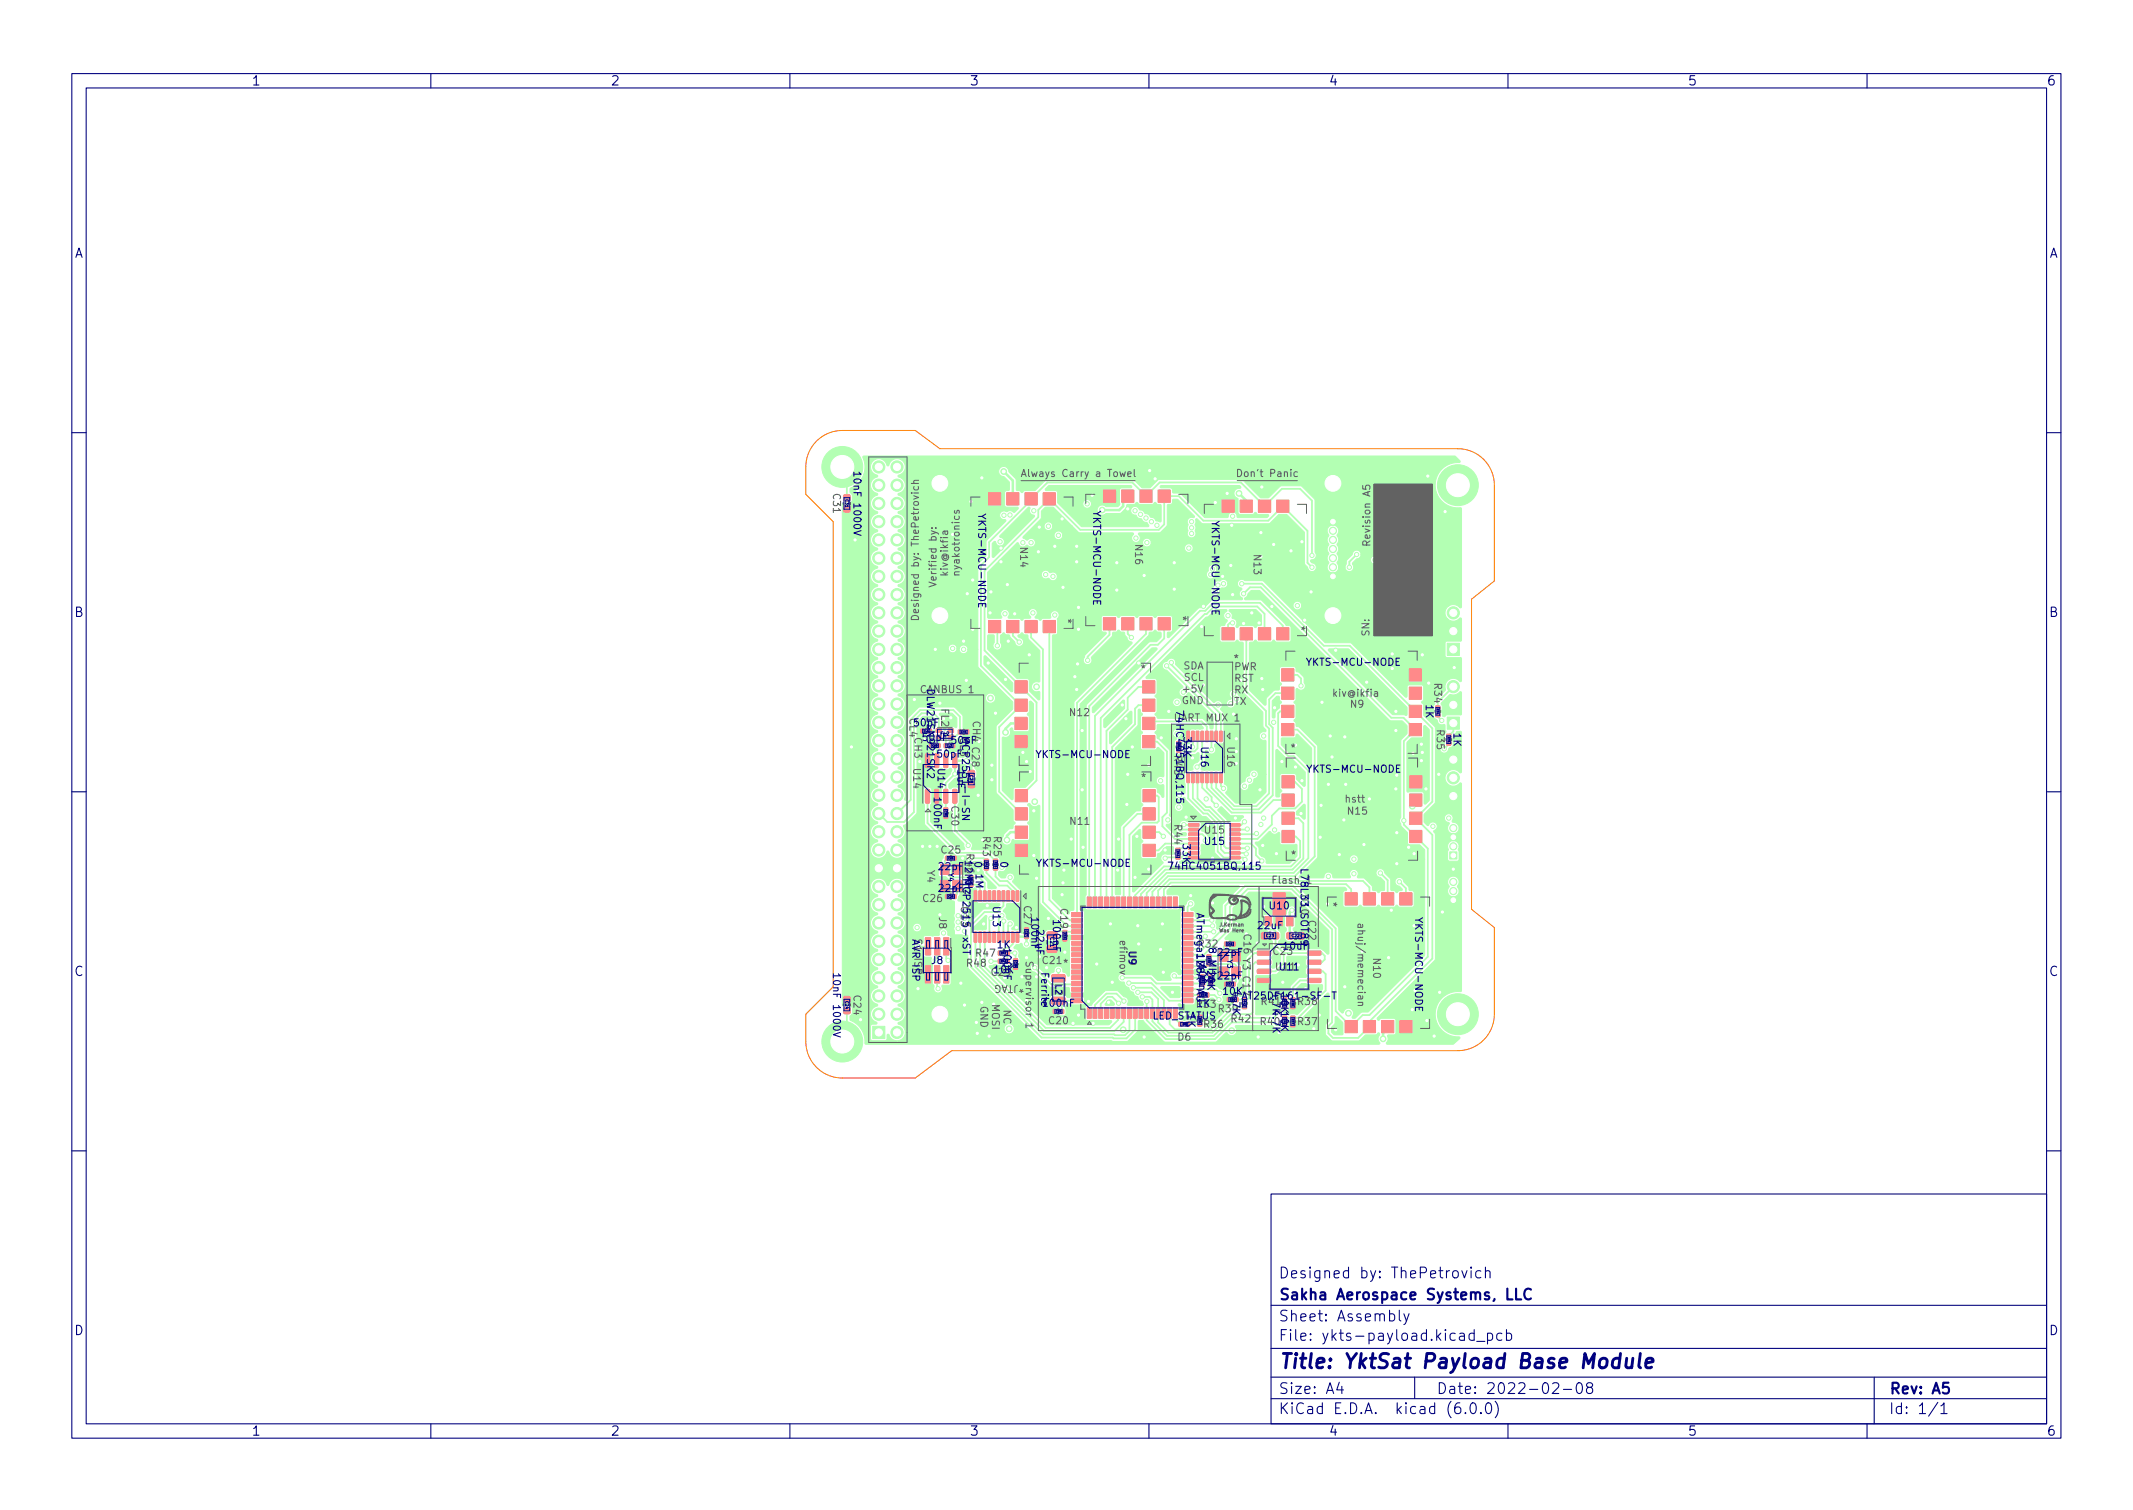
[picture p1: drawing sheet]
<svg xmlns="http://www.w3.org/2000/svg" width="297mm" height="210mm" viewBox="0 0 297 210" stroke-linecap="round" stroke-linejoin="round" font-family="sans-serif">
<defs><g id="words">
<text font-size="2.8" fill="#000080" x="178" y="190.6">Title: YktSat Payload Base Module</text>
<g font-size="2.1" fill="#000080">
<text x="178" y="178">Designed by: ThePetrovich</text>
<text x="178" y="184">Sheet: Assembly</text>
<text x="178" y="181">Sakha Aerospace Systems, LLC</text>
<text x="178" y="186.7">File: ykts-payload.kicad_pcb</text>
<text x="178" y="196.9">KiCad E.D.A. kicad (6.0.0)</text>
<text x="178" y="194.1">Size: A4</text>
<text x="200" y="194.1">Date: 2022-02-08</text>
<text x="263" y="194.1">Rev: A5</text>
<text x="263" y="196.9">Id: 1/1</text>
</g>
<g font-size="1.8" fill="#000080">
<text x="35" y="11.9">1</text>
<text x="85" y="11.9">2</text>
<text x="135" y="11.9">3</text>
<text x="185" y="11.9">4</text>
<text x="235" y="11.9">5</text>
<text x="285" y="11.9">6</text>
<text x="10.3" y="35.9">A</text>
<text x="285.3" y="35.9">A</text>
<text x="10.3" y="85.9">B</text>
<text x="285.3" y="85.9">B</text>
<text x="10.3" y="135.9">C</text>
<text x="285.3" y="135.9">C</text>
<text x="10.3" y="185.9">D</text>
<text x="285.3" y="185.9">D</text>
<text x="35" y="199.9">1</text>
<text x="85" y="199.9">2</text>
<text x="135" y="199.9">3</text>
<text x="185" y="199.9">4</text>
<text x="235" y="199.9">5</text>
<text x="285" y="199.9">6</text>
</g>
<g font-size="1.4" fill="#626262">
<text x="116" y="68.8" transform="rotate(90 116 68.8)">C31</text>
<text x="143" y="66.4">Always Carry a Towel</text>
<text x="172.7" y="66.4">Don't Panic</text>
<text x="142.1" y="76.3" transform="rotate(90 142.1 76.3)">N14</text>
<text x="158.1" y="75.9" transform="rotate(90 158.1 75.9)">N16</text>
<text x="174.6" y="77.3" transform="rotate(90 174.6 77.3)">N13</text>
<text x="190.8" y="75.7" transform="rotate(-90 190.8 75.7)">Revision A5</text>
<text x="130.4" y="81.9" transform="rotate(-90 130.4 81.9)">Verified by:</text>
<text x="132" y="81.1" transform="rotate(-90 132 81.1)">kiv@ikfia</text>
<text x="133.6" y="81.1" transform="rotate(-90 133.6 81.1)">nyakotronics</text>
<text x="128" y="85.6" transform="rotate(-90 128 85.6)">Designed by: ThePetrovich</text>
<text x="148.2" y="86.2" transform="rotate(90 148.2 86.2)">*</text>
<text x="164.2" y="85.8" transform="rotate(90 164.2 85.8)">*</text>
<text x="180.7" y="87.2" transform="rotate(90 180.7 87.2)">*</text>
<text x="190.7" y="88.6" transform="rotate(-90 190.7 88.6)">SN:</text>
<text x="158.9" y="93.6">*</text>
<text x="164.8" y="93.2">SDA</text>
<text x="164.9" y="94.8">SCL</text>
<text x="171.8" y="93.3">PWR</text>
<text x="171.8" y="94.9">RST</text>
<text x="171.9" y="92.2">*</text>
<text x="199.7" y="95.2" transform="rotate(90 199.7 95.2)">R34</text>
<text x="131.1" y="98.7" transform="rotate(90 131.1 98.7)">FL2</text>
<text x="135.5" y="100.5" transform="rotate(90 135.5 100.5)">CH4 C28</text>
<text x="149" y="99.7">N12</text>
<text x="164.6" y="98">GND</text>
<text x="165.2" y="96.4">+5V</text>
<text x="171.8" y="96.5">RX</text>
<text x="171.8" y="98.2">TX</text>
<text x="185.8" y="97">kiv@ikfia</text>
<text x="188.1" y="98.5">N9</text>
<text x="127.2" y="107.1" transform="rotate(90 127.2 107.1)">U14</text>
<text x="127.3" y="102.7" transform="rotate(90 127.3 102.7)">CH3</text>
<text x="170.9" y="104.1" transform="rotate(90 170.9 104.1)">U16</text>
<text x="179.8" y="104.6">*</text>
<text x="132.5" y="112.3" transform="rotate(90 132.5 112.3)">C30</text>
<text x="159" y="108.7">*</text>
<text x="187.4" y="111.7">hstt</text>
<text x="187.7" y="113.4">N15</text>
<text x="136.9" y="116.6" transform="rotate(90 136.9 116.6)">R43</text>
<text x="138.4" y="116.6" transform="rotate(90 138.4 116.6)">R25</text>
<text x="149.1" y="114.8">N11</text>
<text x="163.5" y="114.9" transform="rotate(90 163.5 114.9)">R44</text>
<text x="167.8" y="116.1">U15</text>
<text x="179.9" y="119.5">*</text>
<text x="128.6" y="125.6">C26</text>
<text x="129.1" y="121.2" transform="rotate(90 129.1 121.2)">Y4</text>
<text x="185.1" y="125.7" transform="rotate(90 185.1 125.7)">*</text>
<text x="130.8" y="127.7" transform="rotate(90 130.8 127.7)">J8</text>
<text x="147.7" y="126.6" transform="rotate(90 147.7 126.6)">C19</text>
<text x="155.9" y="131.1" transform="rotate(90 155.9 131.1)">efimov</text>
<text x="189.1" y="129.3" transform="rotate(90 189.1 129.3)">ahuj/memecian</text>
<text x="134.7" y="134.6">R48</text>
<text x="136" y="133.2">R47</text>
<text x="142.7" y="137.2" transform="rotate(-180 142.7 137.2)">*JTAG</text>
<text x="142.8" y="134.3" transform="rotate(90 142.8 134.3)">Supervisor 1</text>
<text x="145.2" y="134.2">C21</text>
<text x="148.1" y="134.6">*</text>
<text x="191.2" y="133.5" transform="rotate(90 191.2 133.5)">N10</text>
<text x="118.9" y="138.7" transform="rotate(90 118.9 138.7)">C24</text>
<text x="136.5" y="140.1" transform="rotate(90 136.5 140.1)">GND</text>
<text x="138.1" y="139.8" transform="rotate(90 138.1 139.8)">MOSI</text>
<text x="139.7" y="140.6" transform="rotate(90 139.7 140.6)">NC</text>
<text x="146.1" y="142.6">C20</text>
<text x="167.7" y="143.1">R36</text>
<text x="171.5" y="142.4">R42</text>
<text x="180.8" y="142.7">R37</text>
<text x="164" y="144.9">D6</text>
</g>
<g font-size="1.4" fill="#000080">
<text x="118.9" y="66.3" transform="rotate(90 118.9 66.3)">10nF 1000V</text>
<text x="152.2" y="71.8" transform="rotate(90 152.2 71.8)">YKTS-MCU-NODE</text>
<text x="136.2" y="72.2" transform="rotate(90 136.2 72.2)">YKTS-MCU-NODE</text>
<text x="168.7" y="73.2" transform="rotate(90 168.7 73.2)">YKTS-MCU-NODE</text>
<text x="182.5" y="92.7">YKTS-MCU-NODE</text>
<text x="126.6" y="100" transform="rotate(90 126.6 100)">CL4</text>
<text x="127.4" y="101.1">50pF</text>
<text x="128.3" y="96.5">CANBUS 1</text>
<text x="129.1" y="96.3" transform="rotate(90 129.1 96.3)">DLW21SN921SK2</text>
<text x="163.8" y="99.7" transform="rotate(90 163.8 99.7)">74HC4051BQ,115</text>
<text x="163.8" y="100.4">UART MUX 1</text>
<text x="198.6" y="98.2" transform="rotate(90 198.6 98.2)">1K</text>
<text x="200.1" y="101.7" transform="rotate(90 200.1 101.7)">R35</text>
<text x="128.6" y="103.2">50pF</text>
<text x="130.6" y="107.1" transform="rotate(90 130.6 107.1)">U14</text>
<text x="130.6" y="105.5">50pF</text>
<text x="132.6" y="103.6">50pF</text>
<text x="133.3" y="107.2" transform="rotate(90 133.3 107.2)">1uF</text>
<text x="133.7" y="102.7" transform="rotate(90 133.7 102.7)">CL3</text>
<text x="134" y="103.7" transform="rotate(90 134 103.7)">MCP2551-I-SN</text>
<text x="144.9" y="105.5">YKTS-MCU-NODE</text>
<text x="163.5" y="105.3" transform="rotate(90 163.5 105.3)">R45</text>
<text x="164.8" y="102.7" transform="rotate(90 164.8 102.7)">33K</text>
<text x="167.2" y="104.1" transform="rotate(90 167.2 104.1)">U16</text>
<text x="182.6" y="107.6">YKTS-MCU-NODE</text>
<text x="202.4" y="102.1" transform="rotate(90 202.4 102.1)">1K</text>
<text x="130" y="111.2" transform="rotate(90 130 111.2)">100nF</text>
<text x="131.1" y="118.8">C25</text>
<text x="134.4" y="120" transform="rotate(90 134.4 120)">12MHz</text>
<text x="134.6" y="119" transform="rotate(90 134.6 119)">R46</text>
<text x="164.7" y="117.6" transform="rotate(90 164.7 117.6)">33K</text>
<text x="167.8" y="117.6">U15</text>
<text x="130.8" y="124.2">22pF</text>
<text x="130.8" y="121.2">22pF</text>
<text x="134.1" y="123" transform="rotate(90 134.1 123)">MCP2515-xST</text>
<text x="135.7" y="120" transform="rotate(90 135.7 120)">0</text>
<text x="135.9" y="121.7" transform="rotate(90 135.9 121.7)">1M</text>
<text x="139.3" y="120" transform="rotate(90 139.3 120)">0</text>
<text x="145" y="120.7">YKTS-MCU-NODE</text>
<text x="163.4" y="121.1">74HC4051BQ,115</text>
<text x="177.5" y="123">Flash 1</text>
<text x="181.1" y="121.3" transform="rotate(90 181.1 121.3)">L78L33_SOT89</text>
<text x="181.2" y="124.7" transform="rotate(90 181.2 124.7)">U10</text>
<text x="127.3" y="131" transform="rotate(90 127.3 131)">S1 ISP</text>
<text x="133.8" y="126.4" transform="rotate(90 133.8 126.4)">U13</text>
<text x="138.3" y="126.4" transform="rotate(90 138.3 126.4)">U13</text>
<text x="142.6" y="126.2" transform="rotate(90 142.6 126.2)">C27</text>
<text x="143.6" y="127.9" transform="rotate(90 143.6 127.9)">100nF</text>
<text x="144.3" y="129.6" transform="rotate(90 144.3 129.6)">22uF</text>
<text x="146.6" y="128.3" transform="rotate(90 146.6 128.3)">100nF</text>
<text x="166.6" y="127.7" transform="rotate(90 166.6 127.7)">ATmega128A-AU</text>
<text x="166.9" y="131.9">R32</text>
<text x="173.2" y="130.2" transform="rotate(90 173.2 130.2)">C16 Y3 C17</text>
<text x="175.2" y="129.4">22uF</text>
<text x="176.9" y="126.6">U10</text>
<text x="182.2" y="128.3" transform="rotate(90 182.2 128.3)">C22</text>
<text x="197.1" y="128.4" transform="rotate(90 197.1 128.4)">YKTS-MCU-NODE</text>
<text x="116" y="136.1" transform="rotate(90 116 136.1)">10nF 1000V</text>
<text x="129.7" y="134.2">J8</text>
<text x="138.1" y="135.9">C29</text>
<text x="138.5" y="135.5">10K</text>
<text x="138.9" y="132">1K</text>
<text x="139.8" y="132.2" transform="rotate(90 139.8 132.2)">100nF</text>
<text x="145" y="135.6" transform="rotate(90 145 135.6)">Ferrite</text>
<text x="146.9" y="137" transform="rotate(90 146.9 137)">L2</text>
<text x="157.2" y="132.5" transform="rotate(90 157.2 132.5)">U9</text>
<text x="166.7" y="132.8" transform="rotate(90 166.7 132.8)">1M100nF</text>
<text x="168.1" y="135.2" transform="rotate(90 168.1 135.2)">20K</text>
<text x="168.3" y="132.2" transform="rotate(90 168.3 132.2)">8 MHz</text>
<text x="169.6" y="136.4">22pF</text>
<text x="169.6" y="133.1">22pF</text>
<text x="177.4" y="133">C23</text>
<text x="177.7" y="135.1">U11</text>
<text x="178.3" y="135.1">U11</text>
<text x="178.8" y="132.2">10uF</text>
<text x="145.4" y="140.2">100nF</text>
<text x="160.4" y="141.9">LED_STATUS</text>
<text x="165.4" y="141.2" transform="rotate(90 165.4 141.2)">1K</text>
<text x="166.7" y="140.2">1K</text>
<text x="169.7" y="141">R39</text>
<text x="170.4" y="138.5">10K</text>
<text x="171.6" y="138.2" transform="rotate(90 171.6 138.2)">4.7K</text>
<text x="174" y="139.2">AT25DF161-SF-T</text>
<text x="175.6" y="142.7">R40</text>
<text x="175.7" y="139.9">R41</text>
<text x="177.2" y="138.2" transform="rotate(90 177.2 138.2)">4.7K</text>
<text x="178.4" y="138.4" transform="rotate(90 178.4 138.4)">10K10K</text>
<text x="180.8" y="139.9">R38</text>
</g>
<g font-size="1" fill="#000080">
<text x="132.1" y="121.6" transform="rotate(90 132.1 121.6)">Y4</text>
<text x="170.9" y="133.6" transform="rotate(90 170.9 133.6)">Y3</text>
</g>
<g font-size=".7" fill="#000080">
<text x="131" y="102.4">FL2</text>
<text x="146.3" y="130.5" transform="rotate(90 146.3 130.5)">C21</text>
</g>
<g font-size=".7" fill="#626262">
<text x="169.9" y="129">J.Kerman</text>
<text x="169.9" y="129.8">Was Here</text>
</g>
<g font-size=".6" fill="#000080">
<text x="117.7" y="69.6" transform="rotate(90 117.7 69.6)">C31</text>
<text x="135.1" y="108" transform="rotate(90 135.1 108)">C28</text>
<text x="176.3" y="130.5">C23</text>
<text x="179.9" y="130.5">C22</text>
<text x="117.7" y="139.4" transform="rotate(90 117.7 139.4)">C24</text>
</g>
<g font-size=".4" fill="#000080">
<text x="200.1" y="98.7" transform="rotate(90 200.1 98.7)">R34</text>
<text x="164" y="103.7" transform="rotate(90 164 103.7)">R45</text>
<text x="201.6" y="102.7" transform="rotate(90 201.6 102.7)">R35</text>
<text x="163.9" y="118.5" transform="rotate(90 163.9 118.5)">R44</text>
<text x="135.1" y="122.3" transform="rotate(90 135.1 122.3)">R46</text>
<text x="137.2" y="120.1" transform="rotate(90 137.2 120.1)">R43</text>
<text x="138.5" y="120.1" transform="rotate(90 138.5 120.1)">R25</text>
<text x="139.4" y="134">R48</text>
<text x="139.4" y="132.8">R47</text>
<text x="167.3" y="136.2" transform="rotate(90 167.3 136.2)">R31</text>
<text x="168.2" y="133.4" transform="rotate(90 168.2 133.4)">R32</text>
<text x="167" y="141.8" transform="rotate(90 167 141.8)">R36</text>
<text x="167.3" y="138.7">R33</text>
<text x="171.3" y="139.3">R39</text>
<text x="173.2" y="139.4" transform="rotate(90 173.2 139.4)">R42</text>
<text x="178.8" y="139.4" transform="rotate(90 178.8 139.4)">R41</text>
<text x="178.8" y="141.9" transform="rotate(90 178.8 141.9)">R40</text>
<text x="179.9" y="139.4" transform="rotate(90 179.9 139.4)">R38</text>
<text x="179.9" y="141.9" transform="rotate(90 179.9 141.9)">R37</text>
</g>
<g font-size=".3" fill="#000080">
<text x="128.7" y="101.9">CL4</text>
<text x="129.8" y="103.9">CH3</text>
<text x="131.9" y="103.9">CL3</text>
<text x="133.8" y="102">CH4</text>
<text x="131.6" y="112.9" transform="rotate(90 131.6 112.9)">C30</text>
<text x="132.1" y="119.6">C25</text>
<text x="132.1" y="125">C26</text>
<text x="142.8" y="129.6" transform="rotate(90 142.8 129.6)">C27</text>
<text x="148.2" y="130" transform="rotate(90 148.2 130)">C19</text>
<text x="171" y="131.6">C16</text>
<text x="141.3" y="133.9" transform="rotate(90 141.3 133.9)">C29</text>
<text x="168.5" y="136.2" transform="rotate(90 168.5 136.2)">C18</text>
<text x="171" y="137.2">C17</text>
<text x="147.1" y="141">C20</text>
<text x="164.7" y="142.7">D6</text>
</g>
</g></defs>
<g fill="#b3ffb3" stroke="#b3ffb3" stroke-width=".14">
<path d="M169.8 107.6h.4v1.4l-.4-.1z"/>
<path d="M169.2 107.6h.4l-.1 1.4-.3-.1z"/>
<path d="M168.5 107.6h.4v1.4l-.4-.1z"/>
<path d="M167.9 107.6h.4l-.1 1.4-.3-.1z"/>
<path d="M167.2 107.6h.4v1.4l-.4-.1z"/>
<path d="M166.6 107.6h.4l-.1 1.4-.3-.1z"/>
<path d="M165.9 107.6h.4v1.4l-.4-.1z"/>
<path d="M165.3 107.6h.4l-.1 1.4-.3-.1z"/>
<path d="M165.3 101.8l.4 .1-.1 1.4-.3-.1z"/>
<path d="M165.9 101.8l.4 .1v1.4l-.4-.1z"/>
<path d="M166.6 101.8l.4 .1-.1 1.4-.3-.1z"/>
<path d="M167.2 101.8l.4 .1v1.4l-.4-.1z"/>
<path d="M167.9 101.8l.4 .1-.1 1.4-.3-.1z"/>
<path d="M168.5 101.8l.4 .1v1.4l-.4-.1z"/>
<path d="M169.2 101.8l.4 .1-.1 1.4-.3-.1z"/>
<path d="M169.8 101.8l.4 .1v1.4l-.4-.1z"/>
<path d="M171.3 114.7h1.4v.3l-1.4 .1z"/>
<path d="M171.3 115.3h1.4v.4h-1.4z"/>
<path d="M171.3 116h1.4v.3l-1.4 .1z"/>
<path d="M171.3 116.6h1.4v.4h-1.4z"/>
<path d="M171.3 117.3h1.4v.3l-1.4 .1z"/>
<path d="M171.3 117.9h1.4v.4h-1.4z"/>
<path d="M171.3 118.6h1.4v.3l-1.4 .1z"/>
<path d="M171.3 119.2h1.4v.4h-1.4z"/>
<path d="M165.5 119.2h1.4l.1 .4h-1.4z"/>
<path d="M165.5 118.6h1.4l.1 .3-1.4 .1z"/>
<path d="M165.5 117.9h1.4l.1 .4h-1.4z"/>
<path d="M165.5 117.3h1.4l.1 .3-1.4 .1z"/>
<path d="M165.5 116.6h1.4l.1 .4h-1.4z"/>
<path d="M165.5 116h1.4l.1 .3-1.4 .1z"/>
<path d="M165.5 115.3h1.4l.1 .4h-1.4z"/>
<path d="M165.5 114.7h1.4l.1 .3-1.4 .1z"/>
<path d="M175.1 132.5l1.8-.1 .1 .5-.2 .1h-1.6l-.1-.1z"/>
<path d="M175.1 133.7h1.8l.1 .5-.2 .1h-1.6l-.1-.2z"/>
<path d="M175.1 135h1.8l.1 .5h-.2h-1.6l-.1-.1z"/>
<path d="M175.1 136.3l1.8-.1 .1 .5-.2 .1h-1.6l-.1-.1z"/>
<path d="M182.1 136.3l1.8-.1 .1 .5-.2 .1h-1.6l-.1-.1z"/>
<path d="M182.1 135h1.8l.1 .5h-.2h-1.6l-.1-.1z"/>
<path d="M182.1 133.7h1.8l.1 .5-.2 .1h-1.6l-.1-.2z"/>
<path d="M182.1 132.5l1.8-.1 .1 .5-.2 .1h-1.6l-.1-.1z"/>
<path d="M176.2 127.6h.9v1.3h-.9z"/>
<path d="M179.2 127.6h.9v1.3h-.9z"/>
<path d="M177.3 124.3h1.7v3.1h-.4v1.5h-.9v-1.5h-.4z"/>
<path d="M163.8 119.1h.5v.5h-.5z"/>
<path d="M163.8 118.1h.5v.5h-.5z"/>
<path d="M173 139h.6v.4h-.6z"/>
<path d="M173 140h.6v.4h-.6z"/>
<path d="M170.9 138.9h.5v.6h-.5z"/>
<path d="M179.8 140h.5v.4h-.5z"/>
<path d="M179.8 141.5h.5v.5h-.5z"/>
<path d="M179.8 142.5h.5v.5h-.5z"/>
<path d="M177.3 129.9h.7v.8h-.7z"/>
<path d="M175.7 129.9h.8v.8h-.8z"/>
<path d="M179.3 129.9h.7v.8h-.7z"/>
<path d="M121.5 142.9h1.7v1.7h-1.7z"/>
<path d="M201.5 89.6h1.7v1.7h-1.7z"/>
<path d="M185.1 79.8h1v1h-1z"/>
<path d="M201.9 118.6h1v1h-1z"/>
<path d="M201.5 110h1.7v1.7h-1.7z"/>
<path d="M201.5 99.8h1.7v1.7h-1.7z"/>
<path d="M201.9 124.8h1v1h-1z"/>
<path d="M133.5 101.7h.4v.5h-.4z"/>
<path d="M134.4 101.7h.5v.5h-.5z"/>
<path d="M132 102.4h.8v.5h-.8z"/>
<path d="M132 101.5h.8v.5h-.8z"/>
<path d="M130.4 101.5h.7v.5h-.7z"/>
<path d="M138.4 120.7h.5v.4h-.5z"/>
<path d="M138.4 119.6h.5v.5h-.5z"/>
<path d="M132.7 124.6h.4v.5h-.4z"/>
<path d="M131.7 124.6h.5v.5h-.5z"/>
<path d="M169.8 134.6h1.2v1.4h-1.2z"/>
<path d="M171.5 134.6h1.2v1.4h-1.2z"/>
<path d="M159.1 94.8h1.7v1.7h-1.7z"/>
<path d="M159.1 97.3h1.7v1.7h-1.7z"/>
<path d="M159.1 99.9h1.7v1.7h-1.7z"/>
<path d="M159.1 102.4h1.7v1.7h-1.7z"/>
<path d="M141.3 94.8h1.7v1.7h-1.7z"/>
<path d="M141.3 97.3h1.7v1.7h-1.7z"/>
<path d="M141.3 99.9h1.7v1.7h-1.7z"/>
<path d="M141.3 102.4h1.7v1.7h-1.7z"/>
<path d="M141.2 133.5h.5v.5h-.5z"/>
<path d="M141.2 134.5h.5v.5h-.5z"/>
<path d="M146.5 135.8l1.7-.1 .1 .2v.7l-.2 .1h-1.5l-.2-.2z"/>
<path d="M130.4 103.6h.5v.5h-.5z"/>
<path d="M177.8 87.4h1.7v1.7h-1.7z"/>
<path d="M175.2 87.4h1.7v1.7h-1.7z"/>
<path d="M172.7 87.4h1.7v1.7h-1.7z"/>
<path d="M170.2 87.4h1.7v1.7h-1.7z"/>
<path d="M177.8 69.6h1.7v1.7h-1.7z"/>
<path d="M175.2 69.6h1.7v1.7h-1.7z"/>
<path d="M172.7 69.6h1.7v1.7h-1.7z"/>
<path d="M170.2 69.6h1.7v1.7h-1.7z"/>
<path d="M166.8 142.4h.6v.4h-.6z"/>
<path d="M187.3 124.3h1.7v1.7h-1.7z"/>
<path d="M189.9 124.3h1.7v1.7h-1.7z"/>
<path d="M192.4 124.3h1.7v1.7h-1.7z"/>
<path d="M194.9 124.3h1.7v1.7h-1.7z"/>
<path d="M187.3 142.1h1.7v1.7h-1.7z"/>
<path d="M189.9 142.1h1.7v1.7h-1.7z"/>
<path d="M192.4 142.1h1.7v1.7h-1.7z"/>
<path d="M194.9 142.1h1.7v1.7h-1.7z"/>
<path d="M139 133.6h.5v.5h-.5z"/>
<path d="M131.7 119.2h.5v.6h-.5z"/>
<path d="M132.7 119.2h.4v.6h-.4z"/>
<path d="M149.2 139.1h1.5v.5h-1.5z"/>
<path d="M149.2 138.3h1.5v.5h-1.5z"/>
<path d="M149.2 137.5h1.5v.5h-1.5z"/>
<path d="M149.2 136.7h1.5v.5h-1.5z"/>
<path d="M149.2 135.9h1.5v.5h-1.5z"/>
<path d="M149.2 135.1h1.5v.5h-1.5z"/>
<path d="M149.2 134.3h1.5v.5h-1.5z"/>
<path d="M149.2 133.5h1.5v.5h-1.5z"/>
<path d="M149.2 132.7h1.5v.5h-1.5z"/>
<path d="M149.2 131.9h1.5v.5h-1.5z"/>
<path d="M149.2 131.1h1.5v.5h-1.5z"/>
<path d="M149.2 130.3h1.5v.5h-1.5z"/>
<path d="M149.2 129.5h1.5v.5h-1.5z"/>
<path d="M149.2 128.7h1.5v.5h-1.5z"/>
<path d="M149.2 127.9h1.5v.5h-1.5z"/>
<path d="M149.2 127.1h1.5v.5h-1.5z"/>
<path d="M151.4 124.9h.6v1.5h-.6z"/>
<path d="M152.2 124.9h.6v1.5h-.6z"/>
<path d="M153 124.9h.6v1.5h-.6z"/>
<path d="M153.8 124.9h.6v1.5h-.6z"/>
<path d="M154.6 124.9h.6v1.5h-.6z"/>
<path d="M155.4 124.9h.6v1.5h-.6z"/>
<path d="M156.2 124.9h.6v1.5h-.6z"/>
<path d="M157 124.9h.6v1.5h-.6z"/>
<path d="M157.8 124.9h.6v1.5h-.6z"/>
<path d="M158.6 124.9h.6v1.5h-.6z"/>
<path d="M159.4 124.9h.6v1.5h-.6z"/>
<path d="M160.2 124.9h.6v1.5h-.6z"/>
<path d="M161 124.9h.6v1.5h-.6z"/>
<path d="M161.8 124.9h.6v1.5h-.6z"/>
<path d="M162.6 124.9h.6v1.5h-.6z"/>
<path d="M163.4 124.9h.6v1.5h-.6z"/>
<path d="M164.6 127.1h1.5v.5h-1.5z"/>
<path d="M164.6 127.9h1.5v.5h-1.5z"/>
<path d="M164.6 128.7h1.5v.5h-1.5z"/>
<path d="M164.6 129.5h1.5v.5h-1.5z"/>
<path d="M164.6 130.3h1.5v.5h-1.5z"/>
<path d="M164.6 131.1h1.5v.5h-1.5z"/>
<path d="M164.6 131.9h1.5v.5h-1.5z"/>
<path d="M164.6 132.7h1.5v.5h-1.5z"/>
<path d="M164.6 133.5h1.5v.5h-1.5z"/>
<path d="M164.6 134.3h1.5v.5h-1.5z"/>
<path d="M164.6 135.1h1.5v.5h-1.5z"/>
<path d="M164.6 135.9h1.5v.5h-1.5z"/>
<path d="M164.6 136.7h1.5v.5h-1.5z"/>
<path d="M164.6 137.5h1.5v.5h-1.5z"/>
<path d="M164.6 138.3h1.5v.5h-1.5z"/>
<path d="M164.6 139.1h1.5v.5h-1.5z"/>
<path d="M163.4 140.3h.6v1.5h-.6z"/>
<path d="M162.6 140.3h.6v1.5h-.6z"/>
<path d="M161.8 140.3h.6v1.5h-.6z"/>
<path d="M161 140.3h.6v1.5h-.6z"/>
<path d="M160.2 140.3h.6v1.5h-.6z"/>
<path d="M159.4 140.3h.6v1.5h-.6z"/>
<path d="M158.6 140.3h.6v1.5h-.6z"/>
<path d="M157.8 140.3h.6v1.5h-.6z"/>
<path d="M157 140.3h.6v1.5h-.6z"/>
<path d="M156.2 140.3h.6v1.5h-.6z"/>
<path d="M155.4 140.3h.6v1.5h-.6z"/>
<path d="M154.6 140.3h.6v1.5h-.6z"/>
<path d="M153.8 140.3h.6v1.5h-.6z"/>
<path d="M153 140.3h.6v1.5h-.6z"/>
<path d="M152.2 140.3h.6v1.5h-.6z"/>
<path d="M151.4 140.3h.6v1.5h-.6z"/>
<path d="M139 132.4h.5v.6h-.5z"/>
<path d="M117.5 138.8h.8v.8h-.8z"/>
<path d="M117.5 140.3h.8v.8h-.8z"/>
<path d="M201.5 103.3h.5v.4h-.5z"/>
<path d="M201.5 102.3h.5v.4h-.5z"/>
<path d="M141.5 124.1h.4l-.1 1.4-.3-.1z"/>
<path d="M140.9 124.1h.3v1.4l-.4-.1z"/>
<path d="M140.2 124.1h.4l-.1 1.4-.3-.1z"/>
<path d="M139.6 124.1h.3v1.4l-.4-.1z"/>
<path d="M138.9 124.1h.4l-.1 1.4-.3-.1z"/>
<path d="M138.3 124.1h.3v1.4l-.4-.1z"/>
<path d="M137.6 124.1h.4l-.1 1.4-.3-.1z"/>
<path d="M137 124.1h.3v1.4l-.4-.1z"/>
<path d="M136.3 124.1h.4l-.1 1.4-.3-.1z"/>
<path d="M135.7 124.1h.3v1.4l-.4-.1z"/>
<path d="M135.7 129.8h.3v1.4h-.4z"/>
<path d="M136.3 129.8h.4l-.1 1.4h-.3z"/>
<path d="M137 129.8h.3v1.4h-.4z"/>
<path d="M137.6 129.8h.4l-.1 1.4h-.3z"/>
<path d="M138.3 129.8h.3v1.4h-.4z"/>
<path d="M138.9 129.8h.4l-.1 1.4h-.3z"/>
<path d="M139.6 129.8h.3v1.4h-.4z"/>
<path d="M140.2 129.8h.4l-.1 1.4h-.3z"/>
<path d="M140.9 129.8h.3v1.4h-.4z"/>
<path d="M141.5 129.8h.4l-.1 1.4h-.3z"/>
<path d="M164.2 142.3h.5v.6h-.5z"/>
<path d="M178.5 100.7h1.7v1.7h-1.7z"/>
<path d="M178.5 98.2h1.7v1.7h-1.7z"/>
<path d="M178.5 95.7h1.7v1.7h-1.7z"/>
<path d="M178.5 93.1h1.7v1.7h-1.7z"/>
<path d="M196.3 100.7h1.7v1.7h-1.7z"/>
<path d="M196.3 98.2h1.7v1.7h-1.7z"/>
<path d="M196.3 95.7h1.7v1.7h-1.7z"/>
<path d="M196.3 93.1h1.7v1.7h-1.7z"/>
<path d="M137.1 119.6h.5v.5h-.5z"/>
<path d="M137.1 120.7h.5v.4h-.5z"/>
<path d="M131.5 103.6h.5v.5h-.5z"/>
<path d="M128.3 101.5h.4v.6h-.4z"/>
<path d="M171.5 136.8h.5v.5h-.5z"/>
<path d="M170.6 136.8h.4v.5h-.4z"/>
<path d="M159.2 109.9h1.7v1.7h-1.7z"/>
<path d="M159.2 112.5h1.7v1.7h-1.7z"/>
<path d="M159.2 115h1.7v1.7h-1.7z"/>
<path d="M159.2 117.6h1.7v1.7h-1.7z"/>
<path d="M141.4 109.9h1.7v1.7h-1.7z"/>
<path d="M141.4 112.5h1.7v1.7h-1.7z"/>
<path d="M141.4 115h1.7v1.7h-1.7z"/>
<path d="M141.4 117.6h1.7v1.7h-1.7z"/>
<path d="M145.3 86.4h1.7v1.7h-1.7z"/>
<path d="M142.7 86.4h1.7v1.7h-1.7z"/>
<path d="M140.2 86.4h1.7v1.7h-1.7z"/>
<path d="M137.7 86.4h1.7v1.7h-1.7z"/>
<path d="M145.3 68.6h1.7v1.7h-1.7z"/>
<path d="M142.7 68.6h1.7v1.7h-1.7z"/>
<path d="M140.2 68.6h1.7v1.7h-1.7z"/>
<path d="M137.7 68.6h1.7v1.7h-1.7z"/>
<path d="M131.4 112.5h.6v.5h-.6z"/>
<path d="M131.4 113.5h.6v.4h-.6z"/>
<path d="M147.6 140.6h.5v.5h-.5z"/>
<path d="M146.7 140.6h.5v.5h-.5z"/>
<path d="M178.5 115.6h1.7v1.7h-1.7z"/>
<path d="M178.5 113.1h1.7v1.7h-1.7z"/>
<path d="M178.5 110.5h1.7v1.7h-1.7z"/>
<path d="M178.5 108h1.7v1.7h-1.7z"/>
<path d="M196.3 115.6h1.7v1.7h-1.7z"/>
<path d="M196.3 113.1h1.7v1.7h-1.7z"/>
<path d="M196.3 110.5h1.7v1.7h-1.7z"/>
<path d="M196.3 108h1.7v1.7h-1.7z"/>
<path d="M128.9 109.9h.4l.2 .1v1.7l-.1 .1h-.5z"/>
<path d="M130.2 109.9h.4l.1 .1v1.7l-.1 .1h-.5z"/>
<path d="M131.4 109.9h.5l.1 .1v1.7l-.1 .1h-.5z"/>
<path d="M132.7 109.9h.4l.2 .1v1.7l-.1 .1h-.5z"/>
<path d="M132.7 105l.4-.1 .2 .1v1.7l-.1 .2-.5-.1z"/>
<path d="M131.4 105l.5-.1 .1 .1v1.7l-.1 .2-.5-.1z"/>
<path d="M130.2 105l.4-.1 .1 .1v1.7l-.1 .2-.5-.1z"/>
<path d="M142.7 130.2h.5v.5h-.5z"/>
<path d="M142.7 129.2h.5v.5h-.5z"/>
<path d="M132.7 122.6h1.2v1.4h-1.2z"/>
<path d="M131 122.6h1.2v1.4h-1.2z"/>
<path d="M199.9 98.3h.6v.5h-.6z"/>
<path d="M199.9 99.3h.6v.5h-.6z"/>
<path d="M134.9 107.3h.8v.8h-.8z"/>
<path d="M134.9 108.9h.8v.7h-.8z"/>
<path d="M170.6 131.2h.4v.5h-.4z"/>
<path d="M171.5 131.2h.5v.5h-.5z"/>
<path d="M148 129.6h.6v.5h-.6z"/>
<path d="M148 130.5h.6v.5h-.6z"/>
<path d="M145.9 129.8h1.2l.1 .2v.6l-.2 .1h-1.1l-.1-.2z"/>
<path d="M145.9 131.7h1.2l.1 .2v.6l-.2 .1h-1.1l-.1-.2z"/>
<path d="M117.5 70.5h.8v.8h-.8z"/>
<path d="M117.5 68.9h.8v.8h-.8z"/>
<path d="M161.3 86h1.7v1.7h-1.7z"/>
<path d="M158.7 86h1.7v1.7h-1.7z"/>
<path d="M156.2 86h1.7v1.7h-1.7z"/>
<path d="M153.7 86h1.7v1.7h-1.7z"/>
<path d="M161.3 68.2h1.7v1.7h-1.7z"/>
<path d="M158.7 68.2h1.7v1.7h-1.7z"/>
<path d="M156.2 68.2h1.7v1.7h-1.7z"/>
<path d="M153.7 68.2h1.7v1.7h-1.7z"/>
<path d="M131.4 130.6h.7v2.4h-.7z"/>
<path d="M131.4 134.5h.7v2.4h-.7z"/>
<path d="M130.1 130.6h.8v2.4h-.8z"/>
<path d="M130.1 134.5h.8v2.4h-.8z"/>
<path d="M128.9 130.6h.7v2.4h-.7z"/>
<path d="M128.9 134.5h.7v2.4h-.7z"/>
<path d="M120.2 63.6l.1-.1h82.3l.7 .7v.2a3.2 3.2 0 0 0-3.4 3.2 3.2 3.2 0 0 0 3.5 3.1l.1 .1v6.4h-14a.62 .62 0 0 0-.6-.6 .62 .62 0 0 0-.6 .7l-.8 .7v.5l-.2 .5h-.9l-.2-.6 .2-.7-.2-.6 .2-.7-.2-.5 .2-.7-.2-.6 .2-.7-.2-.5a.8 .8 0 0 0-.9-.2l-.3 .2-.2 .5 .3 .6-.3 .7 .3 .6-.3 .6 .3 .6-.3 .7 .3 .6-.2 .4a.8 .8 0 0 0 .5 1.1 .8 .8 0 0 0 1-.6v-.2h.9a.62 .62 0 0 0 .9 .5 .62 .62 0 0 0 .1-1l.6-.7 .5-.2 .1-.4h14v.8h-11.4a.6 .6 0 0 0-.9-.6 .6 .6 0 0 0-.1 1 .6 .6 0 0 0 1-.3v-.1h11.4v1.8l-7.6-.1a.6 .6 0 0 0-.9-.5 .6 .6 0 0 0-.1 1 .6 .6 0 0 0 1-.3v-.1h7.6v4.7a.16 .16 0 0 1-.1 .1 .16 .16 0 0 1-.2-.1l-.3-.2-.4-.1-.7 .1h-20.5a.61 .61 0 0 0-.9-.5 .61 .61 0 0 0-.1 1 .61 .61 0 0 0 1-.3v-.2h20.5a1.15 1.15 0 0 0-.1 1.9h-4.5l-.2-.4a.77 .77 0 0 0-.4-1 .63 .63 0 0 0-.7 .3 .63 .63 0 0 0 .1 .7 .62 .62 0 0 0 .3 1 .62 .62 0 0 0 .9-.6l4.5 .1a1.26 1.26 0 0 0 1.7-.3l.1 .2v3l-.1 .1h-2l-.2 .2v1.8l.3 .3 1.9-.1 .1 .1v3.2a.16 .16 0 0 1-.1 .1 .16 .16 0 0 1-.2-.1l-.3-.2a1.17 1.17 0 0 0-1.3 .2 1.17 1.17 0 0 0-.3 1.3l-1.4 1.4-.1 .5-.2 .3v.5l.1 .3-.1 .2v.5l.1 .2 .4 .3a.71 .71 0 0 0 1.1 .6l.1 .8a.25 .25 0 0 1-.1 .4l-.1 .6a.42 .42 0 0 1 0 .6v.3l-.1 .1a.62 .62 0 0 0-.5 .7 .62 .62 0 0 0 .7 .5 .62 .62 0 0 0 .6-.7l.5-.4 .1-.5a.49 .49 0 0 1 0-.6v-.3l.5-.5h.6v5.6l-.2 .1-.5-.4a1.17 1.17 0 0 0-1.5 .7 1.17 1.17 0 0 0 .5 1.5 1.17 1.17 0 0 0 1.6-.4l.1 .2v6.1h-.3l-.2-.5-.3-.2-.4-.1v-.3a.6 .6 0 0 0-.3-.9 .6 .6 0 0 0-.8 .5 .6 .6 0 0 0 .5 .7l.1 .2-.1 .3a.81 .81 0 0 0 .5 1.1 .81 .81 0 0 0 1-.8h.3v2.5h-.3v-.2a.8 .8 0 0 0-.8-.6l-.5 .2a.91 .91 0 0 0-.2 1.1l-.1 .3v1.2l.2 .1h1.2l.2-.2v-1.1l-.1-.3 .1-.5h.3v6.3h-.3l-.2-.6 .2-.7-.1-.4-.2-.2a.81 .81 0 0 0-.9-.1 .81 .81 0 0 0-.4 .7l.2 .7-.2 .6a.81 .81 0 0 0 .7 .8 .81 .81 0 0 0 .9-.7v-.1h.3v13.8l-.1 .2a3.2 3.2 0 0 0-3.2 1.8l-.3 1 .1 1.2a3.2 3.2 0 0 0 1.7 2l.7 .2 .8 .1 .1 .2-1 .8h-9.1l-.1-.2 .2-.6a.39 .39 0 0 1 .1-.5h.8l.1-.1v-2.1l-.2-.1h-1.8l-.2 .1a.19 .19 0 0 1-.2 .1 .19 .19 0 0 1-.1-.3l8.1-8.1v-17.4l-.2-.4v-.1a.62 .62 0 0 0 .3-1.1 .62 .62 0 0 0-1.1 .3h-.2l-.4-.4v-1l1.6-1.8v-10.4l-.1-.1-1.5-1.6-.1-1.6a.25 .25 0 0 1-.2-.2 .25 .25 0 0 1 .2-.3l.1-1.9-.2-.2h-2l-.1 .2-.1 1.4-.1 .1-.1-.1-7.5-7.4-.2-.1h-3.5l-8.5-8.6-.2-.1h-2.4a.64 .64 0 0 0-.7-.1 .64 .64 0 0 0-.4 .6l-1.3-.1a.64 .64 0 0 0-.5-.5 .64 .64 0 0 0-.7 .2 .65 .65 0 0 0-.8 .4v.3a.71 .71 0 0 0-.2 1.1 .63 .63 0 0 0 .8 .1 .63 .63 0 0 0 .2-.7l.4-.2a.61 .61 0 0 0 .8-.6h1.3a.79 .79 0 0 0 .6 .6v.2a.65 .65 0 0 0-.3 .6 .65 .65 0 0 0 .4 .6v.1l-.1 .1-4.1 .1-1.1 1-.8 .1-4.2 4.1-.1-.1v-.6l.4-.1 .3-.2-.1-2-.2-.1-1.9 .1a.25 .25 0 0 1-.2 .2 .25 .25 0 0 1-.3-.2l-1.9-.1-.2 .1a.17 .17 0 0 1-.2 .2 .17 .17 0 0 1-.1-.2l-.3-.1-1.9 .1a.25 .25 0 0 1-.2 .2 .25 .25 0 0 1-.3-.2l-1.9-.1-.2 .1v2l.2 .2 .4 .1 .1 .1-3.1 3.1a.88 .88 0 0 0 0 1.1 .63 .63 0 0 0 .9 0 .63 .63 0 0 0 .1-.9l2.9-2.9 .1-.5 .5-.1a.25 .25 0 0 1 .3-.3 .25 .25 0 0 1 .2 .3l.6 .1 .1 .4 .2 .2 .1 .4 .4 .3a.19 .19 0 0 1 .2 0 .19 .19 0 0 1 0 .2l-8 8v.2v28.8l-.1 .1-.5 .2a.25 .25 0 0 1-.1 .3 .25 .25 0 0 1-.2 0l-2.1-2.2v-36.5v-.1l.5-.1 .2-.1-.1-2 .1-.1a.61 .61 0 0 0 0-.9 .61 .61 0 0 0-.8-.1 .61 .61 0 0 0-.1 .8l-.2 .2-1.1 .1a.24 .24 0 0 1-.3 .2 .24 .24 0 0 1-.2-.3h-.4l-.1-.1 .1-.2a.61 .61 0 0 0 .1-.9 .61 .61 0 0 0-1 .1 .61 .61 0 0 0 .2 .9v.2h-.8l-.2 .1a.17 .17 0 0 1-.2 .2 .17 .17 0 0 1-.2-.2l-.2-.1h-1.4a.29 .29 0 0 1 0-.5 .61 .61 0 0 0-.6-.7 .61 .61 0 0 0-.5 .9l.1 .1-.1 .2-1.8-.1-.1-6.3 4.1-4.1h.2a.69 .69 0 0 0 .5 .5 .69 .69 0 0 0 .7-.2l.1 .1a.6 .6 0 0 0 .9 0 .6 .6 0 0 0 0-.9 .6 .6 0 0 0-.9 .1h-.1l-.5-.3v-.1l2.4-2.5 .1-1.1 .6-.6 1.1 .1 2.6 2.6h-2.7a.6 .6 0 0 0-.8-.6 .6 .6 0 0 0-.2 1 .6 .6 0 0 0 1-.3v-.1h2.7l1.1 .9h7.3l.2 .1-.2 .2h-9.7a.6 .6 0 0 0-1-.4 .6 .6 0 0 0 .2 1.1 .6 .6 0 0 0 .8-.7h9.7v.1a.6 .6 0 0 0 .5 .9 .6 .6 0 0 0 .5-.9l-.2-.3 .2-.1h2.8l1-.9 .1-.2v-2.7v-.1l.4-.1 .2-.1 .2-.6 .6 .1 2.3 2.2a.16 .16 0 0 1 0 .2 .16 .16 0 0 1-.2 .1 .64 .64 0 0 0-.7 .3 .64 .64 0 0 0 .1 .7l-.2 .4 .1 .3a.89 .89 0 0 0 .2 1 .61 .61 0 0 0 .8-.1 .61 .61 0 0 0 0-.8l.1-.4-.1-.5 .1-.5a.16 .16 0 0 1 0-.2 .16 .16 0 0 1 .2 0l.8 .6h9.2l1.4-1.3h1.1l2.4 2.5 .1 1.4h-21.4v-.1a.61 .61 0 0 0-1-.3 .61 .61 0 0 0 .2 1 .61 .61 0 0 0 .8-.6h21.4v.8h-15.5a.6 .6 0 0 0-1-.4 .6 .6 0 0 0 .1 1 .6 .6 0 0 0 .9-.6h15.5v2.1l.4 .6 .1 .2h-12.7a.62 .62 0 0 0-.8-.5 .62 .62 0 0 0-.4 .8l-.3 .3 .1 .5h-20.9a.67 .67 0 0 0-1-.6l-.1-.1a.61 .61 0 0 0-.9 0 .61 .61 0 0 0-.1 .8 .61 .61 0 0 0 .9 .1l.1 .1a.61 .61 0 0 0 .7 .2 .61 .61 0 0 0 .4-.5h20.9a.62 .62 0 0 0 .8 .2 .62 .62 0 0 0 .3-.7l.3-.6 12.7 .1a.61 .61 0 0 0 1-.1 .61 .61 0 0 0-.5-.9l-.2-.1a.17 .17 0 0 1 0-.2 .17 .17 0 0 1 .2-.1 .64 .64 0 0 0 .6-.4 .64 .64 0 0 0-.2-.6v-7.2v-.2l-1.8-1.8-.2-.1-2.7 .1-1.7 1.6h-1.1l-2.6-2.5h-.1h-11.5l-1.3 1.1h-1l-1.3-1.1h-12h-.2l-1.5 1.5h-1.4l-.2 .1a.17 .17 0 0 1-.2 .2 .17 .17 0 0 1-.2-.2l-.6-.2v-1.4l-1-1.1a.73 .73 0 0 0-.7-.8 .73 .73 0 0 0-.7 .8 .73 .73 0 0 0 .7 .7l.8 .8v1l-.6 .2-.1 .1v2l.2 .1h1.6l.1 .1-.6 .7-.6-.3-.5 .1a.61 .61 0 0 0-.9 .5 .61 .61 0 0 0 .8 .6l.1 .1-.1 .2-2.6 2.7-.1 2.1-1.1 1.2v11.8h-1.4a.6 .6 0 0 0-.5-.6 .6 .6 0 0 0-.7 .5l-.3-.1a.6 .6 0 0 0-1-.3 .6 .6 0 0 0 .1 1 .6 .6 0 0 0 .9-.6h.3a.6 .6 0 0 0 .5 .7 .6 .6 0 0 0 .7-.6h1.4v2.4l.1 .2 4.2 4.2h-1.9v-.2a.7 .7 0 0 0-1.1-.3 .7 .7 0 0 0 .1 1.1 .7 .7 0 0 0 1-.6h1.9l.5 .6v1l-2.2 2.2-.1 .2v9.1l.1 .2 2.3 2.3v1.4l.1 .2a.17 .17 0 0 1 .2 .2 .17 .17 0 0 1-.2 .2l-.1 .1v.4l-.6 .2-.7 .6-.1 .3a.73 .73 0 0 0 0 1 .73 .73 0 0 0 .9 .1l.3-.4a.21 .21 0 0 1 .2-.2 .21 .21 0 0 1 .2 .1h1.8l.2-.1v-2.1a.25 .25 0 0 1-.2-.2 .25 .25 0 0 1 .2-.2v-2.1a.24 .24 0 0 1-.1-.1 .24 .24 0 0 1 0-.3h.2l.3 .3 .3 .1 .7-.2 .1 .2v13.4l3.3 3.4-.1 .2h-1l-.4 .1h-.7l-.9 .6a.62 .62 0 0 0-.5 1 .62 .62 0 0 0 1.1-.1l.4 .1h1a.64 .64 0 0 0 .6-.7l.1-.1 .4 .2h.4l.4-.2 .3 .1h1.6l.2-.2v-3.1l-.1-.2-.4-.1-.1-.1v-28.5l9.5-9.6 .2-.5h.5a.25 .25 0 0 1 .2-.3 .25 .25 0 0 1 .3 .3l.6 .1v.7l-.6 .5-1.1 .1-8.7 8.8v26.4l-.2 .2v1.7l.3 .2h12.6l.3-.3-.1-1.7-.2-.1h-1.3l-.2-.2 .1-.4 .6-.7 9.4 .1v.2l-2.3 2.3-.1 2.9-.6 .6-.2-.2 .1-.3-.2-.4a.71 .71 0 0 0-.5-1l-.5 .2h-1.8l-.1-.8-.5-.2a.23 .23 0 0 1 0-.2 .23 .23 0 0 1 .2-.1 .62 .62 0 0 0 0-1.1 .62 .62 0 0 0-.9 .6l-.2 .2-.1 .6-.4 .1-.2 .2 .1 8 .2 .1h1.6l.3-.1h1.6l.8-.3h2.2l.1 1.4 .2 .3-.2 .4v.5l.2 .3h.6a.64 .64 0 0 0 .4-.6l.1-.2 .1-.4 .3-.1 .1-.2v-1.5a.38 .38 0 0 0-.4-.3l-.5-.4-.8-.2v-1.3l-.2-.3 .3-.4v-.5a.52 .52 0 0 0-.7-.4l-.1-.1v-.1l1.1-1.2v-2.9l2.2-2.3h5.8l2.5 2.5h-1.7a.6 .6 0 0 0-.5-.6 .6 .6 0 0 0-.7 .5l-.2 .3v.4l-.2 .3v1.4l.2 .3v.3l-.2 .3v.8a.82 .82 0 0 0 .8 .4 .82 .82 0 0 0 .7-.5v-.7l-.2-.2a.31 .31 0 0 1-.1-.4 .31 .31 0 0 1 .2-.2l.1-1.5-.1-.3 .2-.6h1.7l2.9 2.9-.1 3.2h-.2l-.4-.4-.5-.3h-1.7l-.4 .2h-2.8l-.9-.9a.78 .78 0 0 1 .3-.7l-.1-.9-.9-.9-.1-1.5-.2-.1-1.1 .1-.1 .2v1.4l1 .9v.8l.3 .4 .1 .7 1 1.1v1l-.9 .9a.24 .24 0 0 1-.3 0 .24 .24 0 0 1 0-.3l.2-.3v-.5l-.3-.3 .3-.5v-.4l-.2-.3-.2-.1h-1.7l-.8 .3-.9 1v5.1l-.7 .3-.4-.2h-.5l-.2 .1-.1 .2 .1 .9-3.2 3.1h-.7l-.1-.6-.4-.3-1.3 .2-.4-.2-.7 .1-.5-.1-.1-.2v-1.6l-.2-.2a.19 .19 0 0 1 .1-.3 .19 .19 0 0 1 .3 .2h1.7l.2-.2v-.5l.1-.1 .8 .1a.43 .43 0 0 1 .6 0h.4l.3-.2a.38 .38 0 0 1 .6 .3 .63 .63 0 0 0 .8 .4 .63 .63 0 0 0 .3-.9v-.1a.64 .64 0 0 0 .1-.7 .64 .64 0 0 0-.6-.3l-.4-.4-1.3-.1v-.6h.8l.2-.1 .1-.3v-.4l-.2-.3h-.8a.33 .33 0 0 1-.5-.1h-.5l-.4 .3h-.4l-.2-.1h-1.6a.38 .38 0 0 1-.6 0l-.3-.3-.5 .1a.66 .66 0 0 0-.1 1l-.1 .1h-1.8l-.9-.8h-3.6a.62 .62 0 0 0-1 .4 .62 .62 0 0 0 .8 .6l.3 .6 .4 .2 .2 .5 .3 .1a1.38 1.38 0 0 0 .8 .8l.2 .3 .4 .3 .1 .3v.2h-2.1l-.1-.1v-.1a.6 .6 0 0 0-.3-1h-.2l-1-.9h-1.5l-.2 .2h-2.8v-7.1l-.2-.2h-1.6l-.3 .2v4.8a.15 .15 0 0 1-.1 .1 .15 .15 0 0 1-.2-.1 .54 .54 0 0 0-.5-.4h-.1a.71 .71 0 0 0-.8-.9 .88 .88 0 0 0-.5 .9 .87 .87 0 0 0-.7 .6l-1.3-1.2a.62 .62 0 0 0-.6-.7 .62 .62 0 0 0-.6 .7 .62 .62 0 0 0 .6 .6l2.1 2 2.7 .1v.6l.3 .2h1.6l.2-.2h2.8l-1.6 1.6h-1.2v-.7l-.2-.2h-1.6l-.5 .1-.5-.4h-1.5l-.5 .3-.1 .9a.54 .54 0 0 0 .6 .5h.6v1l.4 .2h.4l.2-.1 .2-.2v-.5l-.2-.4 .2-.2a.4 .4 0 0 1 .3-.2 .4 .4 0 0 1 .4 .1h1.6l.2-.2h1.2l-.2 .3h-.7l-.2 .2v1.6l.1 .2 3.5 .1 .1 .2-.4 .4h-8.6l-8.1-8.1a.35 .35 0 0 1 .5-.2l.5-.1 .3 .2h.5a.44 .44 0 0 1 .6 0l.5-.1a.35 .35 0 0 1 .6-.1h.5l.2-.1 .1-.2v-.4a1.37 1.37 0 0 1-.1-1.1 .61 .61 0 0 0-.6-.4l-.1-.2 .3-.4h.4a.25 .25 0 0 1 .2-.1 .25 .25 0 0 1 .3 .1 .6 .6 0 0 0 .8 .5 .6 .6 0 0 0 .3-.9l.1-.5-.1-.5-.3-.3-.6 .1a.28 .28 0 0 1-.4 0 .28 .28 0 0 1-.1-.3l-.2-.1h-.7a.25 .25 0 0 1-.3-.3 .62 .62 0 0 0 .3-.7 .62 .62 0 0 0-.7-.4l-.3-.3a.98 .98 0 0 0-.5-.9l.4-.6 .1-.5h1.1a.64 .64 0 0 0 .9-.4v-1.4l-1.2-1.2v-.1a.61 .61 0 0 0-.1-1.1 .61 .61 0 0 0-.9 .6h-.6l-.3-.3v-.6a.74 .74 0 0 0 1-.6l-.3-.5-.5-.1v-.4l-.2-.3-.5-.1-.9-.9-2.3-.1-.1-.1a.76 .76 0 0 0 0-.9l-1.9-1.8v-3.4l.2-.3v-1.8l-.2-.3-.2-.1h-.5l-.2 .1a.2 .2 0 0 1-.2 .1 .2 .2 0 0 1-.2-.2l.1-.4 .7-.8a.67 .67 0 0 0 .6-.4 .67 .67 0 0 0-.1-.7l.2-.9h.6l.3 .2 .3 .3-.3 .4v.8l.1 .2 .3 .1a1.19 1.19 0 0 0 1-.1l.1-.3a.92 .92 0 0 0-.1-.9l-.1-.1-.1-.6-.5-.5a.63 .63 0 0 0-1-.5h-.5l-.1-.1a.5 .5 0 0 0-.4-.7h-.5l-.2 .2a.21 .21 0 0 1-.4-.1v-.3l.2-.4-.1-.8h.7l.4-.2a1.39 1.39 0 0 1 .9-.6l.1-.2v-.5l-.2-.4v-1.6l-1.2-1.2-4.8-.1-.2 .1-1.4 1.4-.1 .2v11l-.3 .3a.33 .33 0 0 1 0-.5v-.2a1.16 1.16 0 0 0-.7-1l-.3-.1v-.2a1.19 1.19 0 0 0 .9-1.4v-.2a1.14 1.14 0 0 0-.8-.7 .15 .15 0 0 1-.1-.1 .15 .15 0 0 1 .1-.2 1.17 1.17 0 0 0 .9-1.2 1.17 1.17 0 0 0-1-1.1v-.2a1.31 1.31 0 0 0 1-1.2 1.15 1.15 0 0 0-.7-1l-.2-.1a.15 .15 0 0 1-.1-.1 .15 .15 0 0 1 .1-.2 1.15 1.15 0 0 0 .8-.9 1.15 1.15 0 0 0-.4-1.2l-.4-.1a.15 .15 0 0 1-.1-.2 .15 .15 0 0 1 .1-.1 1.15 1.15 0 0 0 .9-1.2 1.15 1.15 0 0 0-.9-1.1l-.1-.1v-.1a1.19 1.19 0 0 0 1-1.2l-.1-.2a1.16 1.16 0 0 0-.6-.8l-.3-.2v-.2a1.17 1.17 0 0 0 .7-1.9l-.7-.4v-.2a1.18 1.18 0 0 0 1-1.2 1.18 1.18 0 0 0-1-1.2v-.1a1.29 1.29 0 0 0 1-1.3l-.2-.6-.3-.3-.5-.2v-.2a1.19 1.19 0 0 0 1-1.2l-.2-.6-.3-.3-.5-.2v-.2a1.18 1.18 0 0 0 1-1.2 1.18 1.18 0 0 0-1-1.2 .33 .33 0 0 1 .4-.3 1.16 1.16 0 0 0 .5-1.3l-.2-.5-.6-.4a.15 .15 0 0 1-.1-.1 .15 .15 0 0 1 .1-.2 1.15 1.15 0 0 0 .9-1.1 1.15 1.15 0 0 0-.9-1.1l-.1-.1v-.2a1.17 1.17 0 0 0 .7-1.9l-.5-.3a.19 .19 0 0 1-.2-.1 .19 .19 0 0 1 .1-.2 1.15 1.15 0 0 0 .9-1.2 1.15 1.15 0 0 0-.9-1.1l-.1-.1v-.1a1.19 1.19 0 0 0 1-1.2l-.2-.6-.3-.3-.5-.3v-.2a1.17 1.17 0 0 0 .8-1.8l-.3-.3-.5-.2v-.2a1.17 1.17 0 0 0 .7-2l-.4-.2a1.18 1.18 0 0 0-1.6 .8h-.3l-.2-.4-.4-.4a1.17 1.17 0 0 0-1.6 .7 1.17 1.17 0 0 0 .9 1.5v.1a1.22 1.22 0 0 0-.9 1 1.22 1.22 0 0 0 .4 1.2l.4 .2a.16 .16 0 0 1 .1 .2 .16 .16 0 0 1-.2 .1 1.18 1.18 0 0 0-.8 1.2 1.18 1.18 0 0 0 1 1.1v.1a1.22 1.22 0 0 0-.8 1.9l.3 .3 .4 .2a.16 .16 0 0 1 .1 .2 .16 .16 0 0 1-.2 .1 1.18 1.18 0 0 0-.8 1.2 1.18 1.18 0 0 0 1 1.1v.1a1.22 1.22 0 0 0-.6 2l.5 .3a.16 .16 0 0 1 .1 .2 .16 .16 0 0 1-.2 .2 1.18 1.18 0 0 0-.8 1.2 1.18 1.18 0 0 0 1 1v.2a1.22 1.22 0 0 0-.9 .9 1.22 1.22 0 0 0 .4 1.3l.4 .1a.16 .16 0 0 1 .1 .2 .16 .16 0 0 1-.2 .1 1.18 1.18 0 0 0-.8 1.2 1.18 1.18 0 0 0 1 1.1v.2a1.22 1.22 0 0 0-.6 2l.5 .3a.16 .16 0 0 1 .1 .2 .16 .16 0 0 1-.2 .1 1.18 1.18 0 0 0-.8 1.2 1.18 1.18 0 0 0 1 1.1v.1a1.22 1.22 0 0 0-.8 1.9l.3 .3 .4 .2a.16 .16 0 0 1 .1 .2 .16 .16 0 0 1-.2 .1 1.18 1.18 0 0 0-.8 1.2 1.18 1.18 0 0 0 1 1.1v.1a1.27 1.27 0 0 0-.9 1.5l.3 .6 .5 .3a.16 .16 0 0 1 .1 .2 .16 .16 0 0 1-.2 .1 1.16 1.16 0 0 0-.8 1.1 1.16 1.16 0 0 0 .9 1.1l.1 .1v.2a1.18 1.18 0 0 0-1 1.1 1.18 1.18 0 0 0 1 1.2v.1a1.22 1.22 0 0 0-.9 1 1.22 1.22 0 0 0 .4 1.2l.4 .2a.16 .16 0 0 1 .1 .2 .16 .16 0 0 1-.2 .1 1.18 1.18 0 0 0-.8 1.2 1.18 1.18 0 0 0 1 1.1v.1a1.22 1.22 0 0 0-.9 .9 1.22 1.22 0 0 0 .4 1.3l.4 .2a.16 .16 0 0 1 .1 .2 .16 .16 0 0 1-.2 .1 1.16 1.16 0 0 0-.8 1.1 1.16 1.16 0 0 0 .9 1.1l.1 .1v.2a1.16 1.16 0 0 0-1 1.1 1.16 1.16 0 0 0 .9 1.1 .16 .16 0 0 1 .1 .2 .16 .16 0 0 1-.2 .2 1.16 1.16 0 0 0-.3 1.9 1.16 1.16 0 0 0 1.9-.7h.1l.1 .1a1.15 1.15 0 0 0 1.9 .6 1.15 1.15 0 0 0-.5-2l-.1-.1v-.1a1.2 1.2 0 0 0 .7-2l.4-.2 1.4-1.5 .1-.1v-12.6l.8-.8 1.3-.1 .5 .5v.9l-.1 .1a.38 .38 0 0 1-.5 0h-.5l-.2 .1-.1 .2v.5l.1 .3 .2 .1 .8-.1 .1 .6 .2 .3-.3 .8v.7l-.2 .3 .1 2 .3 .2h.5l.4-.2 .4 .2h.4l.3-.2a.26 .26 0 0 1 .3 .1 .26 .26 0 0 1-.1 .4l-.1 .3-1 1.1v.8l-.2 .3v1.8l.2 .4-.2 .3v.5l.1 .2 .3 .1h.5l.3-.3 .2 .1 .1 2.7 1.6 1.6v.5a.26 .26 0 0 1 0 .4h-.8l-3.8-3.9v-2.3l.2-.3v-1.8l-.2-.3-.2-.1h-.6l-.2 .4v1.8l.1 .3 .1 2.7 4.3 4.3 1.5 .1a.67 .67 0 0 0 .2 .7 .67 .67 0 0 0 .7 .1l.2-.1h.9l.1 .2a.44 .44 0 0 1 0 .6v.4l.3 .7 1.7 1.7v.2h-1.1l-.1-.9-1-1-.7-.1-.4-.1h-.5l-.3 .1h-2.1v-.1v-1.3l-.1-.2 .1-.3v-.6l-.2-.3h-.6a.64 .64 0 0 0-.4 .6l-.2 .5-.3 .1-.1 .2v1.5l.2 .3h.8l.6 .5 .1 1.5a.37 .37 0 0 1-.1 .5l.1 .6 .5 .4v1.5l-.1 .4 .1 .4-.1 .5 .1 .5-.1 .3-4.5-.1a.61 .61 0 0 0-1-.4 .61 .61 0 0 0 .2 1.1 .61 .61 0 0 0 .8-.6h4.5l.1 1h1.8l.1 .1v3.4h-2.2l-.2-.5v-2.7l-.1-.2-.3-.1a.62 .62 0 0 0-.6-.9 .62 .62 0 0 0-.6 .8l-.1 .2-.8 .1-.3-.1h-.9l-.1 .2v.7a.28 .28 0 0 1-.5 0 .6 .6 0 0 0-.7 .7 .6 .6 0 0 0 .9 .4h.2l.1 .7 .1 .2 .9 .1 .1 .1v.5l.2 .4-.1 2.6 .3 .4a.63 .63 0 0 0 .4 .9 .63 .63 0 0 0 .7-.7v-.2l.1-.1h.9l.2-.3v-2.6l.2-.6h2.2l.1 1.2 8.3 8.3h-2l-.1-.4-.3-.2a.71 .71 0 0 0-.8 .3 .71 .71 0 0 0 0 .8h-13.9l-.2-.6-.3-.3-.4-.2a.15 .15 0 0 1-.1-.1 .15 .15 0 0 1 .1-.2 1.15 1.15 0 0 0 .9-.9 1.15 1.15 0 0 0-.7-1.2l-.2-.1a.15 .15 0 0 1-.1-.1 .15 .15 0 0 1 .1-.2 1.16 1.16 0 0 0 .8-1.4v-.1a1.14 1.14 0 0 0-.8-.7 .15 .15 0 0 1-.1-.2 .15 .15 0 0 1 .1-.1 1.16 1.16 0 0 0 .8-1.4l-.2-.6-.6-.3a.15 .15 0 0 1-.1-.1 .15 .15 0 0 1 .1-.2 1.15 1.15 0 0 0 .8-.9 1.15 1.15 0 0 0-.4-1.1l-.4-.2a.15 .15 0 0 1-.1-.1 .15 .15 0 0 1 .1-.2 1.15 1.15 0 0 0 .9-1 1.15 1.15 0 0 0-.7-1.2l-.2-.1a.15 .15 0 0 1-.1-.1 .15 .15 0 0 1 .1-.2 1.16 1.16 0 0 0 .8-1.3l-.2-.6-.6-.3a.15 .15 0 0 1-.1-.1 .15 .15 0 0 1 .1-.2 1.16 1.16 0 0 0 .8-1.4l-.2-.5-.6-.3a.15 .15 0 0 1-.1-.2 .15 .15 0 0 1 .1-.1 1.16 1.16 0 0 0 .8-1.4v-.1a1.16 1.16 0 0 0-1.2-.8 1.16 1.16 0 0 0-1 1h-.3l-.2-.5-.3-.3a1.15 1.15 0 0 0-1.7 .5 1.15 1.15 0 0 0 .8 1.6l.1 .1v.1a1.18 1.18 0 0 0-1 1.2 1.18 1.18 0 0 0 1 1.2v.1a1.23 1.23 0 0 0-.8 1.9l.3 .3 .4 .1a.16 .16 0 0 1 .1 .2 .16 .16 0 0 1-.2 .2 1.16 1.16 0 0 0-.8 1.1 1.16 1.16 0 0 0 .9 1.1l.1 .1v.1a1.18 1.18 0 0 0-1 1.2 1.18 1.18 0 0 0 1 1.2v.1a1.22 1.22 0 0 0-.8 1.9l.3 .3 .4 .2a.16 .16 0 0 1 .1 .2 .16 .16 0 0 1-.2 .1 1.18 1.18 0 0 0-.8 1.2 1.18 1.18 0 0 0 1 1.1v.1a1.27 1.27 0 0 0-.9 1.5l.1 .4 .4 .3a.22 .22 0 0 1 .3 .1 .22 .22 0 0 1-.1 .3h-.5l-.3 .2v1.9l.2 .2h1.9l.2-.2 .1-.7h.2a1.17 1.17 0 0 0 1.3 .9 1.17 1.17 0 0 0 1-1.2h13.9a.71 .71 0 0 0 .8 .2 .71 .71 0 0 0 .4-.7h2l1.6 1.6 .2 .1h9.7l.3 .1h1.9l.2-.1 1.4-1.3v-1.4l.2-.1h.5l2.9 2.9 .2 .1h7l1.4-1.3h.2a.72 .72 0 0 0 1.1 .2 .72 .72 0 0 0 0-1.1l.2-.1h4.9l.6 .4h.6l.4 .1h.6l.2-.3v-.7h.8l.8-.2 3.8-3.8 .2 .1v3.7l-.5 .6v1.3l.8 .9h.2h3.6l.9-.8h1.6a.24 .24 0 0 1 .2-.2 .24 .24 0 0 1 .2 0v.2a.77 .77 0 0 0 0 1v.2l-.1 .1h-71.4l-.1-.1a3.3 3.3 0 0 0-2.1-3.3v-.5l.3-.4v-.6a.53 .53 0 0 0-.5-.5h-.8l-.1-.1v-69.7l.1-.2 .2 .1a.81 .81 0 0 0 1.1-.4v-.7l-.3-.5v-.4l.1-.2a3.3 3.3 0 0 0 1.7-4.3z"/>
<path d="M186 141.6h.2l.8 .8v1.5v.2h-1.2l-.4-.4v-.6l.5-.6z"/>
<path d="M173.8 82.6l.5-.4 1.2 .1 18 18 1.8 .1 .6 .6v1.1l-.8 1v10.7a.73 .73 0 0 0 0 .9v.4l.9 .8 .1 1.6 .2 .1 1.4 .1 .7 .6v1.3h-9.3a.6 .6 0 0 0-.8-.5 .6 .6 0 0 0-.1 1 .6 .6 0 0 0 .9-.3v-.2h9.3v13.4l-7.8 7.9-1 .1-.9 .8h-.3l-.1-.2a.72 .72 0 0 0-.2-1.1 .72 .72 0 0 0-1 .5h-.3l-.4-.5v-11.4l-5.3-5.3v-.2l.1-.1h6.1l.2 .4v.1l-.4 .1-.1 .1 .1 2 .2 .1h1.9a.25 .25 0 0 1 .2-.3 .25 .25 0 0 1 .3 .3h2a.23 .23 0 0 1 .2-.2 .23 .23 0 0 1 .2 .1l.2 .1h2a.25 .25 0 0 1 .2-.3 .25 .25 0 0 1 .3 .3h1.9l.2-.2v-1.9l-.2-.2-.5-.1-.1-.5-.6-.7a.61 .61 0 0 0-.7-.5 .61 .61 0 0 0-.5 .7 .61 .61 0 0 0 .6 .5l.4 .4v.1l-.6 .2a.17 .17 0 0 1-.2 .2 .17 .17 0 0 1-.2-.2l-.6-.2v-1.5l-.8-.8a.63 .63 0 0 0-.6-.7 .63 .63 0 0 0-.7 .7 .63 .63 0 0 0 .7 .6l.5 .5v1.2l-.1 .1-.5 .1a.25 .25 0 0 1-.2 .2 .25 .25 0 0 1-.3-.2l-.6-.2v-.6l-1-1-1-.1-.1-.1v-.1a.6 .6 0 0 0-.3-.9 .6 .6 0 0 0-.8 .6l.1 .1a.25 .25 0 0 1-.1 .4h-2.2l-.1-.1a.62 .62 0 0 0-.6-.7 .62 .62 0 0 0-.6 .8h-.2h-3.1l-.2-.1 2.6-2.8v-15.4l-.1-.1-2.5-2.6-.4-.1-.1-.5a.25 .25 0 0 1-.2-.3 .25 .25 0 0 1 .2-.2v-2.1a.25 .25 0 0 1-.2-.2 .25 .25 0 0 1 .2-.3l.1-1.6h.1h.1a.62 .62 0 0 0 .9 0 .62 .62 0 0 0 0-.9v-.7l-.7-.7-.4-.1v-.4l-.2-.2-1.9-.1-.2 .3v1.8l.1 .2a.17 .17 0 0 1 .2 .1 .17 .17 0 0 1-.2 .2l-.2 .7-.7 .1-1 .9-.1 1-.1 .1h-.1l-2.1-2.1v-6.5l.1-.2h.5a.25 .25 0 0 1 .2-.3 .25 .25 0 0 1 .3 .3h2a.25 .25 0 0 1 .3-.3 .25 .25 0 0 1 .2 .3h2.1l.1-.2-.1-2-.1-.1h-.5l-3.4-3.5-2.2-.1a.16 .16 0 0 1-.2-.2 .16 .16 0 0 1 .2-.1l.2-.2z"/>
<path d="M174.9 135.8h2l.4-.1 .6-.1 1.2-1.3 .2-1.1 2.5-.1a.24 .24 0 0 1 .2 .3 .24 .24 0 0 1-.2 .2v.7a.29 .29 0 0 1 .2 .3 .29 .29 0 0 1-.2 .3v.6l.1 .2a.2 .2 0 0 1 .1 .3 .2 .2 0 0 1-.2 .1h-.9l-1.2 1.1-.1 1.4a.29 .29 0 0 1-.4 0h-.6l-.3 .2v.6l.1 .3-.1 .5-1.1 1.1h-2.3z"/>
<path d="M180.5 137.6l.8-.7h.5l.4 .2h1.8l.2 .1-.1 .6-3.4 3.4h-.9a.49 .49 0 0 1-.7 0l-.3-.1a.27 .27 0 0 1 .1-.3 .27 .27 0 0 1 .3 0l.3-.3v-.5a.19 .19 0 0 1 0-.3 .19 .19 0 0 1 .3 .1l.6-.1 .3-.3v-.4l-.2-.4z"/>
<path d="M153.9 139.7l.5-.4 .3-.1 .4 .5 .1 .1-.2 .2h-1l-.1-.1z"/>
<path d="M161.7 137.4h.1h2.5v1.4l-1.3 .1-1.3-1.3z"/>
<path d="M135.7 129l1.5-1.5a.22 .22 0 0 1 .3 .1 .22 .22 0 0 1-.1 .3l-.1 1.5-.5 .1h-.8a.3 .3 0 0 1-.3-.1 .3 .3 0 0 1-.1-.3z"/>
<path d="M134.2 123.7l.4-.1 .3 .2h.6a.34 .34 0 0 1 .5 0v1.6a.63 .63 0 0 0 .9 .4h1.9h.4l.1 .2-.7 .6h-1.7l-1.9 1.9a.45 .45 0 0 1-.1-.6l-.1-.4 .1-.5-.1-.4 .1-.5-.1-.6h-1.3l-.1-.1 .3-1.1 .4-.2z"/>
<path d="M158.5 98.8l.2-.1 .1 .1 .1 .4a.25 .25 0 0 1 .2 .3 .25 .25 0 0 1-.2 .2v2.1a.25 .25 0 0 1 .2 .2 .25 .25 0 0 1-.2 .2l-.1 2 .1 .2h2l.4-.3 .8 .7-.1 3.3a.71 .71 0 0 0-1 .6 .69 .69 0 0 0 1 .6l.1 1.6a.19 .19 0 0 1-.2 .1 .19 .19 0 0 1-.2-.2l-.5-.5v-.4l-.3-.3h-1.8l-.2 .3v1.8a.39 .39 0 0 1 .2 .4 .39 .39 0 0 1-.2 .3l-.1 .5-.7 .1-2 2.1v9.3l-.2 .2h-.5l-.1-.2v-20.1l3.1-3.3z"/>
<path d="M157.8 116.4l.8-.9h.2l.1 1.3a.39 .39 0 0 1 .2 .3 .39 .39 0 0 1-.2 .4v1.8l.2 .3h1.8l.3-.3v-.4l.4-.1 .8-.9h1l.1 1-1 .1a.62 .62 0 0 0-.8 .3v.5a.34 .34 0 0 1 .2 .5l-3.9 3.9h-.2l-.1-.1z"/>
<path d="M161.1 101l.2-.1h5.8l.5 .5-.2 .1h-.9a.64 .64 0 0 0-.9 .4l.1 1.5-.1 .2h-.2l-.5-.5-.8-.2v-.1a.64 .64 0 0 0 .4-.8 .64 .64 0 0 0-.7-.5 .65 .65 0 0 0-.5 .7 .65 .65 0 0 0 .6 .6l-.4 .5 .1 .5a.33 .33 0 0 1-.1 .5l.1 .6 .3 .2h2.5l.5-.3 .1 1.1-.3 .3a.63 .63 0 0 0-.6 .8 .19 .19 0 0 1 0 .2 .19 .19 0 0 1-.2 0v.1a.64 .64 0 0 0-.9 .3v2.8l-.1 .1-.2-.2a.61 .61 0 0 0-.9 .1 .61 .61 0 0 0 .1 .9 .61 .61 0 0 0 .9-.3l.2 .1 .1 .3 1 1h-1.3a.6 .6 0 0 0-.9-.6 .6 .6 0 0 0-.1 1 .6 .6 0 0 0 1-.4h1.3l1.2 1.2 .7 .1 1.1 1.2v3.7l1.1 1.2 1.1 .1h1.4a.16 .16 0 0 1 .2 .2 .16 .16 0 0 1-.2 .1h-8.3a.23 .23 0 0 1-.1-.2 .23 .23 0 0 1 .3-.2l.8-.6 1.5 .1 .2-.1 .2-.3v-1.2a.17 .17 0 0 1 .1-.2 .17 .17 0 0 1 .1 .1 .65 .65 0 0 0 .9-.3 .65 .65 0 0 0-.1-.8l-.1-.2-.7-.5a.29 .29 0 0 1-.2-.2 .29 .29 0 0 1 0-.3v-.7l-.3-.2h-1.6a.65 .65 0 0 0-.7-.2 .65 .65 0 0 0-.5 .6l-.1 .1a.61 .61 0 0 0-.3 .8 .61 .61 0 0 0 .9 .2l.4 .1 .1 .3-1.4 .1-1.4-1.4 .1-.2a.64 .64 0 0 0 .7-.5 .64 .64 0 0 0-.4-.7l.1-.4v-8.6v-.2l-1.5-1.5-.3-.1v-.6a.25 .25 0 0 1-.3-.2 .25 .25 0 0 1 .3-.2z"/>
<path d="M174.9 117.3l.5-.1 1.3-1.4h.2a.68 .68 0 0 0 1.2 .1l.1 .1v1.4l.2 .2h1.9h.2h.1v1.6l-1.1 1h-3l-.2-.2a.65 .65 0 0 0-.6-.8l-.4-.3v-.9l-.5-.5z"/>
<path d="M169.9 112.4h.2l1.3 1.2h1.6a.16 .16 0 0 1 .2 .1 .16 .16 0 0 1-.2 .2l-.4 .5h-1.6l-.2-.3-1.2-1.2v-.2z"/>
<path d="M180.5 113l1-1h.2l.1 .1-.1 1.9h-.2l-.5-.4-.4-.1z"/>
<path d="M196 103.3l.5-.5 1.6-.1 .2-.2v-1.3l.1-.2 .6 .6v9.8l-.5 .6h-.1l-.1-.2v-1.3l-.1-.2h-2.1l-.2-.1z"/>
<path d="M167.9 86l.4-.2 .9-.9h1.5a.16 .16 0 0 1 .2 .1 .16 .16 0 0 1-.2 .2 .67 .67 0 0 0-.3 .7 .67 .67 0 0 0 .5 .5l-.4 .7h-.4l-.2 .2v1.9l.2 .2h1.9a.25 .25 0 0 1 .3-.3 .25 .25 0 0 1 .2 .3h.6v.2v6.7l.9 1h-1.2l-.1-.3-.3-.3a.62 .62 0 0 0-.8-.6 .65 .65 0 0 0-.4 .5 .65 .65 0 0 0 .3 .6l-.1 .2h-.2a.61 .61 0 0 0-.4 .7 .61 .61 0 0 0 .7 .5 .61 .61 0 0 0 .5-.6l.6-.2 .2-.5h1.2l1.8 1.9 .1 1.9 .4 .5v.3a.7 .7 0 0 0-.9 .7 .7 .7 0 0 0 .8 .5l.1 .1v4.6h-1.1a.61 .61 0 0 0-.7-.6 .61 .61 0 0 0-.5 .8l-.1 .1a.82 .82 0 0 0-.6 .7 .62 .62 0 0 0-.6 .7 .62 .62 0 0 0 .7 .6 .62 .62 0 0 0 .5-.8l.1-.1a.73 .73 0 0 0 .7-.8l.4-.2 .1-.4h1.1v2.5l-1.5 1.5h-2.7l-1.4-1.3v-.2a.66 .66 0 0 0-.2-1.2v-1.5a.64 .64 0 0 0-.9-.3h-1.9l-.4-.1v-.4l.5-.6v-1.6l.1-.1h.2a.63 .63 0 0 0 .9 .4 .63 .63 0 0 0 .1-1l.1-.3 .4-.1a.64 .64 0 0 0 .9-.3l-.1-3.8-.4-.6a.66 .66 0 0 0 .2-.8 .66 .66 0 0 0-.6-.4l-.5 .2h-.1l-5.3-5.2a.69 .69 0 0 0-.2-.7 .69 .69 0 0 0-.7-.2l-.3 .4a.62 .62 0 0 0-.6 .6 .62 .62 0 0 0 .6 .6l2.2 2.3v.2a.62 .62 0 0 0-.3 1 .62 .62 0 0 0 1-.3h.2l1.3 1.3h-2.4a.6 .6 0 0 0-.9-.6 .6 .6 0 0 0-.1 1.1 .6 .6 0 0 0 1-.4v-.1h2.4l2 2v1.6l-.3 .1-.2-.6-1-.9h-6.1h-.2v-.3a.25 .25 0 0 1-.3-.2 .25 .25 0 0 1 .3-.3v-2a.24 .24 0 0 1-.2-.4l.2-.3v-1.9l-.2-.1h-1.2l-.1-.1v-.2z"/>
<path d="M143.4 97.7h.2l.3 .3v10.5l-1.1 1.1-1.6 .1-.1 .2v1.3l-.1 .2-.2-.1-1.2-1.3v-7.2l.1-.2 .3 .1a.71 .71 0 0 0 .7-.7 .4 .4 0 0 1 .2-.7l.1 .1 .1 .4 .2 .1 1.9-.1 .1-.2v-1.9a.25 .25 0 0 1-.2-.4l.2-.2z"/>
<path d="M177.7 104.4h.2l1.3 1.3h.8l1.8 1.9v1.8l-.1 .1-1.2-1v-.6l-.1-.1h-2l-.2 .2 .1 1.9a.25 .25 0 0 1 .2 .2 .25 .25 0 0 1-.2 .3l-.1 .5h-.5z"/>
<path d="M178.5 102.8l1.7-.1 .2-.1 .1-.3 .2-.1 1.9 1.9v2.8h-.2l-2-2-.9-.1-1-1.1-.1-.8z"/>
<path d="M154.6 101.9l2.8-2.8h.2v1.6l-2.9 2.9-.2-.2z"/>
<path d="M130.9 99.3h1.7l.6 .7 .1 1.2a.24 .24 0 0 1-.3 .1 .24 .24 0 0 1-.2-.1h-.8l-.3 .2a.18 .18 0 0 1-.1 .3 .18 .18 0 0 1-.2-.3l-.2-.3v-1.1l-.4-.5z"/>
<path d="M156.4 97.5h.1l.1 .1v1.1l-2.6 2.6h-.2l-.1-.1 .1-1.1z"/>
<path d="M177.2 97.5l.7-.6 .3 .1v.4a.39 .39 0 0 1 .2 .4 .39 .39 0 0 1-.2 .3l-.1 .5-.5 .6-.1 .7-.3 .1v-.2z"/>
<path d="M200.7 97.9l1.2-1.2a1.49 1.49 0 0 0 1.4-.3l.2-.1v.2v3l-.1 .1h-2a.26 .26 0 0 1-.3 .2 .26 .26 0 0 1-.3-.2v-.4a.34 .34 0 0 1 0-.5z"/>
<path d="M185 90.4h2.8l8.1 8.1v1.1l-2-.1-8.9-8.9z"/>
<path d="M160.4 90.3l.6-.1 .1 .2-8.7 8.8h-.2v-.7z"/>
<path d="M137.6 88.5l.1-.1 .7 .1 .1 .9a.62 .62 0 0 0 0 .9 .62 .62 0 0 0 .9 0 .62 .62 0 0 0-.1-.9v-.9l.2-.1a.25 .25 0 0 1 .3-.3 .25 .25 0 0 1 .2 .2l.5 .1 .2 .4 .6 .6a.63 .63 0 0 0 .6 .6 .63 .63 0 0 0 .6-.6 .63 .63 0 0 0-.6-.6l-.1-.2a.16 .16 0 0 1 0-.1 .16 .16 0 0 1 .2-.1h.1a.25 .25 0 0 1 .2-.3 .25 .25 0 0 1 .3 .2l.5 .2 .1 .5 1.6 1.6v4.2l-.1 .2h-.1a.71 .71 0 0 0-1 .7 .71 .71 0 0 0 1.1 .6l.1 .1v.9l-.2 .2-1.2-1.3-.1-1.4-.1-.3h-1.6l-4-4.1z"/>
<path d="M137.1 91.3h.2l3.7 3.8v1.2h-.2l-3.7-3.7z"/>
<path d="M171.2 84.9h.1h3.6l.8 .8v1.3l-.6 .2a.25 .25 0 0 1-.3 .2 .25 .25 0 0 1-.2-.2h-2.1a.21 .21 0 0 1-.1 .2 .21 .21 0 0 1-.3-.2l.1-.2a.61 .61 0 0 0-.4-.8v-.1a.28 .28 0 0 1-.2-.4l-.1-.3-.3-.3z"/>
<path d="M138.2 75.6l.2-.2a.28 .28 0 0 1 .3 .3 .61 .61 0 0 0 1.1 0 .61 .61 0 0 0-.5-.9v-.2l3.9-3.9 .2-.1v.1a.67 .67 0 0 0 .6 1.1v.2l-5.7 5.6-.1-.1z"/>
<path d="M145.6 68.1l.5-.5h11.3a.17 .17 0 0 1 .2 .2 .17 .17 0 0 1-.1 .1h-1.3l-.3 .2v2.1l-3.9-.1a.61 .61 0 0 0-1-.4 .61 .61 0 0 0 .1 1 .61 .61 0 0 0 .9-.5h3.9v.1l-.3 .2h-1.6l-.4-.2a.7 .7 0 0 0-.8 .9 .7 .7 0 0 0 1.1 .4l.2-.1h1.9l.8-.8 .2-.4 1.1-.1a.25 .25 0 0 1 .2-.2 .25 .25 0 0 1 .3 .2h2a.25 .25 0 0 1 .2-.2 .25 .25 0 0 1 .3 .2l.5 .1 .1 .1v2.1l-.2 .2-.5-.2a1.24 1.24 0 0 0-.8-.6l-.3-.3-.5-.1-.3-.4-.4-.1-.3-.4-.4-.1a.63 .63 0 0 0-.5 .7 .63 .63 0 0 0 .7 .5l.2 .4 .4 .1a.32 .32 0 0 1 .4 .4l.5 .2 .3 .5h-.2h-9.2l-3.3-3.3-.1-1.6-.2-.1h-1.3l-.1-.1z"/>
<path d="M161.6 67.7l.1-.1h10.9l.2 .2v.2h-.2a.7 .7 0 0 0-.7 .5 .7 .7 0 0 0 .4 .9l.1 .1v2l.3 .1h1.9a.25 .25 0 0 1 .2-.3 .25 .25 0 0 1 .3 .3h1.5l.1 .2-.3 .3h-4l-.1-.1-.1-.5a.62 .62 0 0 0-.8-.2 .62 .62 0 0 0-.4 .7l-.1 .1h-3.1l-3.4-3.4-1-.1-.2-.6-1.5-.1-.1-.1z"/>
<circle cx="117.3" cy="145" r="2.85"/>
<circle cx="117.3" cy="65" r="2.85"/>
<circle cx="203" cy="67.6" r="2.85"/>
<circle cx="203" cy="141.2" r="2.85"/>
<circle cx="124.9" cy="143.8" r=".85"/>
<circle cx="122.4" cy="141.2" r=".85"/>
<circle cx="124.9" cy="141.2" r=".85"/>
<circle cx="122.4" cy="138.7" r=".85"/>
<circle cx="124.9" cy="138.7" r=".85"/>
<circle cx="122.4" cy="136.1" r=".85"/>
<circle cx="124.9" cy="136.1" r=".85"/>
<circle cx="122.4" cy="133.6" r=".85"/>
<circle cx="124.9" cy="133.6" r=".85"/>
<circle cx="122.4" cy="131.1" r=".85"/>
<circle cx="124.9" cy="131.1" r=".85"/>
<circle cx="122.4" cy="128.5" r=".85"/>
<circle cx="124.9" cy="128.5" r=".85"/>
<circle cx="122.4" cy="126" r=".85"/>
<circle cx="124.9" cy="126" r=".85"/>
<circle cx="122.4" cy="123.4" r=".85"/>
<circle cx="124.9" cy="123.4" r=".85"/>
<circle cx="122.4" cy="120.9" r=".85"/>
<circle cx="124.9" cy="120.9" r=".85"/>
<circle cx="122.4" cy="118.4" r=".85"/>
<circle cx="124.9" cy="118.4" r=".85"/>
<circle cx="122.4" cy="115.8" r=".85"/>
<circle cx="124.9" cy="115.8" r=".85"/>
<circle cx="122.4" cy="113.3" r=".85"/>
<circle cx="124.9" cy="113.3" r=".85"/>
<circle cx="122.4" cy="110.7" r=".85"/>
<circle cx="124.9" cy="110.7" r=".85"/>
<circle cx="122.4" cy="108.2" r=".85"/>
<circle cx="124.9" cy="108.2" r=".85"/>
<circle cx="122.4" cy="105.7" r=".85"/>
<circle cx="124.9" cy="105.7" r=".85"/>
<circle cx="122.4" cy="103.1" r=".85"/>
<circle cx="124.9" cy="103.1" r=".85"/>
<circle cx="122.4" cy="100.6" r=".85"/>
<circle cx="124.9" cy="100.6" r=".85"/>
<circle cx="122.4" cy="98" r=".85"/>
<circle cx="124.9" cy="98" r=".85"/>
<circle cx="122.4" cy="95.5" r=".85"/>
<circle cx="124.9" cy="95.5" r=".85"/>
<circle cx="122.4" cy="93" r=".85"/>
<circle cx="124.9" cy="93" r=".85"/>
<circle cx="122.4" cy="90.4" r=".85"/>
<circle cx="124.9" cy="90.4" r=".85"/>
<circle cx="122.4" cy="87.9" r=".85"/>
<circle cx="124.9" cy="87.9" r=".85"/>
<circle cx="122.4" cy="85.3" r=".85"/>
<circle cx="124.9" cy="85.3" r=".85"/>
<circle cx="122.4" cy="82.8" r=".85"/>
<circle cx="124.9" cy="82.8" r=".85"/>
<circle cx="122.4" cy="80.3" r=".85"/>
<circle cx="124.9" cy="80.3" r=".85"/>
<circle cx="122.4" cy="77.7" r=".85"/>
<circle cx="124.9" cy="77.7" r=".85"/>
<circle cx="122.4" cy="75.2" r=".85"/>
<circle cx="124.9" cy="75.2" r=".85"/>
<circle cx="122.4" cy="72.6" r=".85"/>
<circle cx="124.9" cy="72.6" r=".85"/>
<circle cx="122.4" cy="70.1" r=".85"/>
<circle cx="124.9" cy="70.1" r=".85"/>
<circle cx="122.4" cy="67.6" r=".85"/>
<circle cx="124.9" cy="67.6" r=".85"/>
<circle cx="122.4" cy="65" r=".85"/>
<circle cx="124.9" cy="65" r=".85"/>
<circle cx="202.4" cy="87.9" r=".85"/>
<circle cx="202.4" cy="85.3" r=".85"/>
<circle cx="185.6" cy="85.7" r="2.2"/>
<circle cx="185.6" cy="67.3" r="2.2"/>
<circle cx="130.9" cy="67.3" r="2.2"/>
<circle cx="130.9" cy="85.7" r="2.2"/>
<circle cx="185.6" cy="72.6" r=".5"/>
<circle cx="185.6" cy="73.9" r=".5"/>
<circle cx="185.6" cy="75.2" r=".5"/>
<circle cx="185.6" cy="76.4" r=".5"/>
<circle cx="185.6" cy="77.7" r=".5"/>
<circle cx="185.6" cy="79" r=".5"/>
<circle cx="202.4" cy="117.8" r=".5"/>
<circle cx="202.4" cy="116.6" r=".5"/>
<circle cx="202.4" cy="115.3" r=".5"/>
<circle cx="130.9" cy="141.2" r="2.2"/>
<circle cx="202.4" cy="108.3" r=".85"/>
<circle cx="202.4" cy="105.8" r=".85"/>
<circle cx="202.4" cy="98.2" r=".85"/>
<circle cx="202.4" cy="95.6" r=".85"/>
<circle cx="202.4" cy="124.1" r=".5"/>
<circle cx="202.4" cy="122.8" r=".5"/>
<circle cx="175.7" cy="67.8" r=".3"/>
<circle cx="158.6" cy="131.4" r=".3"/>
<circle cx="160" cy="106.5" r=".3"/>
<circle cx="163.5" cy="82" r=".3"/>
<circle cx="154.9" cy="136.8" r=".3"/>
<circle cx="202.4" cy="121" r=".3"/>
<circle cx="155.8" cy="116.8" r=".3"/>
<circle cx="145.7" cy="134.7" r=".3"/>
<circle cx="134.3" cy="139.9" r=".3"/>
<circle cx="201.2" cy="71.2" r=".3"/>
<circle cx="142.4" cy="104.8" r=".3"/>
<circle cx="187.3" cy="137.4" r=".3"/>
<circle cx="175.2" cy="144.4" r=".3"/>
<circle cx="177.7" cy="118.9" r=".3"/>
<circle cx="150.2" cy="87.6" r=".3"/>
<circle cx="148" cy="81.8" r=".3"/>
<circle cx="196.7" cy="140.6" r=".3"/>
<circle cx="136.7" cy="139.6" r=".3"/>
<circle cx="143" cy="106" r=".3"/>
<circle cx="187.1" cy="114.2" r=".3"/>
<circle cx="138" cy="82.4" r=".3"/>
<circle cx="136.7" cy="66.5" r=".3"/>
<circle cx="133.8" cy="136.9" r=".3"/>
<circle cx="184.1" cy="97.8" r=".3"/>
<circle cx="156.9" cy="112" r=".3"/>
<circle cx="144" cy="119.1" r=".3"/>
<circle cx="162" cy="135.4" r=".3"/>
<circle cx="135.5" cy="87.6" r=".3"/>
<circle cx="172.2" cy="106.3" r=".3"/>
<circle cx="158.1" cy="122.2" r=".3"/>
<circle cx="165.2" cy="113.8" r=".3"/>
<circle cx="149.7" cy="94.2" r=".3"/>
<circle cx="198.8" cy="66.3" r=".3"/>
<circle cx="148.2" cy="121.2" r=".3"/>
<circle cx="178.6" cy="136.8" r=".3"/>
<circle cx="144.3" cy="122.3" r=".3"/>
<circle cx="130.5" cy="117.9" r=".3"/>
<circle cx="181.2" cy="113.3" r=".3"/>
<circle cx="181.3" cy="108.7" r=".3"/>
<circle cx="187.3" cy="102.6" r=".3"/>
<circle cx="155.5" cy="78.4" r=".3"/>
<circle cx="194.4" cy="109.8" r=".3"/>
<circle cx="130.9" cy="97.9" r=".3"/>
<circle cx="200.4" cy="107.8" r=".3"/>
<circle cx="190.3" cy="95" r=".3"/>
<circle cx="138.6" cy="99.3" r=".3"/>
<circle cx="194.5" cy="115.9" r=".3"/>
<circle cx="135.2" cy="69.8" r=".3"/>
<circle cx="185.5" cy="105.4" r=".3"/>
<circle cx="196.2" cy="118" r=".3"/>
<circle cx="119.1" cy="75.2" r=".3"/>
<circle cx="194.5" cy="107.9" r=".3"/>
<circle cx="155.7" cy="121.2" r=".3"/>
<circle cx="171.7" cy="82.8" r=".3"/>
<circle cx="144.7" cy="73.4" r=".3"/>
<circle cx="149.9" cy="96" r=".3"/>
<circle cx="137.5" cy="126.1" r=".3"/>
<circle cx="151.6" cy="139.4" r=".3"/>
<circle cx="146" cy="127.9" r=".3"/>
<circle cx="127.8" cy="137.7" r=".3"/>
<circle cx="170.9" cy="68.7" r=".3"/>
<circle cx="134.7" cy="82.7" r=".3"/>
<circle cx="172.2" cy="104.6" r=".3"/>
<circle cx="160" cy="121" r=".3"/>
<circle cx="128.1" cy="106" r=".3"/>
<circle cx="136.2" cy="110.7" r=".3"/>
<circle cx="146.9" cy="76.1" r=".3"/>
<circle cx="190.7" cy="111.2" r=".3"/>
<circle cx="177.4" cy="75.8" r=".3"/>
<circle cx="197.9" cy="103.6" r=".3"/>
<circle cx="149.4" cy="142.5" r=".3"/>
<circle cx="149.2" cy="116.8" r=".3"/>
<circle cx="193.8" cy="126.7" r=".3"/>
<circle cx="141.6" cy="129.2" r=".3"/>
<circle cx="175.1" cy="131.3" r=".3"/>
<circle cx="128.5" cy="117.9" r=".3"/>
<circle cx="179.8" cy="76.7" r=".3"/>
<circle cx="194.5" cy="120.3" r=".3"/>
<circle cx="138.1" cy="108.6" r=".3"/>
<circle cx="137" cy="128.6" r=".3"/>
<circle cx="167.3" cy="87.2" r=".3"/>
<circle cx="148.3" cy="132.6" r=".3"/>
<circle cx="189.9" cy="117.6" r=".3"/>
<circle cx="171.4" cy="78.7" r=".3"/>
<circle cx="152.7" cy="134.2" r=".3"/>
<circle cx="167.6" cy="84.4" r=".3"/>
<circle cx="171.5" cy="73.1" r=".3"/>
<circle cx="137.7" cy="144.3" r=".3"/>
<circle cx="137.6" cy="92.3" r=".3"/>
<circle cx="183.7" cy="141.3" r=".3"/>
<circle cx="186" cy="143.4" r=".3"/>
<circle cx="159.3" cy="80.1" r=".3"/>
<circle cx="138.1" cy="106.5" r=".3"/>
<circle cx="157.7" cy="104" r=".3"/>
<circle cx="193.4" cy="133.3" r=".3"/>
<circle cx="158.3" cy="116.5" r=".3"/>
<circle cx="150.1" cy="92.5" r=".3"/>
<circle cx="200.5" cy="138.2" r=".3"/>
<circle cx="165.8" cy="124.7" r=".3"/>
<circle cx="175.3" cy="86.7" r=".3"/>
<circle cx="175.8" cy="96" r=".3"/>
<circle cx="197.9" cy="105.9" r=".3"/>
<circle cx="200.9" cy="127" r=".3"/>
<circle cx="144.3" cy="136" r=".3"/>
<circle cx="150.7" cy="101.7" r=".3"/>
<circle cx="144.7" cy="133.2" r=".3"/>
<circle cx="135.5" cy="80.8" r=".3"/>
<circle cx="174.3" cy="85.3" r=".3"/>
<circle cx="140" cy="94.6" r=".3"/>
<circle cx="143.5" cy="107.4" r=".3"/>
<circle cx="198.1" cy="91.2" r=".3"/>
<circle cx="175.6" cy="74.2" r=".3"/>
<circle cx="182.6" cy="82.4" r=".3"/>
<circle cx="132.4" cy="99.9" r=".3"/>
<circle cx="154.6" cy="128.6" r=".3"/>
<circle cx="172" cy="113.9" r=".3"/>
<circle cx="161.7" cy="102.7" r=".3"/>
<circle cx="194.4" cy="99.1" r=".3"/>
<circle cx="160.1" cy="65.5" r=".3"/>
<circle cx="175.5" cy="110" r=".3"/>
<circle cx="149.9" cy="76.1" r=".3"/>
<circle cx="155.5" cy="82.2" r=".3"/>
<circle cx="147.9" cy="72.3" r=".3"/>
<circle cx="196.9" cy="118.9" r=".3"/>
<circle cx="184.9" cy="125.9" r=".3"/>
<circle cx="163.3" cy="138.2" r=".3"/>
<circle cx="176" cy="126.2" r=".3"/>
<circle cx="178.5" cy="106" r=".3"/>
<circle cx="186.5" cy="119" r=".3"/>
<circle cx="130.9" cy="127.4" r=".3"/>
<circle cx="180.8" cy="134.4" r=".3"/>
<circle cx="142.3" cy="136" r=".3"/>
<circle cx="183" cy="143.3" r=".3"/>
<circle cx="192.5" cy="83.2" r=".3"/>
<circle cx="150.8" cy="118" r=".3"/>
<circle cx="156.3" cy="98.2" r=".3"/>
<circle cx="183.8" cy="116.6" r=".3"/>
<circle cx="150.2" cy="84.6" r=".3"/>
<circle cx="144" cy="112.9" r=".3"/>
<circle cx="130.3" cy="90.4" r=".3"/>
<circle cx="129.5" cy="117.9" r=".3"/>
<circle cx="168.9" cy="125.7" r=".3"/>
<circle cx="175.7" cy="94.5" r=".3"/>
<circle cx="118.6" cy="104" r=".3"/>
<circle cx="198.6" cy="109.8" r=".3"/>
<circle cx="198.7" cy="142.1" r=".3"/>
<circle cx="187.4" cy="109.2" r=".3"/>
<circle cx="162.3" cy="118.4" r=".3"/>
<circle cx="181.3" cy="75.4" r=".3"/>
<circle cx="161.6" cy="132.2" r=".3"/>
<circle cx="162.8" cy="99.1" r=".3"/>
<circle cx="156.8" cy="100.1" r=".3"/>
<circle cx="160.9" cy="66.7" r=".3"/>
<circle cx="170.3" cy="80.3" r=".3"/>
<circle cx="163.5" cy="78.4" r=".3"/>
<circle cx="139.4" cy="76.3" r=".3"/>
<circle cx="196.8" cy="104.9" r=".3"/>
<circle cx="136.2" cy="121.2" r=".3"/>
<circle cx="172.2" cy="102.9" r=".3"/>
<circle cx="127.3" cy="97.4" r=".3"/>
<circle cx="158.4" cy="128.9" r=".3"/>
<circle cx="177.5" cy="98.5" r=".3"/>
<circle cx="199.7" cy="144.3" r=".3"/>
<circle cx="184" cy="112.1" r=".3"/>
<circle cx="186" cy="90.5" r=".3"/>
<circle cx="149.9" cy="78.2" r=".3"/>
<circle cx="185" cy="109.2" r=".3"/>
<circle cx="144.6" cy="76.8" r=".3"/>
<circle cx="185.2" cy="102.5" r=".3"/>
<circle cx="169.2" cy="70" r=".3"/>
<circle cx="166.1" cy="105.5" r=".3"/>
<circle cx="119.8" cy="142" r=".3"/>
<circle cx="140.4" cy="89.3" r=".3"/>
<circle cx="157" cy="70.9" r=".3"/>
<circle cx="136.1" cy="143.9" r=".3"/>
<circle cx="157" cy="107.8" r=".3"/>
<circle cx="173.2" cy="86.8" r=".3"/>
<circle cx="202.5" cy="93" r=".3"/>
<circle cx="159.3" cy="144.4" r=".3"/>
<circle cx="152.1" cy="69" r=".3"/>
<circle cx="150.2" cy="141.3" r=".3"/>
<circle cx="154.4" cy="139.6" r=".3"/>
<circle cx="161.9" cy="128.6" r=".3"/>
<circle cx="193.9" cy="93.1" r=".3"/>
<circle cx="194.4" cy="101.7" r=".3"/>
<circle cx="181.7" cy="86.4" r=".3"/>
<circle cx="139.4" cy="78.2" r=".3"/>
<circle cx="177.1" cy="84.4" r=".3"/>
<circle cx="147.9" cy="124.6" r=".3"/>
<circle cx="140.3" cy="81.4" r=".3"/>
<circle cx="168.9" cy="119.5" r=".3"/>
<circle cx="150.7" cy="110" r=".3"/>
<circle cx="137.9" cy="85.3" r=".3"/>
<circle cx="141.3" cy="85.5" r=".3"/>
<circle cx="134.1" cy="119.5" r=".3"/>
<circle cx="158.6" cy="92.3" r=".3"/>
<circle cx="152.2" cy="142.5" r=".3"/>
<circle cx="178.1" cy="143.8" r=".3"/>
<circle cx="134.6" cy="94.7" r=".3"/>
<circle cx="136" cy="142.4" r=".3"/>
<circle cx="143" cy="133.3" r=".3"/>
<circle cx="193.9" cy="91.1" r=".3"/>
<circle cx="198.1" cy="104.8" r=".3"/>
<circle cx="199" cy="95.1" r=".3"/>
<circle cx="148" cy="122.9" r=".3"/>
<circle cx="143.3" cy="91.2" r=".3"/>
<circle cx="134.2" cy="89.3" r=".3"/>
<circle cx="181.8" cy="137.7" r=".3"/>
<circle cx="175.8" cy="117.7" r=".3"/>
<circle cx="180.4" cy="106.8" r=".3"/>
<circle cx="139.8" cy="65.7" r=".4"/>
<circle cx="166.1" cy="104" r=".3"/>
<circle cx="127.7" cy="129.2" r=".3"/>
<circle cx="163.5" cy="135.9" r=".3"/>
<circle cx="144.1" cy="111.6" r=".4"/>
<circle cx="156.4" cy="143.4" r=".4"/>
<circle cx="143.6" cy="75.6" r=".3"/>
<circle cx="140" cy="102" r=".4"/>
<circle cx="153.5" cy="71" r=".4"/>
<circle cx="146.6" cy="80.3" r=".3"/>
<circle cx="147.4" cy="135.1" r=".3"/>
<circle cx="201.8" cy="113.9" r=".3"/>
<circle cx="173.3" cy="114.4" r=".3"/>
<circle cx="133.4" cy="127.5" r=".3"/>
<circle cx="140.2" cy="117" r=".4"/>
<circle cx="192.6" cy="144.6" r=".4"/>
<circle cx="162.3" cy="119.5" r=".3"/>
<circle cx="143" cy="131.4" r=".3"/>
<circle cx="133" cy="107.8" r=".3"/>
<circle cx="165.9" cy="74.3" r=".3"/>
<circle cx="164.8" cy="96.4" r=".3"/>
<circle cx="144.3" cy="95.6" r=".4"/>
<circle cx="134.2" cy="90.4" r=".3"/>
<circle cx="133.4" cy="128.4" r=".3"/>
<circle cx="191.5" cy="78" r=".3"/>
<circle cx="146" cy="73.3" r=".3"/>
<circle cx="138" cy="133.8" r=".3"/>
<circle cx="137.9" cy="97.2" r=".4"/>
<circle cx="133.4" cy="129.3" r=".3"/>
<circle cx="147.4" cy="74.5" r=".3"/>
<circle cx="165.6" cy="76.3" r=".3"/>
<circle cx="180.7" cy="84.3" r=".3"/>
<circle cx="140.5" cy="143.3" r=".4"/>
<circle cx="170.4" cy="109.8" r=".3"/>
<circle cx="172.5" cy="68.7" r=".4"/>
<circle cx="179.9" cy="126.7" r=".3"/>
<circle cx="171.5" cy="143.5" r=".4"/>
<circle cx="195.3" cy="79.8" r=".3"/>
<circle cx="187.8" cy="141.1" r=".4"/>
<circle cx="196.7" cy="112.3" r=".4"/>
<circle cx="197.1" cy="96.9" r=".4"/>
<circle cx="199.5" cy="115.1" r=".3"/>
<circle cx="182.7" cy="79" r=".3"/>
<circle cx="195.5" cy="114.3" r=".3"/>
<circle cx="173.2" cy="82.7" r=".3"/>
<circle cx="171.7" cy="71.9" r=".3"/>
<circle cx="169.7" cy="139.2" r=".3"/>
<circle cx="172.9" cy="81.3" r=".3"/>
<circle cx="182.7" cy="77.3" r=".3"/>
<circle cx="161.1" cy="73.1" r=".3"/>
<circle cx="144" cy="71.1" r=".3"/>
<circle cx="171" cy="85.7" r=".3"/>
<circle cx="165.8" cy="125.9" r=".3"/>
<circle cx="146.9" cy="85.6" r=".3"/>
<circle cx="165.9" cy="73.5" r=".3"/>
<circle cx="139.8" cy="71.7" r=".3"/>
<circle cx="158.8" cy="71.6" r=".3"/>
<circle cx="143.8" cy="85.3" r=".3"/>
<circle cx="139.3" cy="75.4" r=".3"/>
<circle cx="151.4" cy="70.2" r=".3"/>
<circle cx="158.1" cy="71.1" r=".3"/>
<circle cx="140.6" cy="71.7" r=".3"/>
<circle cx="159.6" cy="72.1" r=".3"/>
<circle cx="177.5" cy="115.6" r=".3"/>
<circle cx="176" cy="113.9" r=".3"/>
<circle cx="177.4" cy="100.6" r=".3"/>
<circle cx="176" cy="102.5" r=".3"/>
<circle cx="163.9" cy="97.8" r=".3"/>
<circle cx="161.6" cy="108.7" r=".3"/>
<circle cx="188.5" cy="121.7" r=".3"/>
<circle cx="188.5" cy="119.6" r=".3"/>
<circle cx="185" cy="122" r=".3"/>
<circle cx="175.6" cy="114.8" r=".3"/>
<circle cx="162.6" cy="114.2" r=".3"/>
<circle cx="140.7" cy="122.2" r=".3"/>
<circle cx="164.2" cy="112.4" r=".3"/>
<circle cx="196.4" cy="85.3" r=".3"/>
<circle cx="158.2" cy="74.9" r=".3"/>
<circle cx="196.5" cy="86.2" r=".3"/>
<circle cx="159.7" cy="75.5" r=".3"/>
<circle cx="171.4" cy="98" r=".3"/>
<circle cx="173.3" cy="109.5" r=".3"/>
<circle cx="174" cy="108.6" r=".3"/>
<circle cx="170.4" cy="81.3" r=".3"/>
<circle cx="174.6" cy="107.8" r=".3"/>
<circle cx="169.6" cy="98.2" r=".3"/>
<circle cx="168" cy="111.2" r=".3"/>
<circle cx="160.4" cy="72.6" r=".3"/>
<circle cx="142.4" cy="75.6" r=".3"/>
<circle cx="165.9" cy="72.6" r=".3"/>
<circle cx="188.9" cy="77.2" r=".3"/>
<circle cx="187.9" cy="79" r=".3"/>
<circle cx="169.9" cy="138.3" r=".3"/>
<circle cx="157.2" cy="136.9" r=".3"/>
<circle cx="141.3" cy="132.7" r=".3"/>
<circle cx="132" cy="133.7" r=".3"/>
<circle cx="158.5" cy="138.2" r=".3"/>
<circle cx="139.8" cy="128.3" r=".3"/>
<circle cx="138" cy="127.9" r=".3"/>
<circle cx="159.7" cy="139.4" r=".3"/>
<circle cx="139.5" cy="127.5" r=".3"/>
<circle cx="130.6" cy="137.7" r=".3"/>
<circle cx="159.1" cy="138.8" r=".3"/>
<circle cx="156.3" cy="136.1" r=".3"/>
<circle cx="175" cy="116.1" r=".3"/>
<circle cx="181.2" cy="95.5" r=".3"/>
<circle cx="169.4" cy="112.1" r=".3"/>
<circle cx="192.2" cy="121.6" r=".3"/>
<circle cx="194.9" cy="122.8" r=".3"/>
<circle cx="175.7" cy="119.9" r=".3"/>
<circle cx="162" cy="116.5" r=".3"/>
<circle cx="166.7" cy="106.8" r=".3"/>
<circle cx="171.6" cy="86.7" r=".3"/>
<circle cx="173.7" cy="115.4" r=".3"/>
<circle cx="141.9" cy="89.4" r=".3"/>
<circle cx="162.5" cy="92.7" r=".3"/>
<circle cx="138.9" cy="89.9" r=".3"/>
<circle cx="163.1" cy="92.3" r=".3"/>
<circle cx="157.6" cy="88.8" r=".3"/>
<circle cx="164.9" cy="114.8" r=".3"/>
<circle cx="151.5" cy="91.9" r=".3"/>
<circle cx="200.8" cy="100.3" r=".3"/>
<circle cx="156.5" cy="139.4" r=".3"/>
<circle cx="155.8" cy="139.7" r=".3"/>
<circle cx="140.7" cy="128.6" r=".3"/>
<circle cx="157.8" cy="137.5" r=".3"/>
<circle cx="167.8" cy="130.4" r=".3"/>
<circle cx="168.7" cy="104.4" r=".3"/>
<circle cx="173.4" cy="119.7" r=".3"/>
<circle cx="168.8" cy="128.1" r=".3"/>
<circle cx="173.5" cy="118.9" r=".3"/>
<circle cx="168.9" cy="128.9" r=".3"/>
<circle cx="169" cy="129.7" r=".3"/>
<circle cx="173.7" cy="118.1" r=".3"/>
<circle cx="139.9" cy="85.5" r=".3"/>
<circle cx="132.7" cy="90.3" r=".3"/>
<circle cx="144.1" cy="134.7" r=".3"/>
<circle cx="131.4" cy="129.9" r=".3"/>
<circle cx="145.6" cy="80" r=".3"/>
<circle cx="134.8" cy="117.7" r=".3"/>
</g>
<g fill="none" stroke="#b3ffb3" stroke-width=".25">
<path d="M117.3 65l.6 .7v3.6M182.7 79l-.6-.6v-4.5l-3.5-3.4-2 2h-9l-3.4-3.4h-2.1v3.9l-.7 .8h-11l-4.3-4.3-1.5 1.5v1l-7.5 7.5v11.1l7.2 7.2v10.9l-2.1 2.1M182.7 77.3v-7.6l-1.6-1.6h-2.6l-2.4 2.4-3.3-3.3h-11.3l-1.9 1.9-1.9-1.9h-11.8l-2.3 2.3v.2l-5.9 5.8v2.1l-1.1 1.1v14l4.8 4.8h.8v.7l-3.1 3v9l3.1 3.1M188.9 77.2l-1 1v.8M138.5 87.2l.4 .4v2.3M141 87.2v1.3l.9 .9M143.6 87.2v1.6l1.6 1.6v35.2l3.4 3.3h1.4M146.1 87.2v38.1l2.9 2.8h1M154.5 86.9v1.5l-3 3v.5M157 86.9v1.4l.6 .5M159.6 86.9v1.4l-9.6 9.6v29.4M160 95.7h-1.5l-1.5 1.5v1.6l-2.9 3v23.8"/>
<path d="M160 98.2h-1.5l-.4 .5v2.1l-3.2 3.2v21.6M162.1 86.9v2l-.9 .9h-1l-8.5 8.5v27.3M162.5 92.7l6.9 6.9v2.9M163.1 92.3v.2l6.9 6.9v3.1M171.6 86.7h-.3l-.3 .3v1.3M172.9 81.3h2.8l8.7 8.6h3.6l11.5 11.5v10.2l-2.3 2.3 2.3 2.4v17.2l-8.8 8.7v.7l-1.6 1.6h-3.5l-.6-.6v-1l.5-.5v-13l-5.6-5.6h-6.2l-2.4 2.5v3l-3.6 3.6h-2.3M173.2 82.7l.9-.9h1.5l18.2 18.1h1.7l1.6 1.7-1.6 1.6v11.6l3.3 3.4v15l-8.1 8.1h-.9l-1.6 1.6-2.2-2.1v-11.5l-5.9-6h-6.7l-2.8 2.8v2.9l-3.1 3.1h-2.1M173.6 88.3v8l2.7 2.7v2l.4 .5v9l-1.7 1.8h-3.1l-2.5-2.6v-1.4M176.1 88.3v-2.8l-1-1.1h-6l-1.1 1.1h-.2l-14.5 14.5v25.6M178.6 88.3v-1.2l-3.1-3.2h-6.5l-1.2 1.1h-.7l-14.6 14.7v25.9M179.3 99.1h-1l-.3 .2v4.6l1.4 1.4h.8l2 2v12.2l-2 2h-17.7l-2.8 2.8v1.3M179.3 96.5h-1.7l-.9 .9v3.4l.5 .5v9.4l-1.9 2h-3.6l-3-3v-1.4"/>
<path d="M179.3 94h1.4l.5 .5v1M200.2 99.6v.2l.6 .5M202.4 95.6l-2.2 2.2v.7M129.2 110.9v3.7l4.1 4.1h4.2l1.1 1.2M130.7 103.8l-.3 .3M130.7 100.1l-.7-.8h-1.7l-1 1.1v12.7l-1.4 1.4h-2.3l-1.2-1.2M131.9 119.5l-.3 .4M132.2 101.7h.2M132.9 119.5l.4 .4M133 105.9v1.9l-1.3 1.2v3.6l-.2 .1M133 110.9v4.7l1.8 1.9v.2M133 102.6l.7-.7v-2.1l-.9-.9h-4.7l-1.3 1.3v11.2l-1.9 1.9"/>
<path d="M135.2 119.5h1.8l.4 .4M160 103.3h1.1l1.4 1.3v8.6l-.6 .6v1.3l1.7 1.7h2.7M160 100.7l.2-.2h7.1l.8 .7v1.3M160 110.8h1.2l.2 .2v3.3l-.3 .2h-2.1l-1.7 1.8v9.3M160 113.3h-1.6l-1.9 1.9v10.4M160 115.9h1.4l.6 .6M164.4 115.5h1.9M164.5 119.4h-2.1l-.1 .1M164.9 114.9h1.4M165.2 118.8h1.1M165.5 108.3v2.9l2.1 2.1h.5l1.5 1.4v3.9l.8 .8h2.7l.3 .3M166.1 108.3v2.9l1.7 1.6h.5l1.7 1.7v3.7l.5 .6h2.9l.1 .1"/>
<path d="M166.3 117.5h-4l-1 .9h-1.3M166.3 118.1h-2l-.3 .3M166.3 116.2h1.1l.4 .4M166.8 102.5v1.7l-.5 .4h-2M166.8 108.3v2.9l1.2 1.2h.5l2 1.9v3.5M167.4 108.3v1.4l1.3 1.3v.5l.7 .6M167.4 102.5v3.6l-.7 .7M168.1 108.3v1.4l3.4 3.5h4.1l1.7-1.8h2.1M168.7 102.5v1.9M170 108.3v1.1l.4 .4M170.8 118.1h2.9M172 117.5h2.2l.7 .7v.9l.8 .8"/>
<path d="M173.3 114.4l-.4 .5h-.9M173.7 115.4l-.1 .1h-1.6M173.7 118.1h.1M175 116.1l-.1 .1h-2.9M179.3 101.6h1.4l2.4 2.4v15.2l-2.8 2.8h-17.6l-2.2 2.2v1.4M179.4 108.9h.9l1 .9v1.8l-.9 1h-2.3l-1 1v1.2l-2 2h-3.1M179.4 116.5h1l.7 .6v2.3l-1.3 1.2h-17.7l-4 4v1M179.4 113.9h1.4l.7 .7v5l-1.5 1.5h-17.7l-3.4 3.4v1.1M201.8 103.5v.1l-.7 .7M202.4 100.7v1.1l-.6 .7M129.2 131.8h-1.2M130.5 131.8v1.7"/>
<path d="M130.5 135.7v1.8l.1 .2M131.6 121.3l.8 .9h3.9M131.8 131.8v1.7l.2 .2M133.3 123.2h2.7M135.8 130.5v4.1l9.4 9.4h9.9l.2 .1h1.4l.6-.6v-2.5M136.5 123.7v1.1M136.5 130.5v4.1l8.9 9h9.8l1.3-1.3v-1.3M137.1 123v1.8M137.1 130.5v4.2l8.5 8.4h9l1.1-1.1v-1M137.4 120.9v.6l1.7 1.8h1.2l.7 .8v.7M137.8 128.1v2.4M138 133.8v.1"/>
<path d="M138 133.9h1.3M138.6 120.9v1.1l.7 .7h1l1.4 1.4v.7M138.9 127h-1.8l-1.9 1.9v5.7l9.8 9.9h10l.1 .1h1.8l1.2-1.2v-2.4M139.1 127.9v2.6M139.7 124.8v1.3M139.8 128.3l-.1 2.2M140.3 132.7h1.2M140.7 128.6l-.3 .3v1.6M141 130.5v1M141.3 132.7l.1 .1v1M144.1 134.7l2.3 2.4h3.5l.1-.2M145.4 130.2h1.1"/>
<path d="M147 129.7h3M147.4 135.1v1.1M147.4 139.3h2.6M147.9 139.8v1M155.8 139.7l-.9-.9h-.6l-1 1v1.2M156.3 136.1h3.9l.8 .8h6.4M156.5 139.4l-1-1h-1.4l-1.6 1.5v1.1M157.2 136.9h3.1l2.5 2.4h2.6M157.8 137.5h2.6l1.7 1.8v1.7M158.5 138.2h1.9l.9 .9v1.9M159.1 138.8h1l.4 .4v1.8M159.7 139.4v2.6l2.6 2.7h6.9l2.3-2.3h5.9"/>
<path d="M160.5 136.4h.1M163.5 135.9l.3 .2h3.5M165.4 138.5l1.7 .1M165.4 137.7h3.9l.6 .6M165.4 133.7h2.4M165.4 134.5h2.6M165.4 131.3h1.5M165.4 130.5h1.4M165.8 125.9l-.4 .4v1M167.5 136h1.1M168.1 138.6h1l.6 .6M168.4 134.2h3.5l.2 .2v.9"/>
<path d="M168.4 133.1h1.8M168.8 128.1h-3.4M168.9 128.9h-3.5M169 129.7h-3.6M170.8 131.4l-.4 .4M171.8 131.4l.3 .4M172.2 139.2h1.5M176 132.7h-1.3l-.8 .8v5.4M176 134h-1.2l-.4 .4v6.6M176 135.2h1.6M177.6 129.7v1.9M180.3 122.9h-17.3l-.9 .9v1.8"/>
<path d="M180.5 122.4h-17.7l-1.5 1.6v1.6M180.6 123.1h6.9l.7 .7v1.4M180.7 122.7h9.1l.9 .9v1.6M183 134h1.1l.4-.4v-.5l-.4-.4h-5.3v1.4M183 135.2h1.2l.4 .4v2.3l-3.8 3.8h-.7M183 136.5h-1.9l-1 1v1.7M192.2 121.6l1 1v2.6M194.9 122.8l.9 .9v1.5M194.9 122.8h.1M117.9 140.7v3.7l-.6 .6M163.7 141.9l.7 .7M165.4 142.6h1.7"/>
<path d="M167.1 142.6h.1M173.3 140.2h-1.5l-3.2 3.1h-5l-.7-.7v-1.6M174.2 141.2h-2.8l-2.6 2.6h-6.1l-1.4-1.4M177.8 142.7h1.1M178.9 140.2l-1.5 1.5h-5.9l-2.5 2.5h-6.5l-2-2"/>
</g>
<path d="M178.9 141.7h1.1" fill="none" stroke="#b3ffb3" stroke-width=".2"/>
<path d="M139.8 65.7l1.2 1.2v2.6M157 69.1l-.6 .6v.8l-.5 .5h-2.4M172.5 68.7l1.1 1v.8M133 105.9h1.6M142.2 100.7h-1.4l-.8 .8v.5M142.2 115.9h-1.5l-.5 .5v.6M141.7 130.5l1.3-.1v1M179.9 126.7l-.3 .3v3.2M193.2 142.9l-.6 .7v1" fill="none" stroke="#b3ffb3" stroke-width=".35"/>
<g fill="#fff" stroke="#fff" stroke-width=".14">
<circle cx="175.7" cy="67.8" r=".15"/>
<circle cx="158.6" cy="131.4" r=".15"/>
<circle cx="160" cy="106.5" r=".15"/>
<circle cx="163.5" cy="82" r=".15"/>
<circle cx="154.9" cy="136.8" r=".15"/>
<circle cx="202.4" cy="121" r=".15"/>
<circle cx="155.8" cy="116.8" r=".15"/>
<circle cx="145.7" cy="134.7" r=".15"/>
<circle cx="134.3" cy="139.9" r=".15"/>
<circle cx="201.2" cy="71.2" r=".15"/>
<circle cx="142.4" cy="104.8" r=".15"/>
<circle cx="187.3" cy="137.4" r=".15"/>
<circle cx="175.2" cy="144.4" r=".15"/>
<circle cx="177.7" cy="118.9" r=".15"/>
<circle cx="150.2" cy="87.6" r=".15"/>
<circle cx="148" cy="81.8" r=".15"/>
<circle cx="196.7" cy="140.6" r=".15"/>
<circle cx="136.7" cy="139.6" r=".15"/>
<circle cx="143" cy="106" r=".15"/>
<circle cx="187.1" cy="114.2" r=".15"/>
<circle cx="138" cy="82.4" r=".15"/>
<circle cx="136.7" cy="66.5" r=".15"/>
<circle cx="133.8" cy="136.9" r=".15"/>
<circle cx="184.1" cy="97.8" r=".15"/>
<circle cx="156.9" cy="112" r=".15"/>
<circle cx="144" cy="119.1" r=".15"/>
<circle cx="162" cy="135.4" r=".15"/>
<circle cx="135.5" cy="87.6" r=".15"/>
<circle cx="158.1" cy="122.2" r=".15"/>
<circle cx="165.2" cy="113.8" r=".15"/>
<circle cx="149.7" cy="94.2" r=".15"/>
<circle cx="198.8" cy="66.3" r=".15"/>
<circle cx="148.2" cy="121.2" r=".15"/>
<circle cx="178.6" cy="136.8" r=".15"/>
<circle cx="144.3" cy="122.3" r=".15"/>
<circle cx="130.5" cy="117.9" r=".15"/>
<circle cx="181.2" cy="113.3" r=".15"/>
<circle cx="181.3" cy="108.7" r=".15"/>
<circle cx="187.3" cy="102.6" r=".15"/>
<circle cx="155.5" cy="78.4" r=".15"/>
<circle cx="194.4" cy="109.8" r=".15"/>
<circle cx="130.9" cy="97.9" r=".15"/>
<circle cx="200.4" cy="107.8" r=".15"/>
<circle cx="190.3" cy="95" r=".15"/>
<circle cx="138.6" cy="99.3" r=".15"/>
<circle cx="194.5" cy="115.9" r=".15"/>
<circle cx="135.2" cy="69.8" r=".15"/>
<circle cx="185.5" cy="105.4" r=".15"/>
<circle cx="196.2" cy="118" r=".15"/>
<circle cx="119.1" cy="75.2" r=".15"/>
<circle cx="194.5" cy="107.9" r=".15"/>
<circle cx="155.7" cy="121.2" r=".15"/>
<circle cx="171.7" cy="82.8" r=".15"/>
<circle cx="144.7" cy="73.4" r=".15"/>
<circle cx="149.9" cy="96" r=".15"/>
<circle cx="137.5" cy="126.1" r=".15"/>
<circle cx="151.6" cy="139.4" r=".15"/>
<circle cx="146" cy="127.9" r=".15"/>
<circle cx="127.8" cy="137.7" r=".15"/>
<circle cx="170.9" cy="68.7" r=".15"/>
<circle cx="134.7" cy="82.7" r=".15"/>
<circle cx="160" cy="121" r=".15"/>
<circle cx="128.1" cy="106" r=".15"/>
<circle cx="136.2" cy="110.7" r=".15"/>
<circle cx="146.9" cy="76.1" r=".15"/>
<circle cx="190.7" cy="111.2" r=".15"/>
<circle cx="177.4" cy="75.8" r=".15"/>
<circle cx="197.9" cy="103.6" r=".15"/>
<circle cx="149.4" cy="142.5" r=".15"/>
<circle cx="149.2" cy="116.8" r=".15"/>
<circle cx="193.8" cy="126.7" r=".15"/>
<circle cx="141.6" cy="129.2" r=".15"/>
<circle cx="175.1" cy="131.3" r=".15"/>
<circle cx="128.5" cy="117.9" r=".15"/>
<circle cx="179.8" cy="76.7" r=".15"/>
<circle cx="194.5" cy="120.3" r=".15"/>
<circle cx="138.1" cy="108.6" r=".15"/>
<circle cx="137" cy="128.6" r=".15"/>
<circle cx="167.3" cy="87.2" r=".15"/>
<circle cx="148.3" cy="132.6" r=".15"/>
<circle cx="189.9" cy="117.6" r=".15"/>
<circle cx="171.4" cy="78.7" r=".15"/>
<circle cx="152.7" cy="134.2" r=".15"/>
<circle cx="167.6" cy="84.4" r=".15"/>
<circle cx="171.5" cy="73.1" r=".15"/>
<circle cx="137.7" cy="144.3" r=".15"/>
<circle cx="137.6" cy="92.3" r=".15"/>
<circle cx="183.7" cy="141.3" r=".15"/>
<circle cx="186" cy="143.4" r=".15"/>
<circle cx="159.3" cy="80.1" r=".15"/>
<circle cx="138.1" cy="106.5" r=".15"/>
<circle cx="157.7" cy="104" r=".15"/>
<circle cx="193.4" cy="133.3" r=".15"/>
<circle cx="158.3" cy="116.5" r=".15"/>
<circle cx="150.1" cy="92.5" r=".15"/>
<circle cx="200.5" cy="138.2" r=".15"/>
<circle cx="165.8" cy="124.7" r=".15"/>
<circle cx="175.3" cy="86.7" r=".15"/>
<circle cx="175.8" cy="96" r=".15"/>
<circle cx="197.9" cy="105.9" r=".15"/>
<circle cx="200.9" cy="127" r=".15"/>
<circle cx="144.3" cy="136" r=".15"/>
<circle cx="150.7" cy="101.7" r=".15"/>
<circle cx="144.7" cy="133.2" r=".15"/>
<circle cx="135.5" cy="80.8" r=".15"/>
<circle cx="174.3" cy="85.3" r=".15"/>
<circle cx="140" cy="94.6" r=".15"/>
<circle cx="143.5" cy="107.4" r=".15"/>
<circle cx="198.1" cy="91.2" r=".15"/>
<circle cx="175.6" cy="74.2" r=".15"/>
<circle cx="182.6" cy="82.4" r=".15"/>
<circle cx="154.6" cy="128.6" r=".15"/>
<circle cx="172" cy="113.9" r=".15"/>
<circle cx="161.7" cy="102.7" r=".15"/>
<circle cx="194.4" cy="99.1" r=".15"/>
<circle cx="160.1" cy="65.5" r=".15"/>
<circle cx="175.5" cy="110" r=".15"/>
<circle cx="149.9" cy="76.1" r=".15"/>
<circle cx="155.5" cy="82.2" r=".15"/>
<circle cx="147.9" cy="72.3" r=".15"/>
<circle cx="196.9" cy="118.9" r=".15"/>
<circle cx="184.9" cy="125.9" r=".15"/>
<circle cx="163.3" cy="138.2" r=".15"/>
<circle cx="176" cy="126.2" r=".15"/>
<circle cx="178.5" cy="106" r=".15"/>
<circle cx="186.5" cy="119" r=".15"/>
<circle cx="130.9" cy="127.4" r=".15"/>
<circle cx="183" cy="143.3" r=".15"/>
<circle cx="192.5" cy="83.2" r=".15"/>
<circle cx="150.8" cy="118" r=".15"/>
<circle cx="156.3" cy="98.2" r=".15"/>
<circle cx="183.8" cy="116.6" r=".15"/>
<circle cx="150.2" cy="84.6" r=".15"/>
<circle cx="144" cy="112.9" r=".15"/>
<circle cx="130.3" cy="90.4" r=".15"/>
<circle cx="129.5" cy="117.9" r=".15"/>
<circle cx="168.9" cy="125.7" r=".15"/>
<circle cx="175.7" cy="94.5" r=".15"/>
<circle cx="118.6" cy="104" r=".15"/>
<circle cx="198.6" cy="109.8" r=".15"/>
<circle cx="198.7" cy="142.1" r=".15"/>
<circle cx="187.4" cy="109.2" r=".15"/>
<circle cx="162.3" cy="118.4" r=".15"/>
<circle cx="181.3" cy="75.4" r=".15"/>
<circle cx="161.6" cy="132.2" r=".15"/>
<circle cx="162.8" cy="99.1" r=".15"/>
<circle cx="156.8" cy="100.1" r=".15"/>
<circle cx="160.9" cy="66.7" r=".15"/>
<circle cx="170.3" cy="80.3" r=".15"/>
<circle cx="163.5" cy="78.4" r=".15"/>
<circle cx="139.4" cy="76.3" r=".15"/>
<circle cx="196.8" cy="104.9" r=".15"/>
<circle cx="136.2" cy="121.2" r=".15"/>
<circle cx="172.2" cy="102.9" r=".15"/>
<circle cx="127.3" cy="97.4" r=".15"/>
<circle cx="158.4" cy="128.9" r=".15"/>
<circle cx="177.5" cy="98.5" r=".15"/>
<circle cx="199.7" cy="144.3" r=".15"/>
<circle cx="184" cy="112.1" r=".15"/>
<circle cx="186" cy="90.5" r=".15"/>
<circle cx="149.9" cy="78.2" r=".15"/>
<circle cx="185" cy="109.2" r=".15"/>
<circle cx="144.6" cy="76.8" r=".15"/>
<circle cx="185.2" cy="102.5" r=".15"/>
<circle cx="169.2" cy="70" r=".15"/>
<circle cx="119.8" cy="142" r=".15"/>
<circle cx="140.4" cy="89.3" r=".15"/>
<circle cx="157" cy="70.9" r=".15"/>
<circle cx="136.1" cy="143.9" r=".15"/>
<circle cx="157" cy="107.8" r=".15"/>
<circle cx="173.2" cy="86.8" r=".15"/>
<circle cx="202.5" cy="93" r=".15"/>
<circle cx="159.3" cy="144.4" r=".15"/>
<circle cx="152.1" cy="69" r=".15"/>
<circle cx="150.2" cy="141.3" r=".15"/>
<circle cx="154.4" cy="139.6" r=".15"/>
<circle cx="161.9" cy="128.6" r=".15"/>
<circle cx="193.9" cy="93.1" r=".15"/>
<circle cx="194.4" cy="101.7" r=".15"/>
<circle cx="181.7" cy="86.4" r=".15"/>
<circle cx="139.4" cy="78.2" r=".15"/>
<circle cx="177.1" cy="84.4" r=".15"/>
<circle cx="147.9" cy="124.6" r=".15"/>
<circle cx="140.3" cy="81.4" r=".15"/>
<circle cx="168.9" cy="119.5" r=".15"/>
<circle cx="150.7" cy="110" r=".15"/>
<circle cx="137.9" cy="85.3" r=".15"/>
<circle cx="141.3" cy="85.5" r=".15"/>
<circle cx="134.1" cy="119.5" r=".15"/>
<circle cx="158.6" cy="92.3" r=".15"/>
<circle cx="152.2" cy="142.5" r=".15"/>
<circle cx="134.6" cy="94.7" r=".15"/>
<circle cx="136" cy="142.4" r=".15"/>
<circle cx="143" cy="133.3" r=".15"/>
<circle cx="193.9" cy="91.1" r=".15"/>
<circle cx="198.1" cy="104.8" r=".15"/>
<circle cx="199" cy="95.1" r=".15"/>
<circle cx="148" cy="122.9" r=".15"/>
<circle cx="143.3" cy="91.2" r=".15"/>
<circle cx="134.2" cy="89.3" r=".15"/>
<circle cx="181.8" cy="137.7" r=".15"/>
<circle cx="175.8" cy="117.7" r=".15"/>
<circle cx="180.4" cy="106.8" r=".15"/>
<circle cx="139.8" cy="65.7" r=".2"/>
<circle cx="127.7" cy="129.2" r=".15"/>
<circle cx="163.5" cy="135.9" r=".15"/>
<circle cx="144.1" cy="111.6" r=".2"/>
<circle cx="156.4" cy="143.4" r=".2"/>
<circle cx="143.6" cy="75.6" r=".15"/>
<circle cx="140" cy="102" r=".2"/>
<circle cx="153.5" cy="71" r=".2"/>
<circle cx="146.6" cy="80.3" r=".15"/>
<circle cx="147.4" cy="135.1" r=".15"/>
<circle cx="201.8" cy="113.9" r=".15"/>
<circle cx="173.3" cy="114.4" r=".15"/>
<circle cx="133.4" cy="127.5" r=".15"/>
<circle cx="140.2" cy="117" r=".2"/>
<circle cx="192.6" cy="144.6" r=".2"/>
<circle cx="162.3" cy="119.5" r=".15"/>
<circle cx="143" cy="131.4" r=".15"/>
<circle cx="133" cy="107.8" r=".15"/>
<circle cx="165.9" cy="74.3" r=".15"/>
<circle cx="164.8" cy="96.4" r=".15"/>
<circle cx="144.3" cy="95.6" r=".2"/>
<circle cx="134.2" cy="90.4" r=".15"/>
<circle cx="133.4" cy="128.4" r=".15"/>
<circle cx="191.5" cy="78" r=".15"/>
<circle cx="146" cy="73.3" r=".15"/>
<circle cx="138" cy="133.8" r=".15"/>
<circle cx="137.9" cy="97.2" r=".2"/>
<circle cx="133.4" cy="129.3" r=".15"/>
<circle cx="147.4" cy="74.5" r=".15"/>
<circle cx="165.6" cy="76.3" r=".15"/>
<circle cx="180.7" cy="84.3" r=".15"/>
<circle cx="140.5" cy="143.3" r=".2"/>
<circle cx="170.4" cy="109.8" r=".15"/>
<circle cx="172.5" cy="68.7" r=".2"/>
<circle cx="179.9" cy="126.7" r=".15"/>
<circle cx="171.5" cy="143.5" r=".2"/>
<circle cx="195.3" cy="79.8" r=".15"/>
<circle cx="187.8" cy="141.1" r=".2"/>
<circle cx="196.7" cy="112.3" r=".2"/>
<circle cx="197.1" cy="96.9" r=".2"/>
<circle cx="199.5" cy="115.1" r=".15"/>
<circle cx="182.7" cy="79" r=".15"/>
<circle cx="195.5" cy="114.3" r=".15"/>
<circle cx="173.2" cy="82.7" r=".15"/>
<circle cx="171.7" cy="71.9" r=".15"/>
<circle cx="169.7" cy="139.2" r=".15"/>
<circle cx="172.9" cy="81.3" r=".15"/>
<circle cx="182.7" cy="77.3" r=".15"/>
<circle cx="161.1" cy="73.1" r=".15"/>
<circle cx="144" cy="71.1" r=".15"/>
<circle cx="171" cy="85.7" r=".15"/>
<circle cx="165.8" cy="125.9" r=".15"/>
<circle cx="146.9" cy="85.6" r=".15"/>
<circle cx="165.9" cy="73.5" r=".15"/>
<circle cx="139.8" cy="71.7" r=".15"/>
<circle cx="158.8" cy="71.6" r=".15"/>
<circle cx="143.8" cy="85.3" r=".15"/>
<circle cx="139.3" cy="75.4" r=".15"/>
<circle cx="151.4" cy="70.2" r=".15"/>
<circle cx="158.1" cy="71.1" r=".15"/>
<circle cx="140.6" cy="71.7" r=".15"/>
<circle cx="159.6" cy="72.1" r=".15"/>
<circle cx="177.5" cy="115.6" r=".15"/>
<circle cx="176" cy="113.9" r=".15"/>
<circle cx="177.4" cy="100.6" r=".15"/>
<circle cx="176" cy="102.5" r=".15"/>
<circle cx="163.9" cy="97.8" r=".15"/>
<circle cx="161.6" cy="108.7" r=".15"/>
<circle cx="188.5" cy="121.7" r=".15"/>
<circle cx="188.5" cy="119.6" r=".15"/>
<circle cx="185" cy="122" r=".15"/>
<circle cx="175.6" cy="114.8" r=".15"/>
<circle cx="162.6" cy="114.2" r=".15"/>
<circle cx="140.7" cy="122.2" r=".15"/>
<circle cx="164.2" cy="112.4" r=".15"/>
<circle cx="196.4" cy="85.3" r=".15"/>
<circle cx="158.2" cy="74.9" r=".15"/>
<circle cx="196.5" cy="86.2" r=".15"/>
<circle cx="159.7" cy="75.5" r=".15"/>
<circle cx="171.4" cy="98" r=".15"/>
<circle cx="173.3" cy="109.5" r=".15"/>
<circle cx="174" cy="108.6" r=".15"/>
<circle cx="170.4" cy="81.3" r=".15"/>
<circle cx="174.6" cy="107.8" r=".15"/>
<circle cx="169.6" cy="98.2" r=".15"/>
<circle cx="168" cy="111.2" r=".15"/>
<circle cx="160.4" cy="72.6" r=".15"/>
<circle cx="142.4" cy="75.6" r=".15"/>
<circle cx="165.9" cy="72.6" r=".15"/>
<circle cx="188.9" cy="77.2" r=".15"/>
<circle cx="187.9" cy="79" r=".15"/>
<circle cx="169.9" cy="138.3" r=".15"/>
<circle cx="157.2" cy="136.9" r=".15"/>
<circle cx="141.3" cy="132.7" r=".15"/>
<circle cx="132" cy="133.7" r=".15"/>
<circle cx="158.5" cy="138.2" r=".15"/>
<circle cx="139.8" cy="128.3" r=".15"/>
<circle cx="159.7" cy="139.4" r=".15"/>
<circle cx="130.6" cy="137.7" r=".15"/>
<circle cx="159.1" cy="138.8" r=".15"/>
<circle cx="156.3" cy="136.1" r=".15"/>
<circle cx="175" cy="116.1" r=".15"/>
<circle cx="181.2" cy="95.5" r=".15"/>
<circle cx="169.4" cy="112.1" r=".15"/>
<circle cx="192.2" cy="121.6" r=".15"/>
<circle cx="194.9" cy="122.8" r=".15"/>
<circle cx="175.7" cy="119.9" r=".15"/>
<circle cx="162" cy="116.5" r=".15"/>
<circle cx="166.7" cy="106.8" r=".15"/>
<circle cx="171.6" cy="86.7" r=".15"/>
<circle cx="173.7" cy="115.4" r=".15"/>
<circle cx="141.9" cy="89.4" r=".15"/>
<circle cx="162.5" cy="92.7" r=".15"/>
<circle cx="138.9" cy="89.9" r=".15"/>
<circle cx="163.1" cy="92.3" r=".15"/>
<circle cx="157.6" cy="88.8" r=".15"/>
<circle cx="151.5" cy="91.9" r=".15"/>
<circle cx="200.8" cy="100.3" r=".15"/>
<circle cx="156.5" cy="139.4" r=".15"/>
<circle cx="155.8" cy="139.7" r=".15"/>
<circle cx="140.7" cy="128.6" r=".15"/>
<circle cx="157.8" cy="137.5" r=".15"/>
<circle cx="168.7" cy="104.4" r=".15"/>
<circle cx="173.4" cy="119.7" r=".15"/>
<circle cx="168.8" cy="128.1" r=".15"/>
<circle cx="173.5" cy="118.9" r=".15"/>
<circle cx="168.9" cy="128.9" r=".15"/>
<circle cx="169" cy="129.7" r=".15"/>
<circle cx="173.7" cy="118.1" r=".15"/>
<circle cx="140" cy="85.5" r=".15"/>
<circle cx="132.7" cy="90.3" r=".15"/>
<circle cx="131.4" cy="129.9" r=".15"/>
<circle cx="145.6" cy="80" r=".15"/>
<circle cx="134.8" cy="117.7" r=".15"/>
<circle cx="117.3" cy="145" r="1.6"/>
<circle cx="117.3" cy="65" r="1.6"/>
<circle cx="203" cy="67.6" r="1.6"/>
<circle cx="203" cy="141.2" r="1.6"/>
<circle cx="122.4" cy="143.8" r=".5"/>
<circle cx="124.9" cy="143.8" r=".5"/>
<circle cx="122.4" cy="141.2" r=".5"/>
<circle cx="124.9" cy="141.2" r=".5"/>
<circle cx="122.4" cy="138.7" r=".5"/>
<circle cx="124.9" cy="138.7" r=".5"/>
<circle cx="122.4" cy="136.1" r=".5"/>
<circle cx="124.9" cy="136.1" r=".5"/>
<circle cx="122.4" cy="133.6" r=".5"/>
<circle cx="124.9" cy="133.6" r=".5"/>
<circle cx="122.4" cy="131.1" r=".5"/>
<circle cx="124.9" cy="131.1" r=".5"/>
<circle cx="122.4" cy="128.5" r=".5"/>
<circle cx="124.9" cy="128.5" r=".5"/>
<circle cx="122.4" cy="126" r=".5"/>
<circle cx="124.9" cy="126" r=".5"/>
<circle cx="122.4" cy="123.4" r=".5"/>
<circle cx="124.9" cy="123.4" r=".5"/>
<circle cx="122.4" cy="120.9" r=".5"/>
<circle cx="124.9" cy="120.9" r=".5"/>
<circle cx="122.4" cy="118.4" r=".5"/>
<circle cx="124.9" cy="118.4" r=".5"/>
<circle cx="122.4" cy="115.8" r=".5"/>
<circle cx="124.9" cy="115.8" r=".5"/>
<circle cx="122.4" cy="113.3" r=".5"/>
<circle cx="124.9" cy="113.3" r=".5"/>
<circle cx="122.4" cy="110.7" r=".5"/>
<circle cx="124.9" cy="110.7" r=".5"/>
<circle cx="122.4" cy="108.2" r=".5"/>
<circle cx="124.9" cy="108.2" r=".5"/>
<circle cx="122.4" cy="105.7" r=".5"/>
<circle cx="124.9" cy="105.7" r=".5"/>
<circle cx="122.4" cy="103.1" r=".5"/>
<circle cx="124.9" cy="103.1" r=".5"/>
<circle cx="122.4" cy="100.6" r=".5"/>
<circle cx="124.9" cy="100.6" r=".5"/>
<circle cx="122.4" cy="98" r=".5"/>
<circle cx="124.9" cy="98" r=".5"/>
<circle cx="122.4" cy="95.5" r=".5"/>
<circle cx="124.9" cy="95.5" r=".5"/>
<circle cx="122.4" cy="93" r=".5"/>
<circle cx="124.9" cy="93" r=".5"/>
<circle cx="122.4" cy="90.4" r=".5"/>
<circle cx="124.9" cy="90.4" r=".5"/>
<circle cx="122.4" cy="87.9" r=".5"/>
<circle cx="124.9" cy="87.9" r=".5"/>
<circle cx="122.4" cy="85.3" r=".5"/>
<circle cx="124.9" cy="85.3" r=".5"/>
<circle cx="122.4" cy="82.8" r=".5"/>
<circle cx="124.9" cy="82.8" r=".5"/>
<circle cx="122.4" cy="80.3" r=".5"/>
<circle cx="124.9" cy="80.3" r=".5"/>
<circle cx="122.4" cy="77.7" r=".5"/>
<circle cx="124.9" cy="77.7" r=".5"/>
<circle cx="122.4" cy="75.2" r=".5"/>
<circle cx="124.9" cy="75.2" r=".5"/>
<circle cx="122.4" cy="72.6" r=".5"/>
<circle cx="124.9" cy="72.6" r=".5"/>
<circle cx="122.4" cy="70.1" r=".5"/>
<circle cx="124.9" cy="70.1" r=".5"/>
<circle cx="122.4" cy="67.6" r=".5"/>
<circle cx="124.9" cy="67.6" r=".5"/>
<circle cx="122.4" cy="65" r=".5"/>
<circle cx="124.9" cy="65" r=".5"/>
<circle cx="202.4" cy="90.4" r=".5"/>
<circle cx="202.4" cy="87.9" r=".5"/>
<circle cx="202.4" cy="85.3" r=".5"/>
<circle cx="185.6" cy="85.7" r="1.1"/>
<circle cx="185.6" cy="67.3" r="1.1"/>
<circle cx="130.9" cy="67.3" r="1.1"/>
<circle cx="130.9" cy="85.7" r="1.1"/>
<circle cx="185.6" cy="72.6" r=".33"/>
<circle cx="185.6" cy="73.9" r=".33"/>
<circle cx="185.6" cy="75.2" r=".33"/>
<circle cx="185.6" cy="76.4" r=".33"/>
<circle cx="185.6" cy="77.7" r=".33"/>
<circle cx="185.6" cy="79" r=".33"/>
<circle cx="185.6" cy="80.3" r=".33"/>
<circle cx="202.4" cy="119.1" r=".33"/>
<circle cx="202.4" cy="117.8" r=".33"/>
<circle cx="202.4" cy="116.6" r=".33"/>
<circle cx="202.4" cy="115.3" r=".33"/>
<circle cx="130.9" cy="141.2" r="1.1"/>
<circle cx="202.4" cy="110.9" r=".5"/>
<circle cx="202.4" cy="108.3" r=".5"/>
<circle cx="202.4" cy="105.8" r=".5"/>
<circle cx="202.4" cy="100.7" r=".5"/>
<circle cx="202.4" cy="98.2" r=".5"/>
<circle cx="202.4" cy="95.6" r=".5"/>
<circle cx="202.4" cy="125.3" r=".33"/>
<circle cx="202.4" cy="124.1" r=".33"/>
<circle cx="202.4" cy="122.8" r=".33"/>
</g>
<g fill="#ff8a8a" stroke="#ff8a8a" stroke-width=".14">
<path d="M169.8 107.6h.4v1.4l-.4-.1z"/>
<path d="M169.2 107.6h.4l-.1 1.4-.3-.1z"/>
<path d="M168.5 107.6h.4v1.4l-.4-.1z"/>
<path d="M167.9 107.6h.4l-.1 1.4-.3-.1z"/>
<path d="M167.2 107.6h.4v1.4l-.4-.1z"/>
<path d="M166.6 107.6h.4l-.1 1.4-.3-.1z"/>
<path d="M165.9 107.6h.4v1.4l-.4-.1z"/>
<path d="M165.3 107.6h.4l-.1 1.4-.3-.1z"/>
<path d="M165.3 101.8l.4 .1-.1 1.4-.3-.1z"/>
<path d="M165.9 101.8l.4 .1v1.4l-.4-.1z"/>
<path d="M166.6 101.8l.4 .1-.1 1.4-.3-.1z"/>
<path d="M167.2 101.8l.4 .1v1.4l-.4-.1z"/>
<path d="M167.9 101.8l.4 .1-.1 1.4-.3-.1z"/>
<path d="M168.5 101.8l.4 .1v1.4l-.4-.1z"/>
<path d="M169.2 101.8l.4 .1-.1 1.4-.3-.1z"/>
<path d="M169.8 101.8l.4 .1v1.4l-.4-.1z"/>
<path d="M171.3 114.7h1.4v.3l-1.4 .1z"/>
<path d="M171.3 115.3h1.4v.4h-1.4z"/>
<path d="M171.3 116h1.4v.3l-1.4 .1z"/>
<path d="M171.3 116.6h1.4v.4h-1.4z"/>
<path d="M171.3 117.3h1.4v.3l-1.4 .1z"/>
<path d="M171.3 117.9h1.4v.4h-1.4z"/>
<path d="M171.3 118.6h1.4v.3l-1.4 .1z"/>
<path d="M171.3 119.2h1.4v.4h-1.4z"/>
<path d="M165.5 119.2h1.4l.1 .4h-1.4z"/>
<path d="M165.5 118.6h1.4l.1 .3-1.4 .1z"/>
<path d="M165.5 117.9h1.4l.1 .4h-1.4z"/>
<path d="M165.5 117.3h1.4l.1 .3-1.4 .1z"/>
<path d="M165.5 116.6h1.4l.1 .4h-1.4z"/>
<path d="M165.5 116h1.4l.1 .3-1.4 .1z"/>
<path d="M165.5 115.3h1.4l.1 .4h-1.4z"/>
<path d="M165.5 114.7h1.4l.1 .3-1.4 .1z"/>
<path d="M175.1 132.5l1.8-.1 .1 .5-.2 .1h-1.6l-.1-.1z"/>
<path d="M175.1 133.7h1.8l.1 .5-.2 .1h-1.6l-.1-.2z"/>
<path d="M175.1 135h1.8l.1 .5h-.2h-1.6l-.1-.1z"/>
<path d="M175.1 136.3l1.8-.1 .1 .5-.2 .1h-1.6l-.1-.1z"/>
<path d="M182.1 136.3l1.8-.1 .1 .5-.2 .1h-1.6l-.1-.1z"/>
<path d="M182.1 135h1.8l.1 .5h-.2h-1.6l-.1-.1z"/>
<path d="M182.1 133.7h1.8l.1 .5-.2 .1h-1.6l-.1-.2z"/>
<path d="M182.1 132.5l1.8-.1 .1 .5-.2 .1h-1.6l-.1-.1z"/>
<path d="M176.2 127.6h.9v1.3h-.9z"/>
<path d="M179.2 127.6h.9v1.3h-.9z"/>
<path d="M177.3 124.3h1.7v3.1h-.4v1.5h-.9v-1.5h-.4z"/>
<path d="M163.8 119.1h.5v.5h-.5z"/>
<path d="M163.8 118.1h.5v.5h-.5z"/>
<path d="M173 139h.6v.4h-.6z"/>
<path d="M173 140h.6v.4h-.6z"/>
<path d="M170.9 138.9h.5v.6h-.5z"/>
<path d="M179.8 140h.5v.4h-.5z"/>
<path d="M179.8 141.5h.5v.5h-.5z"/>
<path d="M179.8 142.5h.5v.5h-.5z"/>
<path d="M177.3 129.9h.7v.8h-.7z"/>
<path d="M175.7 129.9h.8v.8h-.8z"/>
<path d="M179.3 129.9h.7v.8h-.7z"/>
<path d="M133.5 101.7h.4v.5h-.4z"/>
<path d="M134.4 101.7h.5v.5h-.5z"/>
<path d="M132 102.4h.8v.5h-.8z"/>
<path d="M132 101.5h.8v.5h-.8z"/>
<path d="M130.4 101.5h.7v.5h-.7z"/>
<path d="M138.4 120.7h.5v.4h-.5z"/>
<path d="M138.4 119.6h.5v.5h-.5z"/>
<path d="M132.7 124.6h.4v.5h-.4z"/>
<path d="M131.7 124.6h.5v.5h-.5z"/>
<path d="M169.8 134.6h1.2v1.4h-1.2z"/>
<path d="M171.5 134.6h1.2v1.4h-1.2z"/>
<path d="M159.1 94.8h1.7v1.7h-1.7z"/>
<path d="M159.1 97.3h1.7v1.7h-1.7z"/>
<path d="M159.1 99.9h1.7v1.7h-1.7z"/>
<path d="M159.1 102.4h1.7v1.7h-1.7z"/>
<path d="M141.3 94.8h1.7v1.7h-1.7z"/>
<path d="M141.3 97.3h1.7v1.7h-1.7z"/>
<path d="M141.3 99.9h1.7v1.7h-1.7z"/>
<path d="M141.3 102.4h1.7v1.7h-1.7z"/>
<path d="M141.2 133.5h.5v.5h-.5z"/>
<path d="M141.2 134.5h.5v.5h-.5z"/>
<path d="M146.5 135.8l1.7-.1 .1 .2v.7l-.2 .1h-1.5l-.2-.2z"/>
<path d="M130.4 103.6h.5v.5h-.5z"/>
<path d="M177.8 87.4h1.7v1.7h-1.7z"/>
<path d="M175.2 87.4h1.7v1.7h-1.7z"/>
<path d="M172.7 87.4h1.7v1.7h-1.7z"/>
<path d="M170.2 87.4h1.7v1.7h-1.7z"/>
<path d="M177.8 69.6h1.7v1.7h-1.7z"/>
<path d="M175.2 69.6h1.7v1.7h-1.7z"/>
<path d="M172.7 69.6h1.7v1.7h-1.7z"/>
<path d="M170.2 69.6h1.7v1.7h-1.7z"/>
<path d="M166.8 142.4h.6v.4h-.6z"/>
<path d="M187.3 124.3h1.7v1.7h-1.7z"/>
<path d="M189.9 124.3h1.7v1.7h-1.7z"/>
<path d="M192.4 124.3h1.7v1.7h-1.7z"/>
<path d="M194.9 124.3h1.7v1.7h-1.7z"/>
<path d="M187.3 142.1h1.7v1.7h-1.7z"/>
<path d="M189.9 142.1h1.7v1.7h-1.7z"/>
<path d="M192.4 142.1h1.7v1.7h-1.7z"/>
<path d="M194.9 142.1h1.7v1.7h-1.7z"/>
<path d="M139 133.6h.5v.5h-.5z"/>
<path d="M131.7 119.2h.5v.6h-.5z"/>
<path d="M132.7 119.2h.4v.6h-.4z"/>
<path d="M149.2 139.1h1.5v.5h-1.5z"/>
<path d="M149.2 138.3h1.5v.5h-1.5z"/>
<path d="M149.2 137.5h1.5v.5h-1.5z"/>
<path d="M149.2 136.7h1.5v.5h-1.5z"/>
<path d="M149.2 135.9h1.5v.5h-1.5z"/>
<path d="M149.2 135.1h1.5v.5h-1.5z"/>
<path d="M149.2 134.3h1.5v.5h-1.5z"/>
<path d="M149.2 133.5h1.5v.5h-1.5z"/>
<path d="M149.2 132.7h1.5v.5h-1.5z"/>
<path d="M149.2 131.9h1.5v.5h-1.5z"/>
<path d="M149.2 131.1h1.5v.5h-1.5z"/>
<path d="M149.2 130.3h1.5v.5h-1.5z"/>
<path d="M149.2 129.5h1.5v.5h-1.5z"/>
<path d="M149.2 128.7h1.5v.5h-1.5z"/>
<path d="M149.2 127.9h1.5v.5h-1.5z"/>
<path d="M149.2 127.1h1.5v.5h-1.5z"/>
<path d="M151.4 124.9h.6v1.5h-.6z"/>
<path d="M152.2 124.9h.6v1.5h-.6z"/>
<path d="M153 124.9h.6v1.5h-.6z"/>
<path d="M153.8 124.9h.6v1.5h-.6z"/>
<path d="M154.6 124.9h.6v1.5h-.6z"/>
<path d="M155.4 124.9h.6v1.5h-.6z"/>
<path d="M156.2 124.9h.6v1.5h-.6z"/>
<path d="M157 124.9h.6v1.5h-.6z"/>
<path d="M157.8 124.9h.6v1.5h-.6z"/>
<path d="M158.6 124.9h.6v1.5h-.6z"/>
<path d="M159.4 124.9h.6v1.5h-.6z"/>
<path d="M160.2 124.9h.6v1.5h-.6z"/>
<path d="M161 124.9h.6v1.5h-.6z"/>
<path d="M161.8 124.9h.6v1.5h-.6z"/>
<path d="M162.6 124.9h.6v1.5h-.6z"/>
<path d="M163.4 124.9h.6v1.5h-.6z"/>
<path d="M164.6 127.1h1.5v.5h-1.5z"/>
<path d="M164.6 127.9h1.5v.5h-1.5z"/>
<path d="M164.6 128.7h1.5v.5h-1.5z"/>
<path d="M164.6 129.5h1.5v.5h-1.5z"/>
<path d="M164.6 130.3h1.5v.5h-1.5z"/>
<path d="M164.6 131.1h1.5v.5h-1.5z"/>
<path d="M164.6 131.9h1.5v.5h-1.5z"/>
<path d="M164.6 132.7h1.5v.5h-1.5z"/>
<path d="M164.6 133.5h1.5v.5h-1.5z"/>
<path d="M164.6 134.3h1.5v.5h-1.5z"/>
<path d="M164.6 135.1h1.5v.5h-1.5z"/>
<path d="M164.6 135.9h1.5v.5h-1.5z"/>
<path d="M164.6 136.7h1.5v.5h-1.5z"/>
<path d="M164.6 137.5h1.5v.5h-1.5z"/>
<path d="M164.6 138.3h1.5v.5h-1.5z"/>
<path d="M164.6 139.1h1.5v.5h-1.5z"/>
<path d="M163.4 140.3h.6v1.5h-.6z"/>
<path d="M162.6 140.3h.6v1.5h-.6z"/>
<path d="M161.8 140.3h.6v1.5h-.6z"/>
<path d="M161 140.3h.6v1.5h-.6z"/>
<path d="M160.2 140.3h.6v1.5h-.6z"/>
<path d="M159.4 140.3h.6v1.5h-.6z"/>
<path d="M158.6 140.3h.6v1.5h-.6z"/>
<path d="M157.8 140.3h.6v1.5h-.6z"/>
<path d="M157 140.3h.6v1.5h-.6z"/>
<path d="M156.2 140.3h.6v1.5h-.6z"/>
<path d="M155.4 140.3h.6v1.5h-.6z"/>
<path d="M154.6 140.3h.6v1.5h-.6z"/>
<path d="M153.8 140.3h.6v1.5h-.6z"/>
<path d="M153 140.3h.6v1.5h-.6z"/>
<path d="M152.2 140.3h.6v1.5h-.6z"/>
<path d="M151.4 140.3h.6v1.5h-.6z"/>
<path d="M139 132.4h.5v.6h-.5z"/>
<path d="M117.5 138.8h.8v.8h-.8z"/>
<path d="M117.5 140.3h.8v.8h-.8z"/>
<path d="M201.5 103.3h.5v.4h-.5z"/>
<path d="M201.5 102.3h.5v.4h-.5z"/>
<path d="M141.5 124.1h.4l-.1 1.4-.3-.1z"/>
<path d="M140.9 124.1h.3v1.4l-.4-.1z"/>
<path d="M140.2 124.1h.4l-.1 1.4-.3-.1z"/>
<path d="M139.6 124.1h.3v1.4l-.4-.1z"/>
<path d="M138.9 124.1h.4l-.1 1.4-.3-.1z"/>
<path d="M138.3 124.1h.3v1.4l-.4-.1z"/>
<path d="M137.6 124.1h.4l-.1 1.4-.3-.1z"/>
<path d="M137 124.1h.3v1.4l-.4-.1z"/>
<path d="M136.3 124.1h.4l-.1 1.4-.3-.1z"/>
<path d="M135.7 124.1h.3v1.4l-.4-.1z"/>
<path d="M135.7 129.8h.3v1.4h-.4z"/>
<path d="M136.3 129.8h.4l-.1 1.4h-.3z"/>
<path d="M137 129.8h.3v1.4h-.4z"/>
<path d="M137.6 129.8h.4l-.1 1.4h-.3z"/>
<path d="M138.3 129.8h.3v1.4h-.4z"/>
<path d="M138.9 129.8h.4l-.1 1.4h-.3z"/>
<path d="M139.6 129.8h.3v1.4h-.4z"/>
<path d="M140.2 129.8h.4l-.1 1.4h-.3z"/>
<path d="M140.9 129.8h.3v1.4h-.4z"/>
<path d="M141.5 129.8h.4l-.1 1.4h-.3z"/>
<path d="M164.2 142.3h.5v.6h-.5z"/>
<path d="M178.5 100.7h1.7v1.7h-1.7z"/>
<path d="M178.5 98.2h1.7v1.7h-1.7z"/>
<path d="M178.5 95.7h1.7v1.7h-1.7z"/>
<path d="M178.5 93.1h1.7v1.7h-1.7z"/>
<path d="M196.3 100.7h1.7v1.7h-1.7z"/>
<path d="M196.3 98.2h1.7v1.7h-1.7z"/>
<path d="M196.3 95.7h1.7v1.7h-1.7z"/>
<path d="M196.3 93.1h1.7v1.7h-1.7z"/>
<path d="M137.1 119.6h.5v.5h-.5z"/>
<path d="M137.1 120.7h.5v.4h-.5z"/>
<path d="M131.5 103.6h.5v.5h-.5z"/>
<path d="M128.3 101.5h.4v.6h-.4z"/>
<path d="M171.5 136.8h.5v.5h-.5z"/>
<path d="M170.6 136.8h.4v.5h-.4z"/>
<path d="M159.2 109.9h1.7v1.7h-1.7z"/>
<path d="M159.2 112.5h1.7v1.7h-1.7z"/>
<path d="M159.2 115h1.7v1.7h-1.7z"/>
<path d="M159.2 117.6h1.7v1.7h-1.7z"/>
<path d="M141.4 109.9h1.7v1.7h-1.7z"/>
<path d="M141.4 112.5h1.7v1.7h-1.7z"/>
<path d="M141.4 115h1.7v1.7h-1.7z"/>
<path d="M141.4 117.6h1.7v1.7h-1.7z"/>
<path d="M145.3 86.4h1.7v1.7h-1.7z"/>
<path d="M142.7 86.4h1.7v1.7h-1.7z"/>
<path d="M140.2 86.4h1.7v1.7h-1.7z"/>
<path d="M137.7 86.4h1.7v1.7h-1.7z"/>
<path d="M145.3 68.6h1.7v1.7h-1.7z"/>
<path d="M142.7 68.6h1.7v1.7h-1.7z"/>
<path d="M140.2 68.6h1.7v1.7h-1.7z"/>
<path d="M137.7 68.6h1.7v1.7h-1.7z"/>
<path d="M131.4 112.5h.6v.5h-.6z"/>
<path d="M131.4 113.5h.6v.4h-.6z"/>
<path d="M147.6 140.6h.5v.5h-.5z"/>
<path d="M146.7 140.6h.5v.5h-.5z"/>
<path d="M178.5 115.6h1.7v1.7h-1.7z"/>
<path d="M178.5 113.1h1.7v1.7h-1.7z"/>
<path d="M178.5 110.5h1.7v1.7h-1.7z"/>
<path d="M178.5 108h1.7v1.7h-1.7z"/>
<path d="M196.3 115.6h1.7v1.7h-1.7z"/>
<path d="M196.3 113.1h1.7v1.7h-1.7z"/>
<path d="M196.3 110.5h1.7v1.7h-1.7z"/>
<path d="M196.3 108h1.7v1.7h-1.7z"/>
<path d="M128.9 109.9h.4l.2 .1v1.7l-.1 .1h-.5z"/>
<path d="M130.2 109.9h.4l.1 .1v1.7l-.1 .1h-.5z"/>
<path d="M131.4 109.9h.5l.1 .1v1.7l-.1 .1h-.5z"/>
<path d="M132.7 109.9h.4l.2 .1v1.7l-.1 .1h-.5z"/>
<path d="M132.7 105l.4-.1 .2 .1v1.7l-.1 .2-.5-.1z"/>
<path d="M131.4 105l.5-.1 .1 .1v1.7l-.1 .2-.5-.1z"/>
<path d="M130.2 105l.4-.1 .1 .1v1.7l-.1 .2-.5-.1z"/>
<path d="M142.7 130.2h.5v.5h-.5z"/>
<path d="M142.7 129.2h.5v.5h-.5z"/>
<path d="M132.7 122.6h1.2v1.4h-1.2z"/>
<path d="M131 122.6h1.2v1.4h-1.2z"/>
<path d="M199.9 98.3h.6v.5h-.6z"/>
<path d="M199.9 99.3h.6v.5h-.6z"/>
<path d="M134.9 107.3h.8v.8h-.8z"/>
<path d="M134.9 108.9h.8v.7h-.8z"/>
<path d="M170.6 131.2h.4v.5h-.4z"/>
<path d="M171.5 131.2h.5v.5h-.5z"/>
<path d="M148 129.6h.6v.5h-.6z"/>
<path d="M148 130.5h.6v.5h-.6z"/>
<path d="M145.9 129.8h1.2l.1 .2v.6l-.2 .1h-1.1l-.1-.2z"/>
<path d="M145.9 131.7h1.2l.1 .2v.6l-.2 .1h-1.1l-.1-.2z"/>
<path d="M117.5 70.5h.8v.8h-.8z"/>
<path d="M117.5 68.9h.8v.8h-.8z"/>
<path d="M161.3 86h1.7v1.7h-1.7z"/>
<path d="M158.7 86h1.7v1.7h-1.7z"/>
<path d="M156.2 86h1.7v1.7h-1.7z"/>
<path d="M153.7 86h1.7v1.7h-1.7z"/>
<path d="M161.3 68.2h1.7v1.7h-1.7z"/>
<path d="M158.7 68.2h1.7v1.7h-1.7z"/>
<path d="M156.2 68.2h1.7v1.7h-1.7z"/>
<path d="M153.7 68.2h1.7v1.7h-1.7z"/>
<path d="M131.4 130.6h.7v2.4h-.7z"/>
<path d="M131.4 134.5h.7v2.4h-.7z"/>
<path d="M130.1 130.6h.8v2.4h-.8z"/>
<path d="M130.1 134.5h.8v2.4h-.8z"/>
<path d="M128.9 130.6h.7v2.4h-.7z"/>
<path d="M128.9 134.5h.7v2.4h-.7z"/>
</g>
<g fill="none" stroke="#626262" stroke-width=".14">
<path d="M121 63.6h5.3v81.6h-5.3zM136.5 69.2h-1.3v1.3M142.2 66.9h15.9M148.2 69.2h1.2v1.3M152.5 68.8h-1.3v1.3M164.2 68.8h1.2v1.3M169 70.2h-1.3v1.3M172.3 66.9h8.4M180.7 70.2h1.2v1.3M191.3 67.4h8.2v21.1h-8.2zM126.3 96.8h10.7v18.9h-10.7M135.2 86.2v1.3h1.3"/>
<path d="M143.2 92.3h-1.3v1.3M149.4 86.2v1.3h-1.2M151.2 85.8v1.3h1.3M159 92.3h1.2v1.3M165.4 85.8v1.3h-1.2M167.7 87.2v1.3h1.3M168.1 92.2h3.6v6h-3.6zM180.3 90.7h-1.2v1.2M181.9 87.2v1.3h-1.2M196.1 90.7h1.3v1.2M200.6 98.9v.3M128.5 106.4v5.4"/>
<path d="M129.2 112.6l.4 .4h-.7zM130.2 103.1h2.4M130.6 101.3h2M132.1 103.5h.2M134.1 101.6h.2M135.8 108.3v.3M141.9 105.3v1.3h1.3M143.3 107.5h-1.3v1.3M159 107.5h1.3v1.3M160.2 105.3v1.3h-1.2M163.7 118.7v.3M165.5 114.4h5.8"/>
<path d="M165.8 113.7h.8l-.4 .3zM170.5 101.8v5.8M171.3 102.1v.8l-.4-.4zM174.3 119.9v-7.9h-1.6v-11.2h-9.6v20.1h11.1M179.1 103.6v1.3h1.2M179.1 118.5v1.3h1.3M180.4 105.6h-1.3v1.2M196.1 105.6h1.3v1.2M197.4 103.6v1.3h-1.3M197.4 118.5v1.3h-1.3M128.5 132v3.5M132.3 125.2h.2"/>
<path d="M132.4 130.6v4.9M134.1 120.2v4h-3.3M137.7 120.2v.3M138.3 120.2v.3M141.8 134.1v.2M142 120.4v1.3h1.3M142.1 124v5.8M142.5 124.8l.4-.4v.8zM142.6 129.8v.3M148.6 130.2v.2M160.3 120.4v1.3h-1.3M171.2 131.1h.2"/>
<path d="M172.9 132.2h-3.3v4M173.7 139.5v.3M175.3 123.4v7.8l-.9 .9v11.4M175.8 131.4h.6l-.3 .3zM176.7 130.8h.3M176.8 137.1v.7h5.5v-.7M177.1 125h-1.3v2.7h.2v1.1M179.2 125h1.3v2.7h-.2M180.3 129.8h.3M182.3 131.4h-5.5v.7h-1.7M183.6 131.8v-8.4h-39v20.1h39v-6M186.1 124.9h-1.2v1.3"/>
<path d="M197.8 124.9h1.3v1.3M151.7 142.2l.3 .4h-.5zM184.9 141.9v1.3h1.2M199.1 141.9v1.3h-1.3"/>
</g>
<g fill="#626262" stroke="#626262" stroke-width=".14">
<path d="M191.3 67.4h8.2v21.1h-8.2z"/>
<path d="M169 124.5l2.1 .1h-1.8l-.5 .4 .5-.4h2.2a5.7 5.7 0 0 1 2.3 .4l.3 .5 .1 .6a1.48 1.48 0 0 0-1.6-1.2l-1.6-.2a1.76 1.76 0 0 0-2.4 1v.4l.5 .7h-.1l-.6-.5 .2 .9 .4-.4h.1l-.1 .3a.41 .41 0 0 0-.2 .5 .41 .41 0 0 0 .5 .2l1.5-.1a1.06 1.06 0 0 1 1.6 .1 1.59 1.59 0 0 0 1.8-1.2 1.04 1.04 0 0 1-1 1.2l-.9 .2a.81 .81 0 0 1-.8 .1v-.1a.41 .41 0 0 0 .6-.4 .89 .89 0 0 0-1.1 .1l.4 .4h-.3a1.65 1.65 0 0 0-1.2-.2 1.31 1.31 0 0 1-1.3-.2 4 4 0 0 1 .1-2.9z"/>
<path d="M171.7 125.2l.3-.1 .1 .2h-.2h.2a.21 .21 0 0 1-.3 .2 .21 .21 0 0 1-.1-.3z"/>
<path d="M172.8 125.3a1.19 1.19 0 0 1 1.3 .9h-.2a1.08 1.08 0 0 0-.9-.7v1.4l-.2 .5a1.31 1.31 0 0 0 1.1-1.2h.2a1.45 1.45 0 0 1-1.6 1.5 3 3 0 0 0 .3-2.4z"/>
<path d="M171.2 125a.77 .77 0 0 1 1.3 .3h-.2a.51 .51 0 0 0-.6-.4 .51 .51 0 0 0-.4 .6 .53 .53 0 0 0 .6 .3 .53 .53 0 0 0 .4-.5h.2a.66 .66 0 0 1-.9 .7 .66 .66 0 0 1-.4-1z"/>
</g>
<g fill="none" stroke="#626262" stroke-width=".15">
<path d="M127.9 66.9h-.6l-.1 .3 .1 .1M129.7 73.9l.9 .3 .1 .2M129.7 73.5h.1M130.3 73.5h.1M131.5 74l.1 .3 .1 .1 .3-.1-.1-.3M132 74h-.6v.4M133 71.9l-.1 .2 .2 .2 .4-.1v-.3M133 71.1l-.1 .2 .2 .2 .1-.1 .1-.3h.2v.4M142.2 66.4l.4-1 .3 1M142.3 66.1h.5M158 65.4v.8l.1 .2M127 85.9a.54 .54 0 0 1 .6-.2 .54 .54 0 0 1 .3 .6h-1z"/>
<path d="M150.5 139.8v.7h.6v1.3M151.2 126.2h-.7v.6M164.2 126.2h.7v.6M164.9 139.8v.7M168.6 139.3h.6l-.3 .4h.3v.5l-.2 .1-.4-.1M189.2 129.1l-.1-.3 .2-.1h.1l.1 .4M189.7 139.6l.1 .1-.1 .3h-.6M189.7 128.7v.4h-.6M142.9 142.6v.5"/>
</g>
<path d="M113.7 61.4a5.1 5.1 0 0 1 3.6-1.5h10.2l3.4 2.6h72.1a5.1 5.1 0 0 1 5.1 5.2v13.2l-3.2 2.5v43.2l3.2 2.6v12a5.1 5.1 0 0 1-5.1 5.1h-70.5l-5 3.8h-10.2a5.1 5.1 0 0 1-5.1-5.1v-3.8l3.8-3.8v-64.8l-3.8-3.8v-3.8a5.1 5.1 0 0 1 1.5-3.6z" fill="none" stroke="#ff8000" stroke-width=".14"/>
<g fill="none" stroke="#000080" stroke-width=".15">
<path d="M10 10.2h277v190.1h-277zM12 12.2h273v186.1h-273zM60 10.2v2M110 10.2v2M160 10.2v2M210 10.2v2M260 10.2v2M10 60.2h2M118.9 65.7v.6M119.6 65.7l.3 .3h-1M119.9 73.9l-1 .3 1 .4M137.3 71.6l-.5 .3 .5 .3"/>
<path d="M153.3 71.2l-.5 .3 .5 .4M169.8 72.6l-.5 .3 .5 .4M285 60.2h2M136.3 84.5v-.4h1v.4M152.3 84.1v-.4h1v.4M168.8 85.5v-.4h1v.4M181.9 91.6l.4 .6 .3-.6M194.9 91.6h-.5v1h.5M10 110.2h2M134 113.5h1l-1 .6h1M144.3 104.5l.3 .5 .4-.5M144.4 119.6l.3 .6 .3-.6"/>
<path d="M157.3 104.5h-.5v1h.5M157.3 119.6h-.5v1h.5M163.9 111.2l-.1 .2 .1 .3 .4 .1 .1-.1 .1-.3-.1-.2 .4 .1v.4M182 106.5l.3 .6 .4-.6M194.9 106.5h-.4v1h.4M285 110.2h2M116 135.6v.6M116.8 135.6l.2 .3h-1M127.1 135.9h1l-.1 .5-.2 .1-.2-.1v-.5M135.1 132.3v.6M150.7 126.3h14v14h-13l-1-1zM162.7 120h.7l-.5 1"/>
<path d="M166.7 127.2l1 .3-1 .4M173 139.1l.3-1 .3 1M175.4 120h-.4l-.1 .5 .2-.1 .3 .1 .1 .1-.1 .3-.1 .1-.4-.1M185.5 138.1h.6M185.8 138.1v1M198.1 127.8l-.5 .3 .5 .4M117 143.7l-1 .4 1 .3M177.7 143.2l.6 .5M177.8 143.3l-.5 .4M197.1 140.7v-.4h1v.4M10 160.2h2M177 166.3h108v32h-108z"/>
<path d="M203.6 176.9l.3 1 .4-1M204.9 176.4l-.1 .1 .1 .1v-.1v-.1v.2M204.9 176.9v1M206.2 177l-.4-.1-.3 .3v.4l.1 .3h.2h.4M206.9 177.1a.37 .37 0 0 1 .6 0v.8M206.9 176.4v1.5M285 160.2h2M60 198.3v2M110 198.3v2M160 198.3v2M177 194.8h108M177 191.8h108"/>
<path d="M177 187.8h108M177 181.8h108M186.5 192.5l-.4 1h1M186.9 193v1M194.9 182.4v1.3l.2 .2M195.5 182.9l.4 1M196.2 182.9l-.5 1.4-.2 .1M197 191.8v3M204.1 196.7v.1h-.1l.1-.1v.1M204.9 195.4a.36 .36 0 0 1 .6 .2 .77 .77 0 0 1-.4 1.2 1 1 0 0 1-.2-1.4zM205.3 185.7l-.4-.1-.3 .3v.4l.1 .3h.2h.4M205.3 185.1v1.5"/>
<path d="M205.6 186.8h1.2M206.2 196.7l.1 .1h-.1h-.1l.1-.1v.1M207 195.5a.36 .36 0 0 1 .4-.2 .36 .36 0 0 1 .2 .3 .77 .77 0 0 1-.4 1.2 .91 .91 0 0 1-.2-1.3zM207.1 185.7l.5-.1 .3 .3v.4l-.2 .3h-.1h-.5M207.1 185.6v1.5M208.2 195.1a1.72 1.72 0 0 1 0 2.3M209.1 185.7l-.4-.1-.3 .3v.4l.2 .3h.1h.4M209.8 185.7l.4-.1 .3 .3v.4l-.1 .3h-.2h-.4M209.8 185.1v1.5M210 198.3v2M216.2 192.7l.2-.2 .5 .1a.41 .41 0 0 1 .1 .6l-.9 .8h1M217.7 193.5h1.2"/>
<path d="M219.6 192.7a.36 .36 0 0 1 .4-.2 .36 .36 0 0 1 .3 .3 .77 .77 0 0 1-.4 1.2 .91 .91 0 0 1-.3-1.3zM221.2 193.2l-.1-.1a.31 .31 0 0 1-.2-.3 .31 .31 0 0 1 .3-.3l.4 .1a.31 .31 0 0 1 .2 .3 .31 .31 0 0 1-.3 .3h-.3l-.3 .3 .1 .4 .2 .1h.3l.3-.3-.1-.4-.2-.1M260 198.3v2M261 191.8v6.5M269.9 195.3l-1.3 1.9M270.3 195.8l.4-.5v1.5M270.3 196.8h.8"/>
</g>
<path d="M225.6 189.2a.66 .66 0 0 0-1 .3l-.1 .6 .2 .3 .1 .1 .6-.1M225.7 188.5l-.3 2M226.5 189.1l-.1 1.1 .1 .2a.57 .57 0 0 0 .8-.1M227.4 189.1l-.2 1.4M228.4 188.5l-.2 1.7 .1 .2 .2 .1M229.2 189.8l1-.2-.1-.4-.1-.1-.6 .1-.1 .2-.1 .8v.2l.2 .1 .6-.1" fill="none" stroke="#000080" stroke-width=".4"/>
<path d="M209.9 179.4v1.5h.7M211.1 179.4v1.5h.7M213.2 179.6a.6 .6 0 0 0-.7 0 .6 .6 0 0 0-.2 .7 .56 .56 0 0 0 .3 .6 .56 .56 0 0 0 .6-.1" fill="none" stroke="#000080" stroke-width=".3"/>
<g fill="none" stroke="#000080" stroke-width=".14">
<path d="M117.5 69.3h.8v1.6h-.8zM200 98.5h.5v1.1h-.5M128.5 101.5v.5M128.6 106.4h4.9v3.9h-3.9l-1-.9zM130.6 101.5h2v1.3h-1.6M130.7 103.6v.5h-1M131.5 112.7h.5v1h-.5M131.9 119.3v.5M132.7 103.6h-1v.5M132.9 119.3v.5M133.7 102.2v-.5h1v.5M134.9 107.7h.8v1.6h-.8"/>
<path d="M137.1 119.9h.5v1h-.5M138.9 119.9h-.5v1h.5M164.3 118.3h-.5v1.1h.5M165.2 103.2h4l1 1v3.4h-5zM166.9 115.6l1-1h3.4v5h-4.4zM201.5 103.5h.5M201.5 102.5h.5M117.5 139.1h.8v1.6h-.8zM128.6 132h3.4l.4 .5v2.9h-3.8zM129 132v-1h.4v1M129 135.4v1.1h.4v-1.1M130.3 132v-1h.4v1"/>
<path d="M130.3 135.4v1.1h.4v-1.1M131.2 120.6h2.5v3.2h-2.5zM131.6 132v-1h.4v1M131.6 135.4v1.1h.4v-1.1M131.9 124.6v.5h1v-.5M135.5 125.4h5.5l1 1v3.4h-6.5zM139.3 132.4v.6h1M140.3 133.6h-1v.5M141.2 133.7h.5v1h-.5M143.2 129.4h-.5v1h.5M146.6 139.4v-3.2h1.6v3.2M147.1 130.2h-1.2v2h1.2"/>
<path d="M148 129.8h.5v1h-.5M170 132.6h2.5v3.2h-2.5zM170.8 131.7v-.5h1v.5M170.8 136.8v.5M171.1 138.9v.6h1.1M171.8 136.8v.5M173 139.2h.6v1h-.6M175.9 125.1h4.5v2.5h-3.5l-1-1zM176.1 129.9h1.6v.8h-1.6zM177.9 131.5h4.3v6.2h-5.3v-5.2zM180.3 139.2v1h-.5M181.2 129.9h-1.6v.8h1.6"/>
<path d="M146.9 140.6v.5h1v-.5M164.4 142.4v.5h1M167.4 141.6v1h-.6M179.8 141.7h.5v1.1h-.5"/>
</g>
<use href="#words"/>
</svg>
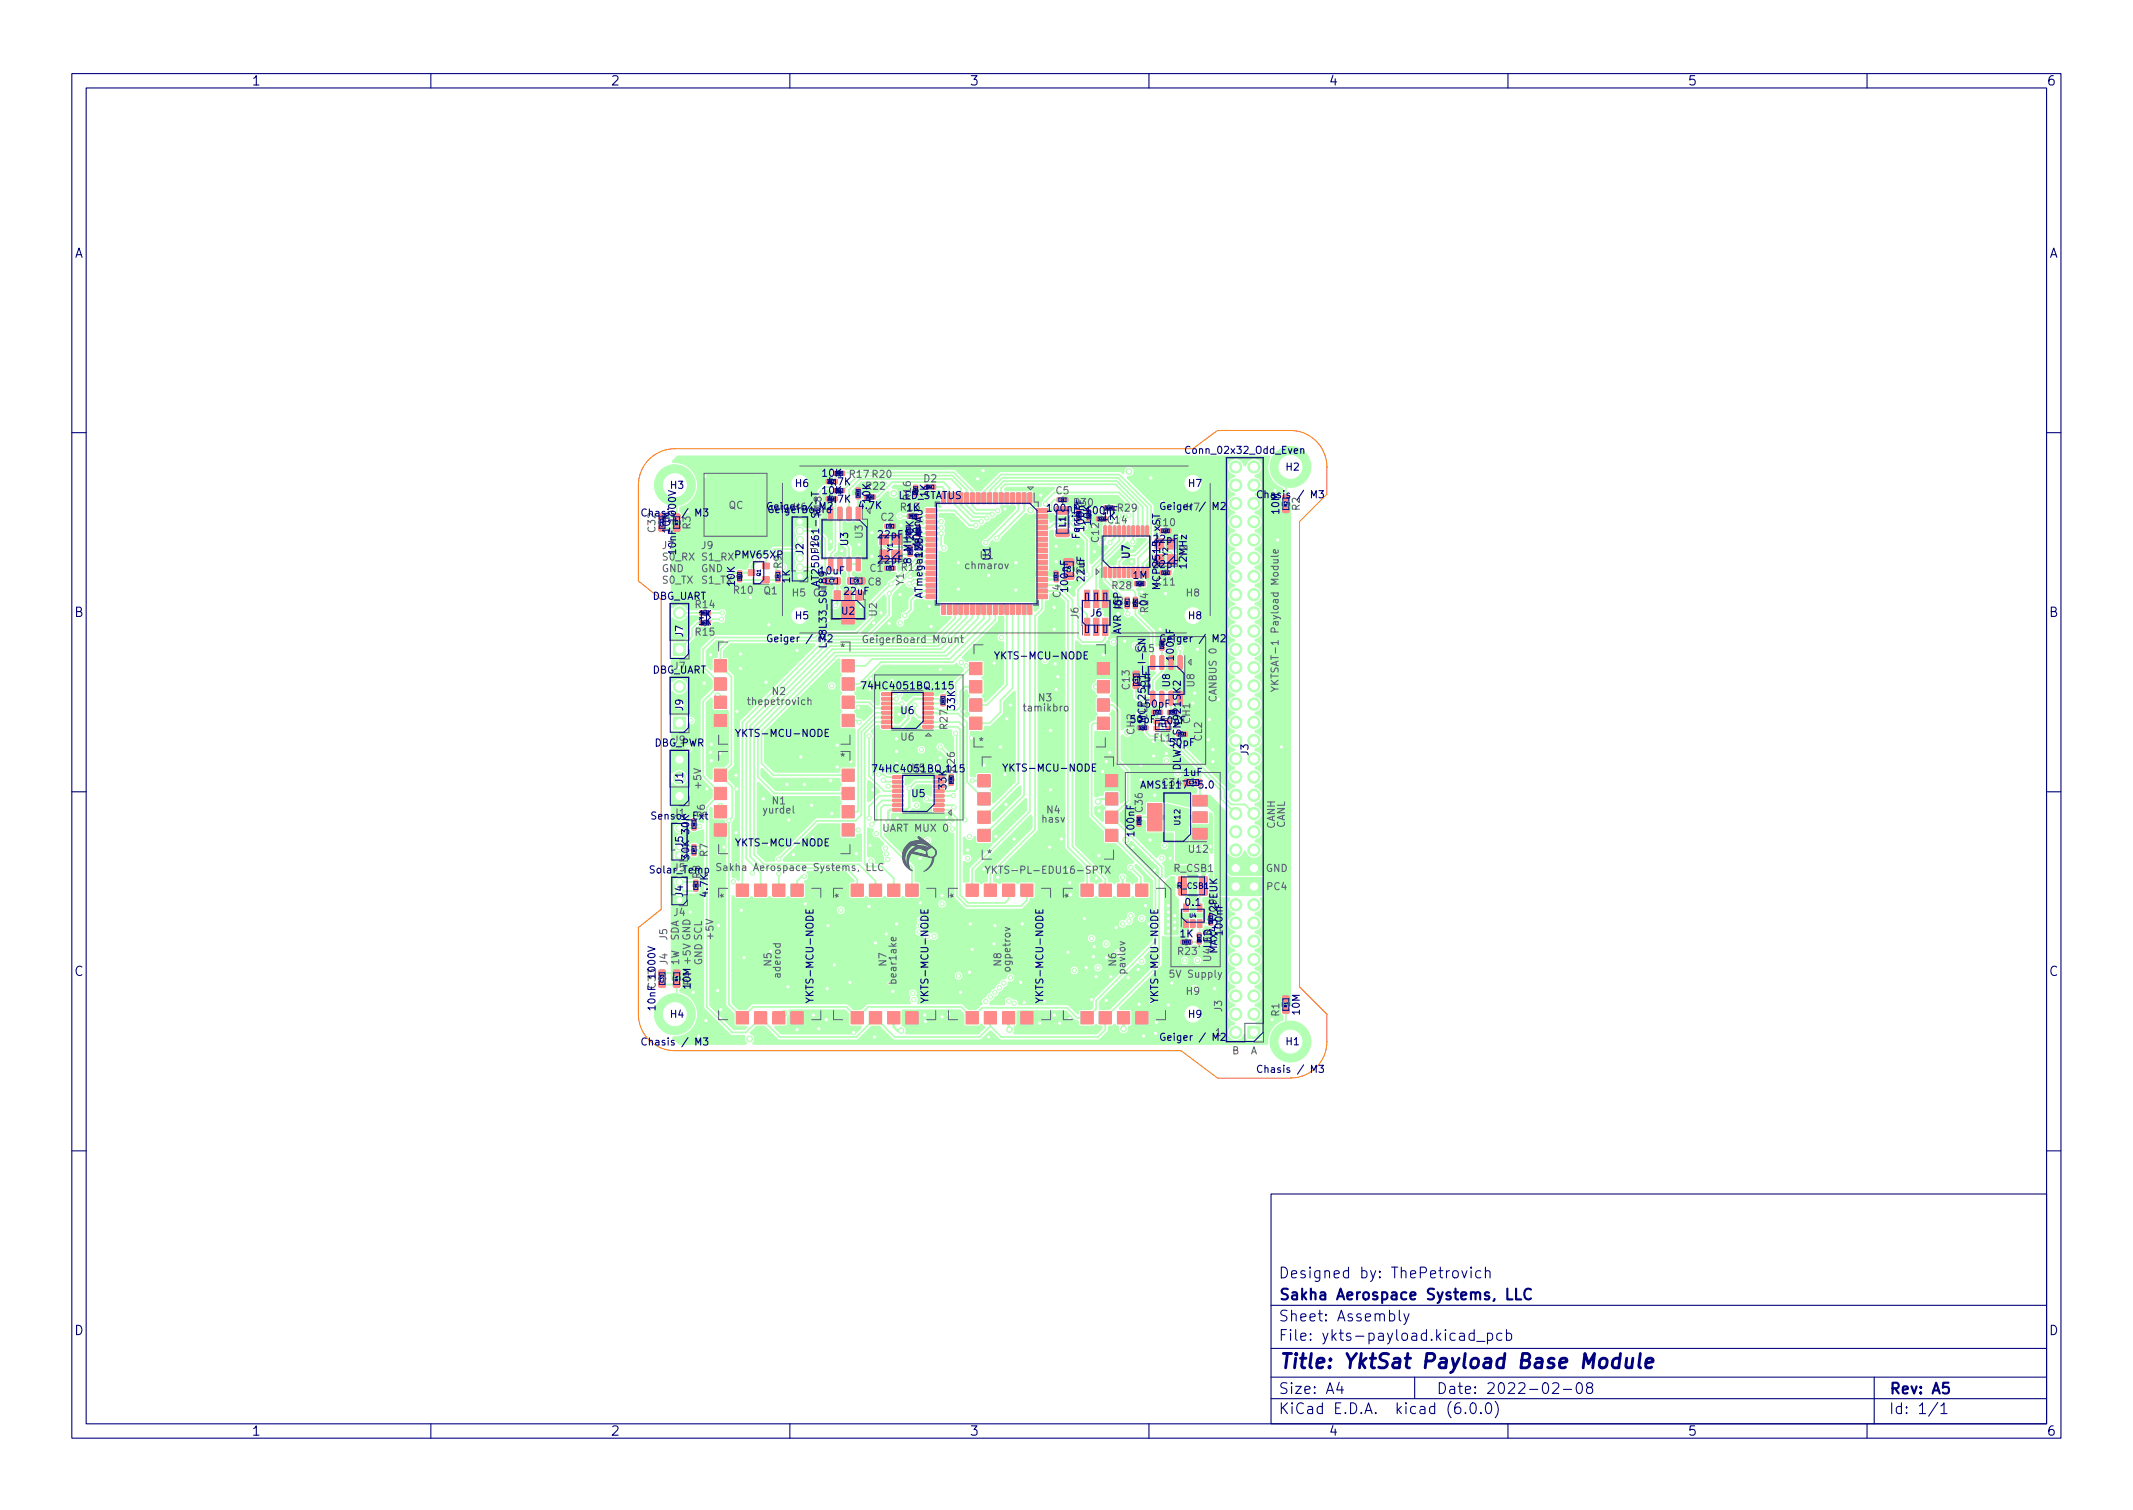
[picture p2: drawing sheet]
<svg xmlns="http://www.w3.org/2000/svg" width="297mm" height="210mm" viewBox="0 0 297 210" stroke-linecap="round" stroke-linejoin="round" font-family="sans-serif">
<defs><g id="words">
<text font-size="2.8" fill="#000080" x="178" y="190.6">Title: YktSat Payload Base Module</text>
<g font-size="2.1" fill="#000080">
<text x="178" y="178">Designed by: ThePetrovich</text>
<text x="178" y="184">Sheet: Assembly</text>
<text x="178" y="181">Sakha Aerospace Systems, LLC</text>
<text x="178" y="186.7">File: ykts-payload.kicad_pcb</text>
<text x="178" y="196.9">KiCad E.D.A. kicad (6.0.0)</text>
<text x="178" y="194.1">Size: A4</text>
<text x="200" y="194.1">Date: 2022-02-08</text>
<text x="263" y="194.1">Rev: A5</text>
<text x="263" y="196.9">Id: 1/1</text>
</g>
<g font-size="1.8" fill="#000080">
<text x="35" y="11.9">1</text>
<text x="85" y="11.9">2</text>
<text x="135" y="11.9">3</text>
<text x="185" y="11.9">4</text>
<text x="235" y="11.9">5</text>
<text x="285" y="11.9">6</text>
<text x="10.3" y="35.9">A</text>
<text x="285.3" y="35.9">A</text>
<text x="10.3" y="85.9">B</text>
<text x="285.3" y="85.9">B</text>
<text x="10.3" y="135.9">C</text>
<text x="285.3" y="135.9">C</text>
<text x="10.3" y="185.9">D</text>
<text x="285.3" y="185.9">D</text>
<text x="35" y="199.9">1</text>
<text x="85" y="199.9">2</text>
<text x="135" y="199.9">3</text>
<text x="185" y="199.9">4</text>
<text x="235" y="199.9">5</text>
<text x="285" y="199.9">6</text>
</g>
<g font-size="1.4" fill="#000080">
<text x="165.4" y="63.2">Conn_02x32_Odd_Even</text>
<text x="179.1" y="65.5">H2</text>
<text x="90.1" y="71.9">Chasis / M3</text>
<text x="93.4" y="68.1">H3</text>
<text x="107.2" y="71.4">GeigerBoard</text>
<text x="107.6" y="71">Geiger / M2</text>
<text x="110.5" y="71.1">H6</text>
<text x="110.8" y="67.8">H6</text>
<text x="114.4" y="71.8" transform="rotate(-90 114.4 71.8)">R18</text>
<text x="114.5" y="68.8">10K</text>
<text x="114.5" y="66.4">10K</text>
<text x="115.4" y="70">4.7K</text>
<text x="115.4" y="67.6">4.7K</text>
<text x="119.7" y="70.9">4.7K</text>
<text x="120.6" y="68.2">R22</text>
<text x="121.2" y="70" transform="rotate(-90 121.2 70)">10K</text>
<text x="125" y="69.5">LED_STATUS</text>
<text x="126.2" y="71.2">1K</text>
<text x="126.8" y="69.6" transform="rotate(-90 126.8 69.6)">R16</text>
<text x="128.6" y="67.1">D2</text>
<text x="129.2" y="69.2" transform="rotate(-90 129.2 69.2)">1K</text>
<text x="145.9" y="71.3">100nF</text>
<text x="149.6" y="70.5">R30</text>
<text x="151.4" y="71.6">100nF</text>
<text x="162.4" y="71">Geiger / M2</text>
<text x="165.2" y="71.1">H7</text>
<text x="165.5" y="67.8">H7</text>
<text x="175.9" y="69.4">Chasis / M3</text>
<text x="178.1" y="71.5" transform="rotate(-90 178.1 71.5)">10M</text>
<text x="91.3" y="74" transform="rotate(-90 91.3 74)">C32</text>
<text x="93.3" y="74.1" transform="rotate(-90 93.3 74.1)">10M</text>
<text x="94.1" y="76.6" transform="rotate(-90 94.1 76.6)">10nF 1000V</text>
<text x="111.9" y="77.2" transform="rotate(-90 111.9 77.2)">J2</text>
<text x="113.9" y="76.8" transform="rotate(-90 113.9 76.8)">J2</text>
<text x="118.1" y="75.9" transform="rotate(-90 118.1 75.9)">U3</text>
<text x="122.3" y="74.9">22pF</text>
<text x="127.2" y="75.2" transform="rotate(-90 127.2 75.2)">20K</text>
<text x="128.4" y="77.7" transform="rotate(-90 128.4 77.7)">1M100nF</text>
<text x="128.5" y="77.6" transform="rotate(-90 128.5 77.6)">R11</text>
<text x="137.9" y="78" transform="rotate(-90 137.9 78)">U1</text>
<text x="148.5" y="73.5" transform="rotate(-90 148.5 73.5)">L1</text>
<text x="150.4" y="74.8" transform="rotate(-90 150.4 74.8)">Ferrite</text>
<text x="151" y="73.8" transform="rotate(-90 151 73.8)">100nF</text>
<text x="151.9" y="73" transform="rotate(-90 151.9 73)">10K</text>
<text x="153.5" y="72.4">1K</text>
<text x="157.2" y="77.7" transform="rotate(-90 157.2 77.7)">U7</text>
<text x="160.7" y="75.6">22pF</text>
<text x="161" y="73.2">C10</text>
<text x="165.3" y="77.6" transform="rotate(-90 165.3 77.6)">Y2</text>
<text x="90.7" y="83.5">DBG_UART</text>
<text x="92.1" y="78">S0_RX</text>
<text x="97.5" y="78">S1_RX PMV65XP</text>
<text x="102.3" y="81.5" transform="rotate(-90 102.3 81.5)">10K</text>
<text x="110" y="81.1" transform="rotate(-90 110 81.1)">1K</text>
<text x="113.3" y="83">C7</text>
<text x="114.1" y="80.6" transform="rotate(-90 114.1 80.6)">AT25DF161-SF-T</text>
<text x="114.2" y="80">10uF</text>
<text x="117.6" y="82.8">22uF</text>
<text x="122.3" y="78.5">22pF</text>
<text x="125.6" y="79.5">R12</text>
<text x="126.9" y="78.2" transform="rotate(-90 126.9 78.2)">8 MHz</text>
<text x="128.5" y="82.7" transform="rotate(-90 128.5 82.7)">ATmega128A-AU</text>
<text x="148.7" y="82.3" transform="rotate(-90 148.7 82.3)">100nF</text>
<text x="151" y="79.8" transform="rotate(-90 151 79.8)">C6</text>
<text x="151" y="80.9" transform="rotate(-90 151 80.9)">22uF</text>
<text x="157.8" y="80.6">1M</text>
<text x="160.7" y="79.1">22pF</text>
<text x="161.5" y="81.4" transform="rotate(-90 161.5 81.4)">MCP2515-xST</text>
<text x="165.3" y="79" transform="rotate(-90 165.3 79)">12MHz</text>
<text x="95.1" y="88.7" transform="rotate(-90 95.1 88.7)">J7</text>
<text x="97.3" y="86.1">1K</text>
<text x="107.6" y="89.4">Geiger / M2</text>
<text x="110.8" y="86.2">H5</text>
<text x="115.1" y="89.9" transform="rotate(-90 115.1 89.9)">L78L33_SOT89</text>
<text x="117.2" y="85.6">U2</text>
<text x="151.9" y="85.8">J6</text>
<text x="156.1" y="88.1" transform="rotate(-90 156.1 88.1)">AVR ISP</text>
<text x="156.3" y="84.3" transform="rotate(-90 156.3 84.3)">0</text>
<text x="159.8" y="84.3" transform="rotate(-90 159.8 84.3)">0</text>
<text x="162.4" y="89.4">Geiger / M2</text>
<text x="165.5" y="86.2">H8</text>
<text x="90.7" y="93.8">DBG_UART</text>
<text x="93.8" y="93.2">J7</text>
<text x="120.6" y="96">74HC4051BQ,115</text>
<text x="139.1" y="91.8">YKTS-MCU-NODE</text>
<text x="158.1" y="90.8">C15</text>
<text x="160.2" y="95.9" transform="rotate(-90 160.2 95.9)">1uF</text>
<text x="162.9" y="95.6" transform="rotate(-90 162.9 95.6)">U8</text>
<text x="163.5" y="91.8" transform="rotate(-90 163.5 91.8)">100nF</text>
<text x="95.1" y="98.9" transform="rotate(-90 95.1 98.9)">J9</text>
<text x="125.5" y="99.4">U6</text>
<text x="133" y="98.8" transform="rotate(-90 133 98.8)">33K</text>
<text x="157.5" y="100.7">50pF 50pF</text>
<text x="159.5" y="99.5" transform="rotate(-90 159.5 99.5)">MCP2551-I-SN</text>
<text x="159.5" y="98.5">50pF</text>
<text x="159.8" y="100.2" transform="rotate(-90 159.8 100.2)">CL1</text>
<text x="165.7" y="100.7" transform="rotate(-90 165.7 100.7)">CH1</text>
<text x="91.1" y="103.9">DBG_PWR</text>
<text x="93.8" y="103.5">J9</text>
<text x="103" y="102.6">YKTS-MCU-NODE</text>
<text x="122.2" y="107.5">74HC4051BQ,115</text>
<text x="127" y="107.4">U5</text>
<text x="133" y="107.3" transform="rotate(-90 133 107.3)">R26</text>
<text x="140.3" y="107.4">YKTS-MCU-NODE</text>
<text x="158" y="102.2" transform="rotate(-90 158 102.2)">CH2</text>
<text x="163" y="103.9">50pF</text>
<text x="164.4" y="106.8" transform="rotate(-90 164.4 106.8)">DLW21SN921SK2</text>
<text x="173.9" y="105.2" transform="rotate(-90 173.9 105.2)">J3</text>
<text x="93.8" y="113.7">J1</text>
<text x="95.1" y="109.1" transform="rotate(-90 95.1 109.1)">J1</text>
<text x="98.2" y="113.8" transform="rotate(-90 98.2 113.8)">R6</text>
<text x="127" y="111">U5</text>
<text x="131.8" y="109.9" transform="rotate(-90 131.8 109.9)">33K</text>
<text x="159.7" y="109.8">AMS1117-5.0</text>
<text x="161.9" y="109.5">C34</text>
<text x="164.9" y="108">1uF</text>
<text x="90.8" y="114.1">Sensor_Ext</text>
<text x="95.1" y="118" transform="rotate(-90 95.1 118)">J5</text>
<text x="96" y="119.6" transform="rotate(-90 96 119.6)">30K</text>
<text x="96" y="116.1" transform="rotate(-90 96 116.1)">30K</text>
<text x="103" y="117.8">YKTS-MCU-NODE</text>
<text x="158" y="116.3" transform="rotate(-90 158 116.3)">100nF</text>
<text x="90.6" y="121.6">Solar_Temp</text>
<text x="93.8" y="121.3">J5</text>
<text x="95.1" y="124.8" transform="rotate(-90 95.1 124.8)">J4</text>
<text x="97.5" y="122.3" transform="rotate(-90 97.5 122.3)">R8</text>
<text x="98.6" y="124.8" transform="rotate(-90 98.6 124.8)">4.7K</text>
<text x="164.3" y="130.5">1K</text>
<text x="165.2" y="126.1">0.1</text>
<text x="168.8" y="131.3" transform="rotate(-90 168.8 131.3)">D3</text>
<text x="169.4" y="127" transform="rotate(-90 169.4 127)">C9</text>
<text x="170.3" y="130.1" transform="rotate(-90 170.3 130.1)">100nF</text>
<text x="91.3" y="137.5" transform="rotate(-90 91.3 137.5)">C33</text>
<text x="96.2" y="137.6" transform="rotate(-90 96.2 137.6)">10M +5V GND</text>
<text x="96.3" y="137.2" transform="rotate(-90 96.3 137.2)">R4</text>
<text x="168.6" y="133.9" transform="rotate(-90 168.6 133.9)">U4LED</text>
<text x="169.5" y="132.5" transform="rotate(-90 169.5 132.5)">MAX4372FEUK</text>
<text x="93.4" y="141.7">H4</text>
<text x="113.3" y="139" transform="rotate(-90 113.3 139)">YKTS-MCU-NODE</text>
<text x="129.3" y="139" transform="rotate(-90 129.3 139)">YKTS-MCU-NODE</text>
<text x="145.3" y="139" transform="rotate(-90 145.3 139)">YKTS-MCU-NODE</text>
<text x="161.3" y="139" transform="rotate(-90 161.3 139)">YKTS-MCU-NODE</text>
<text x="165.5" y="141.7">H9</text>
<text x="181" y="141.2" transform="rotate(-90 181 141.2)">10M</text>
<text x="90.1" y="145.6">Chasis / M3</text>
<text x="162.4" y="144.9">Geiger / M2</text>
<text x="175.9" y="149.4">Chasis / M3</text>
<text x="179.1" y="145.5">H1</text>
</g>
<g font-size="1.4" fill="#626262">
<text x="101.4" y="70.9">QC</text>
<text x="118.4" y="66.5">R17 R20</text>
<text x="125.5" y="71.1">R13</text>
<text x="147.1" y="68.8">C5</text>
<text x="155.7" y="71.2">R29</text>
<text x="181" y="71.1" transform="rotate(-90 181 71.1)">R2</text>
<text x="92.1" y="76.4">J7</text>
<text x="96.2" y="73.7" transform="rotate(-90 96.2 73.7)">R3</text>
<text x="97.5" y="76.4">J9</text>
<text x="120.1" y="74.9" transform="rotate(-90 120.1 74.9)">U3</text>
<text x="122.7" y="72.5">C2</text>
<text x="153" y="75.4" transform="rotate(-90 153 75.4)">C12</text>
<text x="154.3" y="72.9">C14</text>
<text x="92.1" y="79.7">GND</text>
<text x="92.1" y="81.3">S0_TX</text>
<text x="97.5" y="79.7">GND</text>
<text x="97.5" y="81.3">S1_TX</text>
<text x="102.2" y="82.7">R10</text>
<text x="106.4" y="82.8">Q1</text>
<text x="108.8" y="79.1" transform="rotate(-90 108.8 79.1)">R9</text>
<text x="110.4" y="83">H5</text>
<text x="120.9" y="81.5">C8</text>
<text x="121.2" y="79.6">C1</text>
<text x="125.8" y="81.5" transform="rotate(-90 125.8 81.5)">Y1</text>
<text x="134.5" y="79.2">chmarov</text>
<text x="147.7" y="83.2" transform="rotate(-90 147.7 83.2)">C4</text>
<text x="154.9" y="82">R28</text>
<text x="161" y="81.5">C11</text>
<text x="165.2" y="83">H8</text>
<text x="96.9" y="88.5">R15</text>
<text x="96.9" y="84.7">R14</text>
<text x="120.6" y="89.5">GeigerBoard Mount</text>
<text x="122.1" y="85.8" transform="rotate(-90 122.1 85.8)">U2</text>
<text x="150.2" y="86.1" transform="rotate(-90 150.2 86.1)">J6</text>
<text x="159.9" y="85.2" transform="rotate(-90 159.9 85.2)">R24</text>
<text x="117.1" y="90.7">*</text>
<text x="157.3" y="95.9" transform="rotate(-90 157.3 95.9)">C13</text>
<text x="166.3" y="95.6" transform="rotate(-90 166.3 95.6)">U8</text>
<text x="178" y="95.3" transform="rotate(-90 178 95.3)">YKTSAT-1 Payload Module</text>
<text x="104.4" y="98.2">thepetrovich</text>
<text x="107.6" y="96.8">N2</text>
<text x="131.9" y="101.5" transform="rotate(-90 131.9 101.5)">R27</text>
<text x="142.7" y="99">tamikbro</text>
<text x="144.7" y="97.6">N3</text>
<text x="169.4" y="97.5" transform="rotate(-90 169.4 97.5)">CANBUS 0</text>
<text x="117.1" y="105.9">*</text>
<text x="125.5" y="103.1">U6</text>
<text x="136.4" y="103.7">*</text>
<text x="160.7" y="103.2">FL1</text>
<text x="167.4" y="103.2" transform="rotate(-90 167.4 103.2)">CL2</text>
<text x="97.7" y="109.7" transform="rotate(-90 97.7 109.7)">+5V</text>
<text x="106.4" y="113.3">yurdel</text>
<text x="107.6" y="112">N1</text>
<text x="145.8" y="113.3">N4</text>
<text x="159.1" y="113" transform="rotate(-90 159.1 113)">C36</text>
<text x="98.5" y="119.2" transform="rotate(-90 98.5 119.2)">R7</text>
<text x="123.3" y="115.8">UART MUX 0</text>
<text x="137.5" y="119.4">*</text>
<text x="145.1" y="114.5">hasv</text>
<text x="165.6" y="118.7">U12</text>
<text x="177.5" y="115.4" transform="rotate(-90 177.5 115.4)">CANH</text>
<text x="178.9" y="115.3" transform="rotate(-90 178.9 115.3)">CANL</text>
<text x="100.8" y="121.3">Sakha Aerospace Systems, LLC</text>
<text x="101.3" y="125" transform="rotate(-90 101.3 125)">*</text>
<text x="117.3" y="125" transform="rotate(-90 117.3 125)">*</text>
<text x="133.3" y="125" transform="rotate(-90 133.3 125)">*</text>
<text x="138.4" y="121.7">YKTS-PL-EDU16-SPTX</text>
<text x="149.3" y="125" transform="rotate(-90 149.3 125)">*</text>
<text x="163.5" y="121.4">R_CSB1</text>
<text x="176.3" y="121.4">GND</text>
<text x="176.4" y="123.9">PC4</text>
<text x="92.9" y="131.1" transform="rotate(-90 92.9 131.1)">J5</text>
<text x="93.8" y="127.5">J4</text>
<text x="94.5" y="131.1" transform="rotate(-90 94.5 131.1)">SDA</text>
<text x="99.4" y="131.1" transform="rotate(-90 99.4 131.1)">+5V</text>
<text x="93" y="134.5" transform="rotate(-90 93 134.5)">J4</text>
<text x="94.6" y="134.5" transform="rotate(-90 94.6 134.5)">1W</text>
<text x="97.8" y="134.5" transform="rotate(-90 97.8 134.5)">GND SCL</text>
<text x="107.4" y="134.5" transform="rotate(-90 107.4 134.5)">N5</text>
<text x="108.7" y="136" transform="rotate(-90 108.7 136)">aderod</text>
<text x="123.4" y="134.5" transform="rotate(-90 123.4 134.5)">N7</text>
<text x="124.8" y="136.7" transform="rotate(-90 124.8 136.7)">bear1ake</text>
<text x="139.4" y="134.5" transform="rotate(-90 139.4 134.5)">N8</text>
<text x="140.7" y="135.2" transform="rotate(-90 140.7 135.2)">ogpetrov</text>
<text x="155.4" y="134.5" transform="rotate(-90 155.4 134.5)">N6</text>
<text x="156.7" y="135.6" transform="rotate(-90 156.7 135.6)">pavlov</text>
<text x="163.1" y="136.1">5V Supply</text>
<text x="164.1" y="133">R23</text>
<text x="165.2" y="138.5">H9</text>
<text x="170.2" y="140.8" transform="rotate(-90 170.2 140.8)">J3</text>
<text x="178.1" y="141.5" transform="rotate(-90 178.1 141.5)">R1</text>
<text x="169.3" y="144.3">1</text>
<text x="171.6" y="146.8">B</text>
<text x="174.1" y="146.8">A</text>
</g>
<g font-size="1.1" fill="#000080">
<text x="164.4" y="114.8" transform="rotate(-90 164.4 114.8)">U12</text>
<text x="163.9" y="123.8">R_CSB1</text>
</g>
<g font-size="1" fill="#000080">
<text x="124.3" y="76.8" transform="rotate(-90 124.3 76.8)">Y1</text>
<text x="162.7" y="77.4" transform="rotate(-90 162.7 77.4)">Y2</text>
</g>
<g font-size=".7" fill="#000080">
<text x="105.9" y="80.2" transform="rotate(-90 105.9 80.2)">Q1</text>
<text x="149.1" y="79.7" transform="rotate(-90 149.1 79.7)">C6</text>
<text x="161.3" y="101.2">FL1</text>
<text x="165.7" y="127.8">U4</text>
</g>
<g font-size=".6" fill="#000080">
<text x="179.3" y="70.5" transform="rotate(-90 179.3 70.5)">R2</text>
<text x="92.4" y="73.3" transform="rotate(-90 92.4 73.3)">C32</text>
<text x="94.4" y="73.1" transform="rotate(-90 94.4 73.1)">R3</text>
<text x="115.5" y="81.1">C7</text>
<text x="118.9" y="81.1">C8</text>
<text x="158.4" y="95.2" transform="rotate(-90 158.4 95.2)">C13</text>
<text x="165.6" y="109.2">C34</text>
<text x="92.4" y="136.8" transform="rotate(-90 92.4 136.8)">C33</text>
<text x="94.4" y="136.6" transform="rotate(-90 94.4 136.6)">R4</text>
<text x="179.3" y="140.2" transform="rotate(-90 179.3 140.2)">R1</text>
</g>
<g font-size=".4" fill="#000080">
<text x="115.5" y="69.6">R18</text>
<text x="115.5" y="67.2">R17</text>
<text x="116.5" y="68.5">R21</text>
<text x="116.5" y="66">R20</text>
<text x="119.6" y="69" transform="rotate(-90 119.6 69)">R19</text>
<text x="120.8" y="69.3">R22</text>
<text x="127.6" y="68.7" transform="rotate(-90 127.6 68.7)">R16</text>
<text x="154.1" y="70.9">R29</text>
<text x="126.8" y="72">R13</text>
<text x="126.9" y="77" transform="rotate(-90 126.9 77)">R12</text>
<text x="128" y="74.2" transform="rotate(-90 128 74.2)">R11</text>
<text x="150.4" y="72.1" transform="rotate(-90 150.4 72.1)">R30</text>
<text x="103.1" y="80.6" transform="rotate(-90 103.1 80.6)">R10</text>
<text x="108.5" y="80.5" transform="rotate(-90 108.5 80.5)">R9</text>
<text x="158.4" y="81.4">R28</text>
<text x="97.8" y="86.9">R15</text>
<text x="97.8" y="85.5">R14</text>
<text x="157.1" y="84.2" transform="rotate(-90 157.1 84.2)">R5</text>
<text x="158.2" y="84.3" transform="rotate(-90 158.2 84.3)">R24</text>
<text x="131.4" y="97.9" transform="rotate(-90 131.4 97.9)">R27</text>
<text x="132.6" y="108.9" transform="rotate(-90 132.6 108.9)">R26</text>
<text x="96.8" y="118.6" transform="rotate(-90 96.8 118.6)">R7</text>
<text x="96.8" y="115" transform="rotate(-90 96.8 115)">R6</text>
<text x="97" y="123.5" transform="rotate(-90 97 123.5)">R8</text>
<text x="164.9" y="131.3">R23</text>
</g>
<g font-size=".3" fill="#000080">
<text x="129.3" y="67.9">D2</text>
<text x="147.7" y="69.7">C5</text>
<text x="123.7" y="73.4">C2</text>
<text x="126.6" y="74.1" transform="rotate(-90 126.6 74.1)">C3</text>
<text x="151.8" y="72.1" transform="rotate(-90 151.8 72.1)">C14</text>
<text x="153.1" y="72.4">C12</text>
<text x="162" y="74">C10</text>
<text x="123.7" y="79.2">C1</text>
<text x="147.2" y="80.5" transform="rotate(-90 147.2 80.5)">C4</text>
<text x="162" y="79.9">C11</text>
<text x="161.9" y="90.1" transform="rotate(-90 161.9 90.1)">C15</text>
<text x="158.8" y="101.5">CH2</text>
<text x="160.8" y="99.3">CL1</text>
<text x="163" y="99.3">CH1</text>
<text x="164.3" y="102.4">CL2</text>
<text x="158.7" y="114.6" transform="rotate(-90 158.7 114.6)">C36</text>
<text x="167.1" y="130.9" transform="rotate(-90 167.1 130.9)">D3</text>
<text x="168.7" y="128.3" transform="rotate(-90 168.7 128.3)">C9</text>
</g>
</g></defs>
<g fill="#b3ffb3" stroke="#b3ffb3" stroke-width=".14">
<path d="M128.5 101h1.4l.1 .3-1.4 .1z"/>
<path d="M128.5 100.4h1.4l.1 .3h-1.4z"/>
<path d="M128.5 99.7h1.4l.1 .3-1.4 .1z"/>
<path d="M128.5 99.1h1.4l.1 .3h-1.4z"/>
<path d="M128.5 98.4h1.4l.1 .3-1.4 .1z"/>
<path d="M128.5 97.8h1.4l.1 .3h-1.4z"/>
<path d="M128.5 97.1h1.4l.1 .3-1.4 .1z"/>
<path d="M128.5 96.5h1.4l.1 .3h-1.4z"/>
<path d="M122.8 96.5h1.4v.3h-1.4z"/>
<path d="M122.8 97.1h1.4v.3l-1.4 .1z"/>
<path d="M122.8 97.8h1.4v.3h-1.4z"/>
<path d="M122.8 98.4h1.4v.3l-1.4 .1z"/>
<path d="M122.8 99.1h1.4v.3h-1.4z"/>
<path d="M122.8 99.7h1.4v.3l-1.4 .1z"/>
<path d="M122.8 100.4h1.4v.3h-1.4z"/>
<path d="M122.8 101h1.4v.3l-1.4 .1z"/>
<path d="M130 112.6h1.4l.1 .3-1.4 .1z"/>
<path d="M130 111.9h1.4l.1 .3-1.4 .1z"/>
<path d="M130 111.3h1.4l.1 .3-1.4 .1z"/>
<path d="M130 110.6h1.4l.1 .3-1.4 .1z"/>
<path d="M130 110h1.4l.1 .3-1.4 .1z"/>
<path d="M130 109.3h1.4l.1 .3-1.4 .1z"/>
<path d="M130 108.7h1.4l.1 .3-1.4 .1z"/>
<path d="M130 108h1.4l.1 .3-1.4 .1z"/>
<path d="M124.3 108h1.4l.1 .3-1.4 .1z"/>
<path d="M124.3 108.7h1.4l.1 .3-1.4 .1z"/>
<path d="M124.3 109.3h1.4l.1 .3-1.4 .1z"/>
<path d="M124.3 110h1.4l.1 .3-1.4 .1z"/>
<path d="M124.3 110.6h1.4l.1 .3-1.4 .1z"/>
<path d="M124.3 111.3h1.4l.1 .3-1.4 .1z"/>
<path d="M124.3 111.9h1.4l.1 .3-1.4 .1z"/>
<path d="M124.3 112.6h1.4l.1 .3-1.4 .1z"/>
<path d="M119.3 70.6h.4l.1 .1v1.7l-.1 .1-.5-.1z"/>
<path d="M118 70.6h.4l.1 .1v1.7l-.1 .1-.5-.1z"/>
<path d="M116.7 70.6h.4l.2 .1v1.7l-.1 .1-.5-.1z"/>
<path d="M115.4 70.6h.4l.2 .1v1.7l-.1 .1-.5-.1z"/>
<path d="M115.4 77.6h.4l.2 .1v1.7l-.1 .1-.5-.1z"/>
<path d="M116.7 77.6h.4l.2 .1v1.7l-.1 .1-.5-.1z"/>
<path d="M118 77.6h.4l.1 .1v1.7l-.1 .1-.5-.1z"/>
<path d="M119.3 77.6h.4l.1 .1v1.7l-.1 .1-.5-.1z"/>
<path d="M119.2 82.3h.9v1.3h-.9z"/>
<path d="M116.2 82.3h.9v1.3h-.9z"/>
<path d="M117.7 82.3h.9v1.5h.4v3.1h-1.8v-3.1h.5z"/>
<path d="M131 97.8h.6v.5h-.6z"/>
<path d="M131 96.8h.6v.5h-.6z"/>
<path d="M132.2 107.8h.5v.5h-.5z"/>
<path d="M132.2 108.9h.5v.4h-.5z"/>
<path d="M121.4 68.9h.5v.6h-.5z"/>
<path d="M117.1 68h.5v.6h-.5z"/>
<path d="M117.1 65.6h.5v.6h-.5z"/>
<path d="M119.2 69h.6v.4h-.6z"/>
<path d="M119.2 68h.6v.4h-.6z"/>
<path d="M118.1 80.5h.7v.8h-.7z"/>
<path d="M119.6 80.5h.8v.8h-.8z"/>
<path d="M116.2 80.5h.8v.8h-.8z"/>
<path d="M173.8 142.9h1.7v1.7h-1.7z"/>
<path d="M93.8 89.6h1.7v1.7h-1.7z"/>
<path d="M146.8 80.5h.5v.5h-.5z"/>
<path d="M146.8 79.5h.5v.5h-.5z"/>
<path d="M162.5 79.5h.5v.5h-.5z"/>
<path d="M161.6 79.5h.5v.5h-.5z"/>
<path d="M157.8 95h.9v.8h-.9z"/>
<path d="M157.8 93.5h.9v.8h-.9z"/>
<path d="M162.6 98.9h.5v.6h-.5z"/>
<path d="M161.4 98.9h.5v.6h-.5z"/>
<path d="M160.4 98.9h.5v.6h-.5z"/>
<path d="M160.7 101.1h.8v.5h-.8z"/>
<path d="M162.4 101.1h.7v.5h-.7z"/>
<path d="M161.5 90h.6v.5h-.6z"/>
<path d="M161.5 89.1h.6v.4h-.6z"/>
<path d="M110.9 79.8h1v1h-1z"/>
<path d="M94.1 118.6h1v1h-1z"/>
<path d="M147.1 73.8l1.7-.1 .1 .2v.7l-.2 .1h-1.5l-.2-.2z"/>
<path d="M126.4 71.6h.4v.6h-.4z"/>
<path d="M127.2 67.6h.6v.4h-.6z"/>
<path d="M159 81h.5v.6h-.5z"/>
<path d="M158 81h.5v.6h-.5z"/>
<path d="M123.2 73h.5v.5h-.5z"/>
<path d="M124.2 73h.5v.5h-.5z"/>
<path d="M147.2 69.3h.5v.6h-.5z"/>
<path d="M148.2 69.3h.5v.6h-.5z"/>
<path d="M148.2 79.8l1.2-.1 .2 .2-.1 .6-.2 .2h-1l-.2-.3z"/>
<path d="M148.2 77.9l1.2-.1 .2 .2-.1 .6-.2 .2h-1l-.2-.3z"/>
<path d="M161.6 73.6h.5v.6h-.5z"/>
<path d="M162.5 73.6h.5v.6h-.5z"/>
<path d="M152.7 72h.5v.5h-.5z"/>
<path d="M159.4 101.1h.5v.5h-.5z"/>
<path d="M158.4 101.1h.5v.5h-.5z"/>
<path d="M164.8 102h.5v.5h-.5z"/>
<path d="M129.8 67.5h.5v.6h-.5z"/>
<path d="M144.4 70.8h1.5v.6h-1.5z"/>
<path d="M144.4 71.6h1.5v.6h-1.5z"/>
<path d="M144.4 72.4h1.5v.6h-1.5z"/>
<path d="M144.4 73.2h1.5v.6h-1.5z"/>
<path d="M144.4 74h1.5v.6h-1.5z"/>
<path d="M144.4 74.8h1.5v.6h-1.5z"/>
<path d="M144.4 75.6h1.5v.6h-1.5z"/>
<path d="M144.4 76.4h1.5v.6h-1.5z"/>
<path d="M144.4 77.2h1.5v.6h-1.5z"/>
<path d="M144.4 78h1.5v.6h-1.5z"/>
<path d="M144.4 78.8h1.5v.6h-1.5z"/>
<path d="M144.4 79.6h1.5v.6h-1.5z"/>
<path d="M144.4 80.4h1.5v.6h-1.5z"/>
<path d="M144.4 81.2h1.5v.6h-1.5z"/>
<path d="M144.4 82h1.5v.6h-1.5z"/>
<path d="M144.4 82.8h1.5v.6h-1.5z"/>
<path d="M143.1 84h.6v1.5h-.6z"/>
<path d="M142.3 84h.6v1.5h-.6z"/>
<path d="M141.5 84h.6v1.5h-.6z"/>
<path d="M140.7 84h.6v1.5h-.6z"/>
<path d="M139.9 84h.6v1.5h-.6z"/>
<path d="M139.1 84h.6v1.5h-.6z"/>
<path d="M138.3 84h.6v1.5h-.6z"/>
<path d="M137.5 84h.6v1.5h-.6z"/>
<path d="M136.7 84h.6v1.5h-.6z"/>
<path d="M135.9 84h.6v1.5h-.6z"/>
<path d="M135.1 84h.6v1.5h-.6z"/>
<path d="M134.3 84h.6v1.5h-.6z"/>
<path d="M133.5 84h.6v1.5h-.6z"/>
<path d="M132.7 84h.6v1.5h-.6z"/>
<path d="M131.9 84h.6v1.5h-.6z"/>
<path d="M131.1 84h.6v1.5h-.6z"/>
<path d="M129 82.8h1.5v.6h-1.5z"/>
<path d="M129 82h1.5v.6h-1.5z"/>
<path d="M129 81.2h1.5v.6h-1.5z"/>
<path d="M129 80.4h1.5v.6h-1.5z"/>
<path d="M129 79.6h1.5v.6h-1.5z"/>
<path d="M129 78.8h1.5v.6h-1.5z"/>
<path d="M129 78h1.5v.6h-1.5z"/>
<path d="M129 77.2h1.5v.6h-1.5z"/>
<path d="M129 76.4h1.5v.6h-1.5z"/>
<path d="M129 75.6h1.5v.6h-1.5z"/>
<path d="M129 74.8h1.5v.6h-1.5z"/>
<path d="M129 74h1.5v.6h-1.5z"/>
<path d="M129 73.2h1.5v.6h-1.5z"/>
<path d="M129 72.4h1.5v.6h-1.5z"/>
<path d="M129 71.6h1.5v.6h-1.5z"/>
<path d="M129 70.8h1.5v.6h-1.5z"/>
<path d="M134.3 68.6h.6v1.5h-.6z"/>
<path d="M135.1 68.6h.6v1.5h-.6z"/>
<path d="M135.9 68.6h.6v1.5h-.6z"/>
<path d="M136.7 68.6h.6v1.5h-.6z"/>
<path d="M137.5 68.6h.6v1.5h-.6z"/>
<path d="M138.3 68.6h.6v1.5h-.6z"/>
<path d="M139.1 68.6h.6v1.5h-.6z"/>
<path d="M139.9 68.6h.6v1.5h-.6z"/>
<path d="M140.7 68.6h.6v1.5h-.6z"/>
<path d="M141.5 68.6h.6v1.5h-.6z"/>
<path d="M142.3 68.6h.6v1.5h-.6z"/>
<path d="M143.1 68.6h.6v1.5h-.6z"/>
<path d="M162.6 77.2h1.2v1.4h-1.2z"/>
<path d="M162.6 75h1.2v1.4h-1.2z"/>
<path d="M117.3 107.1h1.7v1.7h-1.7z"/>
<path d="M117.3 109.6h1.7v1.7h-1.7z"/>
<path d="M117.3 112.2h1.7v1.7h-1.7z"/>
<path d="M117.3 114.7h1.7v1.7h-1.7z"/>
<path d="M99.5 107.1h1.7v1.7h-1.7z"/>
<path d="M99.5 109.6h1.7v1.7h-1.7z"/>
<path d="M99.5 112.2h1.7v1.7h-1.7z"/>
<path d="M99.5 114.7h1.7v1.7h-1.7z"/>
<path d="M117.3 91.9h1.7v1.7h-1.7z"/>
<path d="M117.3 94.4h1.7v1.7h-1.7z"/>
<path d="M117.3 96.9h1.7v1.7h-1.7z"/>
<path d="M117.3 99.5h1.7v1.7h-1.7z"/>
<path d="M99.5 91.9h1.7v1.7h-1.7z"/>
<path d="M99.5 94.4h1.7v1.7h-1.7z"/>
<path d="M99.5 96.9h1.7v1.7h-1.7z"/>
<path d="M99.5 99.5h1.7v1.7h-1.7z"/>
<path d="M135 99.9h1.7v1.7h-1.7z"/>
<path d="M135 97.3h1.7v1.7h-1.7z"/>
<path d="M135 94.8h1.7v1.7h-1.7z"/>
<path d="M135 92.2h1.7v1.7h-1.7z"/>
<path d="M152.8 99.9h1.7v1.7h-1.7z"/>
<path d="M152.8 97.3h1.7v1.7h-1.7z"/>
<path d="M152.8 94.8h1.7v1.7h-1.7z"/>
<path d="M152.8 92.2h1.7v1.7h-1.7z"/>
<path d="M136.2 115.5h1.7v1.7h-1.7z"/>
<path d="M136.2 112.9h1.7v1.7h-1.7z"/>
<path d="M136.2 110.4h1.7v1.7h-1.7z"/>
<path d="M136.2 107.9h1.7v1.7h-1.7z"/>
<path d="M154 115.5h1.7v1.7h-1.7z"/>
<path d="M154 112.9h1.7v1.7h-1.7z"/>
<path d="M154 110.4h1.7v1.7h-1.7z"/>
<path d="M154 107.9h1.7v1.7h-1.7z"/>
<path d="M102.5 123.1h1.7v1.7h-1.7z"/>
<path d="M105.1 123.1h1.7v1.7h-1.7z"/>
<path d="M107.6 123.1h1.7v1.7h-1.7z"/>
<path d="M110.1 123.1h1.7v1.7h-1.7z"/>
<path d="M102.5 140.9h1.7v1.7h-1.7z"/>
<path d="M105.1 140.9h1.7v1.7h-1.7z"/>
<path d="M107.6 140.9h1.7v1.7h-1.7z"/>
<path d="M110.1 140.9h1.7v1.7h-1.7z"/>
<path d="M150.5 123.1h1.7v1.7h-1.7z"/>
<path d="M153.1 123.1h1.7v1.7h-1.7z"/>
<path d="M155.6 123.1h1.7v1.7h-1.7z"/>
<path d="M158.2 123.1h1.7v1.7h-1.7z"/>
<path d="M150.5 140.9h1.7v1.7h-1.7z"/>
<path d="M153.1 140.9h1.7v1.7h-1.7z"/>
<path d="M155.6 140.9h1.7v1.7h-1.7z"/>
<path d="M158.2 140.9h1.7v1.7h-1.7z"/>
<path d="M118.5 123.1h1.7v1.7h-1.7z"/>
<path d="M121.1 123.1h1.7v1.7h-1.7z"/>
<path d="M123.6 123.1h1.7v1.7h-1.7z"/>
<path d="M126.2 123.1h1.6v1.7h-1.6z"/>
<path d="M118.5 140.9h1.7v1.7h-1.7z"/>
<path d="M121.1 140.9h1.7v1.7h-1.7z"/>
<path d="M123.6 140.9h1.7v1.7h-1.7z"/>
<path d="M126.2 140.9h1.6v1.7h-1.6z"/>
<path d="M134.5 123.1h1.7v1.7h-1.7z"/>
<path d="M137.1 123.1h1.7v1.7h-1.7z"/>
<path d="M139.6 123.1h1.7v1.7h-1.7z"/>
<path d="M142.2 123.1h1.7v1.7h-1.7z"/>
<path d="M134.5 140.9h1.7v1.7h-1.7z"/>
<path d="M137.1 140.9h1.7v1.7h-1.7z"/>
<path d="M139.6 140.9h1.7v1.7h-1.7z"/>
<path d="M142.2 140.9h1.7v1.7h-1.7z"/>
<path d="M153.7 79h.4v1.4h-.4z"/>
<path d="M154.4 79h.4l-.1 1.4h-.3z"/>
<path d="M155 79h.4v1.4h-.4z"/>
<path d="M155.7 79h.4l-.1 1.4h-.3z"/>
<path d="M156.3 79h.4v1.4h-.4z"/>
<path d="M157 79h.4l-.1 1.4h-.3z"/>
<path d="M157.6 79h.4v1.4h-.4z"/>
<path d="M158.3 79h.4l-.1 1.4h-.3z"/>
<path d="M158.9 79h.4v1.4h-.4z"/>
<path d="M159.6 79h.4l-.1 1.4h-.3z"/>
<path d="M159.6 73.3h.4l-.1 1.4-.3-.1z"/>
<path d="M158.9 73.3h.4v1.4l-.4-.1z"/>
<path d="M158.3 73.3h.4l-.1 1.4-.3-.1z"/>
<path d="M157.6 73.3h.4v1.4l-.4-.1z"/>
<path d="M157 73.3h.4l-.1 1.4-.3-.1z"/>
<path d="M156.3 73.3h.4v1.4l-.4-.1z"/>
<path d="M155.7 73.3h.4l-.1 1.4-.3-.1z"/>
<path d="M155 73.3h.4v1.4l-.4-.1z"/>
<path d="M154.4 73.3h.4l-.1 1.4-.3-.1z"/>
<path d="M153.7 73.3h.4v1.4l-.4-.1z"/>
<path d="M164.1 91.3h.4l.1 .1v1.7l-.1 .1-.5-.1z"/>
<path d="M162.8 91.3h.4l.2 .1v1.7l-.1 .1-.5-.1z"/>
<path d="M161.5 91.3h.4l.2 .1v1.7l-.1 .1-.5-.1z"/>
<path d="M160.3 91.3h.4l.1 .1v1.7l-.1 .1-.5-.1z"/>
<path d="M160.3 96.3l.4-.1 .1 .1v1.7l-.1 .2-.5-.1z"/>
<path d="M161.5 96.3l.4-.1 .2 .1v1.7l-.1 .2-.5-.1z"/>
<path d="M162.8 96.3l.4-.1 .2 .1v1.7l-.1 .2-.5-.1z"/>
<path d="M124.2 78.8h.5v.6h-.5z"/>
<path d="M123.2 78.8h.5v.6h-.5z"/>
<path d="M151 86.1h.8v2.4h-.8z"/>
<path d="M151 82.2h.8v2.4h-.8z"/>
<path d="M152.3 86.1h.7v2.4h-.7z"/>
<path d="M152.3 82.2h.7v2.4h-.7z"/>
<path d="M153.6 86.1h.7v2.4h-.7z"/>
<path d="M153.6 82.2h.7v2.4h-.7z"/>
<path d="M106.2 80.3h.9v.8h-.9z"/>
<path d="M106.2 78.4h.9v.8h-.9z"/>
<path d="M104.2 79.4h.9v.8h-.9z"/>
<path d="M108.1 80.5h.5v.5h-.5z"/>
<path d="M108.1 79.5h.5v.5h-.5z"/>
<path d="M102.7 79.5h.6v.5h-.6z"/>
<path d="M102.7 80.5h.6v.5h-.6z"/>
<path d="M124.2 76.6h1.2v1.4h-1.2z"/>
<path d="M124.2 74.4h1.2v1.4h-1.2z"/>
<path d="M122.5 74.4h1.2v1.4h-1.2z"/>
<path d="M122.5 76.6h1.2v1.4h-1.2z"/>
<path d="M91.8 73.2h.8v.7h-.8z"/>
<path d="M91.8 71.6h.8v.8h-.8z"/>
<path d="M164.2 122.1l.8-.1 .2 .2v2.2l-.1 .3h-.8l-.2-.2z"/>
<path d="M167.1 122.1l.8-.1 .2 .2v2.2l-.1 .3h-.7l-.3-.2z"/>
<path d="M96.6 123.6h.6v.5h-.6z"/>
<path d="M96.6 122.6h.6v.4h-.6z"/>
<path d="M178.7 140.4h.8v.7h-.8z"/>
<path d="M178.7 138.7h.8v.7h-.8z"/>
<path d="M158.4 113.6h.5v.5h-.5z"/>
<path d="M158.4 114.5h.5v.5h-.5z"/>
<path d="M96.4 115.1h.5v.4h-.5z"/>
<path d="M93.8 73.2h.9v.7h-.9z"/>
<path d="M93.8 110h1.7v1.7h-1.7z"/>
<path d="M156.7 83.2h.6v.5h-.6z"/>
<path d="M156.7 84.2h.6v.5h-.6z"/>
<path d="M157.8 84.2h.6v.5h-.6z"/>
<path d="M157.8 83.2h.6v.5h-.6z"/>
<path d="M96.4 117.6h.5v.5h-.5z"/>
<path d="M96.4 118.6h.5v.5h-.5z"/>
<path d="M91.8 135.1h.8v.8h-.8z"/>
<path d="M91.8 136.7h.8v.7h-.8z"/>
<path d="M166.1 115.3h2v1.5h-2z"/>
<path d="M159.8 111.9h2v3.8h-2z"/>
<path d="M166.1 113h2v1.5h-2z"/>
<path d="M166.1 110.7h2v1.5h-2z"/>
<path d="M166.7 130.9h.6v.5h-.6z"/>
<path d="M166.7 129.9h.6v.5h-.6z"/>
<path d="M93.8 99.8h1.7v1.7h-1.7z"/>
<path d="M98.5 86.5h.4v.5h-.4z"/>
<path d="M97.4 86.5h.5v.5h-.5z"/>
<path d="M93.8 136.7h.9v.7h-.9z"/>
<path d="M93.8 135.1h.9v.7h-.9z"/>
<path d="M164.8 128.1h.7v1h-.7z"/>
<path d="M165.8 128.1h.6v1h-.6z"/>
<path d="M166.7 128.1h.7v1h-.7z"/>
<path d="M166.7 125.9h.7v1h-.7z"/>
<path d="M164.8 125.9h.7v1h-.7z"/>
<path d="M165.5 130.9h.5v.6h-.5z"/>
<path d="M164.5 130.9h.4v.6h-.4z"/>
<path d="M178.7 70.6h.8v.7h-.8z"/>
<path d="M94.1 124.8h1v1h-1z"/>
<path d="M166.8 110.8h1.7l2.1 2.1v8.8l.7 .5h4.4l.1 2.4-.1 .1h-5.7l-.8-.7v-10.7l-1.3-1.2h-1.1z"/>
<path d="M162.2 122.9l.8-.8 .5-.1 .1 .2v.9h.7v.5h-.7v1l.1 .3 .4 .3v4.8l-.1 .2h-1.7l-.1-.1z"/>
<path d="M93.7 64.2l.7-.7h82.3l.1 .1a3.3 3.3 0 0 0 1.8 4.4v.6l-.3 .4 .1 .8 .3 .2h.9l.1 .2v69.7l-.1 .1h-.2a.91 .91 0 0 0-1 .3l-.1 .7 .3 .5v.6a3.2 3.2 0 0 0-2.1 3.2l-.1 .1h-71.4l-.2-.1a.81 .81 0 0 0-.3-1.4v-.2l.9-.8h1l2.1 1.9h10.8l.2-.1 1.8-1.8h1.1l2.1 1.9h12l1.4-1.3 1.5 1.3h13.6l1.3-1.2 .1-.6 .6-.3a.21 .21 0 0 1 .3-.1 .21 .21 0 0 1 .1 .2l.4 .2v.4a.7 .7 0 0 0 .7 .6l.5-.3 .1-.3 .1-.5 .3-.1 .1-.2v-1.8l-.2-.2h-1.4l-.1-.1v-.1l2.7-2.7h7.2a.61 .61 0 0 0 .8 .5 .61 .61 0 0 0 .2-1 .61 .61 0 0 0-1 .3v.2h-7.2l3.2-3.2v-.8h2.6a.61 .61 0 0 0 .6 .6 .61 .61 0 0 0 .6-.6h.5a.6 .6 0 0 0 .9 .6 .6 .6 0 0 0 .1-1 .6 .6 0 0 0-.9 .3l-.1 .1h-.5a.61 .61 0 0 0-.6-.6 .61 .61 0 0 0-.6 .6h-2.6v-1.9h6.6a.61 .61 0 0 0 .9 .6 .61 .61 0 0 0 .1-1 .61 .61 0 0 0-.9 .3l-.1 .1h-6.6l.1-1.4h.1l.3 .1h1.7l.3-.2 .1-.4h.6l.1 .3 .3 .4-.2 .3v.7l.3 .2h.4a.59 .59 0 0 1 .9 0h.5l.3-.3v-.5l-.1-.3 .1-.7-.1-.5 .2-.4a.49 .49 0 0 1 .7 0 .5 .5 0 0 1 .5 .5 .62 .62 0 0 0 1-.3 .62 .62 0 0 0-.7-.8v-.3l-.4-.2h-.5l-.5 .1-.3-.3h-1.8l-.2 .2v1.3l-.4 .3-.1 .3h-.6v-2.7l.1-.1 .3 .1h.8l.2-.2v-1.2l-.2-.3-.1-3.3a.55 .55 0 0 0-.5-.5h-.8l-.3 .2-.3-.1-.5-.1-.8 .5-.1-.1v-1.4l-.3-.5 .1-.1a.61 .61 0 0 0 .2-1.1 .61 .61 0 0 0-1 .4h-.2l-1.6-1.7h2.2a.61 .61 0 0 0 .8 .6 .61 .61 0 0 0 .1-1 .61 .61 0 0 0-.9 .4h-2.2l-3.4-3.3v-1.1l1.5-1.6v-3.9h5.9a.61 .61 0 0 0 .9 .5 .61 .61 0 0 0 .1-1 .61 .61 0 0 0-1 .4l-5.9 .1-.1-.7-1.1-1.2h5.5a.6 .6 0 0 0 .9 .6 .6 .6 0 0 0 .1-1 .6 .6 0 0 0-.9 .3l-.1 .1h-5.5l-.2-.2v-3.3l.3-.1 .5 .4a.71 .71 0 0 0 .7-1.1 .71 .71 0 0 0-1.3 0l-.2-.1v-2.7l-.9-1-.4-.1v-.5l-.2-.2a.25 .25 0 0 1 .2-.4v-1.9l-.1-.2h-2l-.1 .1-.2 .4a.71 .71 0 0 0-.4 .6 .71 .71 0 0 0 .4 .7l.2 .4a.23 .23 0 0 1 .2 .3 .23 .23 0 0 1-.2 .2l-.1 1.9 .2 .2a.24 .24 0 0 1-.1 .4l-.1 .5-.5 .2-.4 .5v12.8l2.1 2.1v1.5l.2 .2h1.5l2.5 2.5a.25 .25 0 0 1-.4 .2 .62 .62 0 0 0-.6 .6 .62 .62 0 0 0 .6 .6l.9 .9v.5a.59 .59 0 0 0-.6 .3l-.4-.3h-.5v-.4a.6 .6 0 0 0-.6-.8 .6 .6 0 0 0-.5 .9v.3l-.4 .1a.23 .23 0 0 1-.3 .1 .23 .23 0 0 1-.2-.2l-.5-.1-.1-.5-4.5-4.6v-28.2l.1-.1h.1l.7 .5h2.8l.7-.6h.2a.65 .65 0 0 0 .3 .7 .65 .65 0 0 0 .7 0h2.1a.61 .61 0 0 0 .9 .6 .61 .61 0 0 0 .1-1 .61 .61 0 0 0-1 .4h-2.1a.6 .6 0 0 0 .1-.9 .6 .6 0 0 0-.9 0 .18 .18 0 0 1-.3-.1 .18 .18 0 0 1 .2-.2l.1-2.7-.2-.2-.7-.1a.74 .74 0 0 0-.3-1l-.1-2.6-.2-.3v-2.4l.1-.2 .2 .1v1.1l.2 .6 2.8 2.8a.25 .25 0 0 1 0 .4v.5l.1 .4a.64 .64 0 0 0 .4 .9l.3 .1 .4-.3h.1l2.4 2.4v2.8l-.2 .4v1.8l.3 .3h.6l.1 .2-.8 .9v1.4l-.2 .3v.4h-.3l-.3-.1-.5-.1a.37 .37 0 0 1 .2-.6v-.2a.92 .92 0 0 0-.1-.9l-.4-.1h-.6l-.3 .1a.92 .92 0 0 0-.1 .9l.3 .5v1l.4 .4 .4 .1a.74 .74 0 0 0 1 0l.3 .1a.57 .57 0 0 0 .4 .7h.5l.2-.1a.2 .2 0 0 1 .3-.1 .2 .2 0 0 1 0 .3l-.2 .4v.4l.2 .4v.1l-1.5 .2-.6 .6-.2 .4v.5l.2 .5 .8 .8h1.4l1.2 1.2 .9 .1 3.8 3.7v.2l-.1 .1h-.7l-.2 .1-.1 .3-.1 .7a.52 .52 0 0 0 .5 .4l.1 .2v.5h-.7l-.2 .3-.1 1.7-3.3-.8a.42 .42 0 0 1-.5 0h-2.3l-.1 .2v1.5l-.3 .1-.3-.2h-.5l-.3 .2-.1 .2v.4l.2 .3 .6 .1 .3-.1a.25 .25 0 0 1 .4 .1v1.4l.2 .2h2.2l.2-.1 1.3 .2v3.8l.4 .5 .3 .2h2.2l.3 .2v.7l.2 .4-.2 1.8v1.8l-.2 .3v1.2l.3 .2h.8l.2-.2v-1.2l-.2-.3 .1-.5a.67 .67 0 0 0 .8-.5v-2.3l-.1-.3 .2-.3a.17 .17 0 0 1 .2-.2 .17 .17 0 0 1 .2 .1v2.6l.9 .9h1.4v.2l-.3 .7a1.18 1.18 0 0 0 1 1.2v.2l-.7 .4-.2 .6a1.19 1.19 0 0 0 .9 1.4v.2l-.5 .2a1.15 1.15 0 0 0-.5 .9 1.29 1.29 0 0 0 1 1.3v.1l-.5 .3-.3 .4a1.17 1.17 0 0 0 .8 1.7v.2l-.3 .1a1.17 1.17 0 0 0-.7 1.2l.1 .1a1.34 1.34 0 0 0 .9 1v.1l-.5 .2-.3 .3-.2 .7a1.28 1.28 0 0 0 1 1.2v.1l-.3 .2a1.15 1.15 0 0 0-.7 1 1.29 1.29 0 0 0 1 1.2v.2l-.7 .4-.2 .3-.1 .4a1.17 1.17 0 0 0 1 1.2 1.17 1.17 0 0 0 1.3-.9h.2l.1 .7 .2 .2h1.9l.2-.2v-1.9l-.3-.2h-.5a.17 .17 0 0 1-.1-.2 .17 .17 0 0 1 .2-.1 1.17 1.17 0 0 0 .7-1.2 1.17 1.17 0 0 0-1-1v-.2l.1-.1a1.17 1.17 0 0 0 .9-1.2 1.17 1.17 0 0 0-1-1.1v-.1l.1-.1a1.17 1.17 0 0 0 .9-1.2 1.17 1.17 0 0 0-1-1.1v-.2l.1-.1a1.16 1.16 0 0 0 .9-1.2 1.16 1.16 0 0 0-1-1.1v-.1l.1-.1a1.17 1.17 0 0 0 .9-1.2 1.17 1.17 0 0 0-1-1.1v-.1l.1-.2a1.17 1.17 0 0 0 .9-1.1 1.17 1.17 0 0 0-1-1.1v-.2l.1-.1a1.18 1.18 0 0 0 .6-1.9v-.2l.4-.1 .2-.2v-2.4l-.1-.3-.4-.1-4.2-.1-.5-.4v-2.3l.1-.2a1.21 1.21 0 0 0 1.2 .6 1.21 1.21 0 0 0 1-.9 .33 .33 0 0 1 .4 .3 1.16 1.16 0 0 0 2 .1 1.16 1.16 0 0 0-.8-1.8v-.1l.1-.2a1.17 1.17 0 0 0 .9-1.1 1.17 1.17 0 0 0-1-1.1v-.2l.1-.1a1.17 1.17 0 0 0 .9-1.2 1.17 1.17 0 0 0-1-1.1v-.1l.1-.1a1.17 1.17 0 0 0 .9-1.2 1.17 1.17 0 0 0-1-1.1v-.2l.1-.1a1.17 1.17 0 0 0 .9-1.2 1.17 1.17 0 0 0-1-1.1v-.1l.1-.1a1.16 1.16 0 0 0 .9-1.2 1.16 1.16 0 0 0-1-1.1v-.1l.1-.2a1.17 1.17 0 0 0 .9-1.1 1.17 1.17 0 0 0-1-1.1v-.2l.1-.1a1.17 1.17 0 0 0 .9-1.2 1.17 1.17 0 0 0-1-1.1v-.1l.1-.1a1.17 1.17 0 0 0 .9-1.2 1.17 1.17 0 0 0-1-1.1v-.2l.1-.1a1.17 1.17 0 0 0 .9-1.2 1.17 1.17 0 0 0-1-1.1v-.1l.1-.1a1.17 1.17 0 0 0 .9-1.2 1.17 1.17 0 0 0-1-1.1v-.1l.1-.2a1.17 1.17 0 0 0 .9-1.1 1.17 1.17 0 0 0-1-1.1v-.2l.1-.1a1.17 1.17 0 0 0 .9-1.2 1.17 1.17 0 0 0-1-1.1v-.1l.1-.1a1.17 1.17 0 0 0 .9-1.2 1.17 1.17 0 0 0-1-1.1v-.2l.1-.1a1.17 1.17 0 0 0 .9-1.2 1.17 1.17 0 0 0-1-1.1v-.1l.1-.1a1.17 1.17 0 0 0 .9-1.2 1.17 1.17 0 0 0-1-1.1v-.1l.1-.2a1.17 1.17 0 0 0 .9-1.1 1.17 1.17 0 0 0-1-1.1v-.2l.1-.1a1.17 1.17 0 0 0 .9-1.2 1.17 1.17 0 0 0-1-1.1v-.1l.1-.1a1.17 1.17 0 0 0 .9-1.2 1.17 1.17 0 0 0-1-1.1v-.2l.1-.1a1.17 1.17 0 0 0 .9-1.2 1.17 1.17 0 0 0-1-1.1v-.1l.1-.1a1.17 1.17 0 0 0 .9-1.2 1.17 1.17 0 0 0-1-1.1v-.1l.1-.2a1.16 1.16 0 0 0 .5-1.9 1.16 1.16 0 0 0-1.9 .6l-.2 .1a1.28 1.28 0 0 0-1.3-1l-.4 .1a1.17 1.17 0 0 0-.7 1.2 1.17 1.17 0 0 0 1 1 .24 .24 0 0 1-.3 .3l-.5 .4-.2 .7a1.28 1.28 0 0 0 1 1.2v.1l-.3 .2a1.15 1.15 0 0 0-.7 1v.2a1.19 1.19 0 0 0 1 1 .29 .29 0 0 1-.3 .3l-.4 .3a1.13 1.13 0 0 0-.2 1.1l.4 .5 .5 .3 .1 .1-.2 .2a1.17 1.17 0 0 0-.9 1v.2a1.35 1.35 0 0 0 1 1.1v.1l-.3 .2a1.15 1.15 0 0 0-.7 1v.2a1.34 1.34 0 0 0 1 1v.2l-.3 .1a1.15 1.15 0 0 0-.7 1v.1a1.31 1.31 0 0 0 1 1.2v.1l-.5 .3-.3 .3a1.17 1.17 0 0 0 .8 1.8 .41 .41 0 0 1-.4 .4l-.4 .3-.1 .4a1.28 1.28 0 0 0 .9 1.5v.1l-.3 .1a1.17 1.17 0 0 0-.7 1.3 1.17 1.17 0 0 0 1 .9v.2l-.3 .2a1.16 1.16 0 0 0-.7 1.2l.1 .2a1.38 1.38 0 0 0 .9 .8v.2l-.5 .2-.3 .4a1.17 1.17 0 0 0 .8 1.7v.2l-.5 .3a1.15 1.15 0 0 0-.5 .9 1.32 1.32 0 0 0 1 1.2l-.1 .2a1.16 1.16 0 0 0-.9 1.1 1.29 1.29 0 0 0 1 1.3l-.1 .2a1.17 1.17 0 0 0-.9 1v.1a1.29 1.29 0 0 0 1 1.2l-.1 .2a1.16 1.16 0 0 0-.8 .9 1.18 1.18 0 0 0 .9 1.4v.2l-.7 .4-.2 .5a1.19 1.19 0 0 0 .9 1.4v.2l-.3 .2a1.16 1.16 0 0 0-.6 .8 1.19 1.19 0 0 0 .9 1.4v.2l-.7 .3a.21 .21 0 0 1-.2 .1 .21 .21 0 0 1-.1-.3l-6.4-6.4v-.5l.2-.3-.1-.6-.1-.4-.5-.5-.5-.1-.1-.7-.2-.3 .2-.5 .1-.9 .2-.4-.1-1.9-.3-.3h-.5l-.4 .3-.4-.3h-.4l-.3 .2a.21 .21 0 0 1-.3-.1v-1.1l1.1-1.2 .3-.5v-1.8l-.1-.3 .1-.2a.64 .64 0 0 0 .7 0 .64 .64 0 0 0 .3-.6h.3l.2 .5-.2 .6v1.7l.2 .3 .2 .1h.6l.2-.3v-1.8l-.1-.4v-.2a.62 .62 0 0 0-.1-1 .62 .62 0 0 0-.9 .3l-.1 .2h-.3a.67 .67 0 0 0-.6-.5l-1.2-.1-.4 .3-.2-.1-.1-2-2.3-2.4-.1-.5 .2-.3v-.5a.49 .49 0 0 1 0-.6l-.2-1.2-.2-.3 .1-.2a.45 .45 0 0 1 .7 0h.4l.3-.2v-.8a.34 .34 0 0 1-.2-.5v-1.7l1.3-1.4 1.3 .1 .1 1.3 .1 .2a.19 .19 0 0 1 .1 .2 .19 .19 0 0 1-.2 .2l-.1 .2v.5l.1 .2 .3 .2h.4l.2-.2 .4-.7v-.5l.3-.1 .2-.2v-1.5l-.2-.2-.3-.1-.4-.4-.8-.1v-1.4l-.2-.2a.16 .16 0 0 1-.1-.2 .16 .16 0 0 1 .1-.1l.2-.3v-.7l-.4-.2h-.4a.56 .56 0 0 0-.4 .6l-.2 .2v.6h-.2l-.1-.1v-4.3l-3.7-3.7v-.1l.1-.1a.71 .71 0 0 0 .8-.8 .71 .71 0 0 0-.8-.7 .71 .71 0 0 0-.6 .9l-.2 .1-.4-.2h-16.6h-.2l-2.5 2.6h-.6l-2.9-2.9h-.2l-15.8-.1a.49 .49 0 0 1-.6 0h-.4l-.3 .2v.7l.1 .3-.2 .7-.2 .2h-.9l-.8 .9-.1 5.7h-.2l-.6-.5h-.8l-.2-.2a.8 .8 0 0 0-1 0l-.2 .3-.1 .3 .2 .6-.2 .7 .2 .6-.1 .2-3 .1-1.4 1.3-.1 .2h-.2a.6 .6 0 0 0-1 .2l-.7 .8-.1 .4-.3 .2h-1.9a.6 .6 0 0 0-.9 .6 .6 .6 0 0 0 .9 .5h.4v.7l.1 .2 .3 .1h.5l.3-.1h2.2l.4 .2h1l.3-.2 1.1 .1 .3-.2v-.5a.45 .45 0 0 1 .1-.7v-.2a.67 .67 0 0 0 .6-.4 .67 .67 0 0 0-.1-.7l-.3-.2h-.3a.21 .21 0 0 1-.2 .1 .21 .21 0 0 1-.2-.1v-.7l.2-.8h1.9l.2 .1-.1 .2a.98 .98 0 0 0 .1 1.2l-.2 .6 .2 .5a.8 .8 0 0 0 1.1 .1l.2-.2h1.7l.7 .2 .6 .7 .8 .1v1a.42 .42 0 0 1 .2 .4 .42 .42 0 0 1-.2 .4v1.5a.86 .86 0 0 0 .1 1.2 .63 .63 0 0 0 1-.5l.1-.5 .3-.3-.1-1.5a.38 .38 0 0 1-.2-.3 .38 .38 0 0 1 .2-.4l.1-.9-.3-.4 .3-.3a.24 .24 0 0 1 .2-.2 .24 .24 0 0 1 .2 .2l-.1 .8 .1 .8 .3 .3h.6l.2 .3v1.7l.2 .2h1l.3-.3v-1.4l-1.1-1.1-.1-.6-.1-.2a.46 .46 0 0 1-.4-.6 .24 .24 0 0 1 .2-.2 .24 .24 0 0 1 .2 .3h.6l.4-.2v-1.9l-.1-.3-.3-.1h-.4l-.3 .1a.2 .2 0 0 1-.2 .1 .2 .2 0 0 1-.1-.2l-.1-1.2-1.2-1.3v-2a.24 .24 0 0 1 .2-.3 .24 .24 0 0 1 .3 .3h.6l.4-.2 .4 .2h.4l.3-.1 .1-.3v-1.7l-.2-.3 .1-.7 .1-.1 .3 .2h.5a.45 .45 0 0 1 .6 0h.4l.5-.2 1.2-1.2 .2 .1v.4a.7 .7 0 0 0 .8 .5 .7 .7 0 0 0 .6-.8 .7 .7 0 0 0-.8-.6l-.2-.2 .3-.2h2.2h.2v.6l.3 .2 1.3-.2 .3 .2 .7-.1 .7 .1 .3-.1a.23 .23 0 0 1 .2 0 .23 .23 0 0 1 .2 .2l-.1 1.7 .2 .2a.19 .19 0 0 1-.1 .3 .19 .19 0 0 1-.3-.1l-1.7-.1-.2 .2v.6l-.2 .2-.4-.1-.2-.1h-.4a.46 .46 0 0 1-.7 0h-.4l-.4 .2-.3-.1a.61 .61 0 0 0-.8 .1 .61 .61 0 0 0 .1 .9 .61 .61 0 0 0 .8-.1h.3l.3 .2h.4a.45 .45 0 0 1 .7 0h.4l.3-.2h.4l.1 .6a.2 .2 0 0 1-.2 .1 .2 .2 0 0 1-.2-.1h-.8l-.2 .3v.4a.25 .25 0 0 1-.1 .4 .25 .25 0 0 1-.3-.1l-.6-.1-.3 .1-.1 .3v.4l.1 .2 .3 .2h.4l.3-.2 .7 .2 .6-.1a.37 .37 0 0 1 .6 0h1.6h.1v.3l-.1 .1h-1.6l-.2 .2h-.7l-.5 .3-.5-.2h-.5l-.3 .2-2.1-.1-.1-1.3-.1-.3 .2-.6-.1-.6-.3-.2h-.5l-.2 .1-.1 .2v.5l.1 .5-.6 .1-.2 .2v1.6l.1 .1 .4 .1 .4 .5 .8 .1v1.3l.1 .5-.1 .4v.5l.2 .3h.6l.1 .2-.7 .7-.4 .2-.3 .5-2.3 2.4-.1 2.1-2 1.9h-4.9l-.8 .6h-13.8l-.2 .1-1.7 1.8-.1 .2v2.6l1.6 1.7 .1 1-1.7 1.9v10.5l.1 .2 1.5 1.6 .1 1.1-1.2 1.2v2.3l-.1 .1-.6-.2a.55 .55 0 0 0-.4-.7l-.6 .1a.25 .25 0 0 1-.5 0 .61 .61 0 0 0-.9-.4 .61 .61 0 0 0-.1 .9l-.2 .2a.8 .8 0 0 0-.8 .6v.4a.8 .8 0 0 0 .6 .6 .8 .8 0 0 0 .8-.3l.2-.1h.7l.3 .2h.5l1-.3 .1 1.7-.1 .1h-.7l-.3-.1-1.5 .1-.3-.2a.8 .8 0 0 0-1 0l-.2 .3-.1 .3 .1 .5-.1 .3v1.1l.2 .2h1.2l.2-.1v-.5h.2h.4l.4 .1h.6l.3-.3-.1-.8h.7l.1 .1v21.9l3.7 3.8 2 .1 .1 .8a.2 .2 0 0 1 .1 .2 .2 .2 0 0 1-.1 .2h-9.1l-1-.8a.39 .39 0 0 1 .6-.2l.5-.1a3.1 3.1 0 0 0 2-1.6l.3-1v-.8a3.2 3.2 0 0 0-2.4-2.8 .52 .52 0 0 1 .3-.6v-.7l-.1-.3-.3-.1-1 .1-.1-.2v-12.2h.3v.1a.8 .8 0 0 0 .6 .7 .8 .8 0 0 0 .8-.3l.2-.1h1.3l.7-.2 .1-.3v-.4l-.1-.3 .1-.3v-.4l-.1-.2-.2-.2h-.6l-.3 .2h-.9l-.4-.3a.8 .8 0 0 0-.9 .1l-.2 .2-.1 .4 .3 .7-.3 .6h-.3v-14.9l.1-.2a1.17 1.17 0 0 0 1.7 .3 1.17 1.17 0 0 0 .2-1.7 1.17 1.17 0 0 0-1.7-.1l-.2 .1-.1-.1v-3.2h1.8v.1a.61 .61 0 0 0 1 .3 .61 .61 0 0 0-.2-1 .61 .61 0 0 0-.8 .6h-1.8v-2.3l.1-.2h2l.2-.2v-.7a.63 .63 0 0 0 1-.3 .63 .63 0 0 0-.4-.9l-.5 .1-.4-.3h-2v-3a.22 .22 0 0 1 .2-.2 .22 .22 0 0 1 .2 .2 1.16 1.16 0 0 0 1.6-.2 1.16 1.16 0 0 0-.2-1.6 1.16 1.16 0 0 0-1.6 .2l-.2-.1v-3.2l2.1-.1 .2-.2v-1.4l1-1.1v-1.1l.4-.4 .7 .1a.45 .45 0 0 1 .6 0h.4a.62 .62 0 0 0 .4-.7h.7a.62 .62 0 0 0 .9 0 .62 .62 0 0 0 .1-.9 .61 .61 0 0 0 .1-.8 .61 .61 0 0 0-.7-.2l-.3 .1h-.8l-.4-.2h-.4a.49 .49 0 0 1-.7 0h-.4l-.3 .2h-1.3a1.44 1.44 0 0 0-1.3-.7l-.4 .1-.3 .2a.16 .16 0 0 1-.2 .1 .16 .16 0 0 1-.1-.1v-11.8l.1-.2 1 .1 .4-.2v-.8l-.3-.4v-.4l.1-.2a3.1 3.1 0 0 0 2-1.6l.3-1v-.8a3.2 3.2 0 0 0-3.4-2.8z"/>
<path d="M109.9 140.7l7.7-.1 .6 .6 .1 1.5 .2 .2h1.3l.2 .1-1 1-10.3-.1-.8-.9 .1-.1 1.5-.1 .1-.2v-.9a.93 .93 0 0 0 .3-.9z"/>
<path d="M141.6 140.8h.2h6.6l1.3 1.3 .5 .1v.4l.2 .2 1.9 .1 .2-.2a.21 .21 0 0 1 .2-.1 .21 .21 0 0 1 .2 .2l.5 .1 .1 .2-.8 .9h-11.4l-.1-.2 .1-.6a.41 .41 0 0 1 .3-.5z"/>
<path d="M125.6 140.7l8-.1 .6 .6v1.4l.2 .2 1.9 .1 .2-.2a.21 .21 0 0 1 .2-.1 .21 .21 0 0 1 .2 .2l.2 .1v.2l-.9 .9h-9.9l-.2-.1a.85 .85 0 0 0-.4-1.1l-.1-.1z"/>
<path d="M98.9 112.5h.2l.1 .1v1.4l.2 .2h1.4l.3 .5v25.2l1.1 1.3 .1 1.5 .2 .2h1.4v.2l-.2 .2h-1.6l-3.2-3.3z"/>
<path d="M102 124.8a.2 .2 0 0 1 .2 0 .2 .2 0 0 1 .1 .2l.2 .1h1.8l.2-.1a.17 .17 0 0 1 .1-.2 .17 .17 0 0 1 .2 .2l.2 .1h1.8l.2-.1a.17 .17 0 0 1 .2-.2 .17 .17 0 0 1 .2 .2l.2 .1h1.8l.2-.1a.17 .17 0 0 1 .1-.2 .17 .17 0 0 1 .2 .2l.2 .1 1.9-.1 .1-.2v-1.9a.16 .16 0 0 1-.1-.2 .16 .16 0 0 1 .2-.1 .67 .67 0 0 0 .2-1.1l.1-.2h5.2l1.2 1.3v.2h-.4l-.3 .2 .1 2 .2 .1h1.8l.1-.1a.23 .23 0 0 1 .3-.2 .23 .23 0 0 1 .2 .2l1.9 .1 .2-.1a.23 .23 0 0 1 .2-.2 .23 .23 0 0 1 .2 .2l2 .1 .1-.1a.23 .23 0 0 1 .3-.2 .23 .23 0 0 1 .2 .2h2l.2-.2-.1-1.8-.2-.2-.5-.1-.1-2.2-3.4-3.5h4.7a.6 .6 0 0 0 .8 .6 .6 .6 0 0 0 .1-1 .6 .6 0 0 0-.9 .3v.1h-4.7l-.7-.7a.17 .17 0 0 1-.1-.2 .17 .17 0 0 1 .2-.1 .64 .64 0 0 0 .5-.9 .7 .7 0 0 0 .4-1v-.7v-.1l2.1-.1 .6-.4a.26 .26 0 0 1 .4-.1 .6 .6 0 0 0 .9-.6 .6 .6 0 0 0-.9-.5h-.1l-.1-.1v-1.3l.1-.4 .5-.5h1.9l.2 .5-.1 .8a.18 .18 0 0 1 0 .2 .18 .18 0 0 1-.2 0 .62 .62 0 0 0-1 .3 .62 .62 0 0 0 .7 .8l.5 .1v.9l.2 .3 .2 .1 1.8-.1 .9 1v.2h-.2a.62 .62 0 0 0-1 .1 .62 .62 0 0 0 .4 .9l.2 .5 .6 .3v8.7l.1 .2 1.5 1.4 .2 .1h7.8l1-1 .1-.5h.4l.2-.1v-2l-.2-.2h-1.8l-.2 .1a.23 .23 0 0 1-.2 .1 .23 .23 0 0 1-.2-.2h-1.9l-.3 .2a.25 .25 0 0 1-.4-.2l-.5-.1v-.9l6.1-6.1 .1-.2v-23.6h.3a.6 .6 0 0 0 .9 .6 .6 .6 0 0 0 .1-1 .6 .6 0 0 0-.9 .3l-.1 .1h-.3v-5.9l.9-1 .1-1.3 .5-.2 .1-.7 .9-.1 1.2 1.2v34.1l.1 .2 2.6 2.6-.1 1.9-.4 .1-.3 .2 .1 2 .2 .1h1.8l.2-.1a.23 .23 0 0 1 .2-.2 .23 .23 0 0 1 .2 .2l1.9 .1 .2-.1a.23 .23 0 0 1 .2-.2 .23 .23 0 0 1 .2 .2l2 .1 .1-.1a.23 .23 0 0 1 .3-.2 .23 .23 0 0 1 .2 .2l1.9 .1 .3-.3-.1-1.9-.2-.1-.6-.1-.1-.8-1.1-1.2a.19 .19 0 0 1-.1-.2 .19 .19 0 0 1 .3-.1l2.2 2.2v8.3l-8.2 8.2-.1 1.1-.2 .3-1.5 .1a.43 .43 0 0 0-.3 .5h-.2l-1.3-1.2h-6.7l-.2-.2a.78 .78 0 0 0-.8-.7 .62 .62 0 0 0-.9-.1 .62 .62 0 0 0-.1 .9l-.2 .1h-1.8l-.2-.1 .2-.4a.85 .85 0 0 0 .6-.6l.4-.2 .2-.4 .4-.2 .2-.5h.2a.7 .7 0 0 0 .4-.7l.1-.1a.61 .61 0 0 0 .8-.5 .61 .61 0 0 0-.6-.7 .61 .61 0 0 0-.6 .7l-.1 .1a.6 .6 0 0 0-.8 .5l-.5 .3-.2 .4a.88 .88 0 0 0-.6 .7l-.4 .2-.3 .4a.64 .64 0 0 0-.4 1l-.9 .8h-1l-1-.8h-6l-.2-.2 .1-.6-.2-.3a.62 .62 0 0 0-.2-1 .62 .62 0 0 0-.9 .6l.2 .5-.1 .4 .2 .4-.1 .2h-5.9l-.9 .8h-1.1l-.9-.8h-13.1l-.9 .8h-1l-1-.9v-3.8h31a.61 .61 0 0 0 .8 .5 .61 .61 0 0 0 .2-1 .61 .61 0 0 0-1 .3v.2h-31v-.8h47.1a.6 .6 0 0 0 .8 .6 .6 .6 0 0 0 .3-1l2.2 .1a.61 .61 0 0 0 .9 .5 .61 .61 0 0 0 .1-1 .61 .61 0 0 0-1 .4h-2.2a.6 .6 0 0 0-.7-.1 .6 .6 0 0 0-.4 .5h-47.1v-2.4h53.2v.2a.61 .61 0 0 0 1 .3 .61 .61 0 0 0-.2-1 .61 .61 0 0 0-.8 .5h-53.2v-1.3h51.5a.61 .61 0 0 0 .9 .6 .61 .61 0 0 0 .1-1 .61 .61 0 0 0-.9 .4h-51.6v-1.7h25.5a.61 .61 0 0 0 .9 .6l.2-.1 .1 .2a.68 .68 0 0 0 .4 .5 .68 .68 0 0 0 .7-.1l.4 .2 .3-.1 .2-.2h20.8a.61 .61 0 0 0 .9 .6 .61 .61 0 0 0 .1-1 .61 .61 0 0 0-1 .3l-20.8 .1v-.1a.6 .6 0 0 0-.5-.8l-.5 .1-.4-.1-.4 .1-.2-.1-.1-.4 .2-.3v-.5h27a.65 .65 0 0 0 .6 .6 .65 .65 0 0 0 .7-.4h.1a.61 .61 0 0 0 .7-.7l.1-.2h.5a.61 .61 0 0 0 .8 .6 .61 .61 0 0 0 .2-1 .61 .61 0 0 0-1 .3l-.5 .1a.6 .6 0 0 0-.3-1 .6 .6 0 0 0-.7 .8l-.3 .3-.1 .1a.61 .61 0 0 0-.8 .5h-27v-.1a.6 .6 0 0 0-.4-1 .6 .6 0 0 0-.6 .9l-.2 .5 .1 .3-.2 .5h-25.5v-3h14.6a.6 .6 0 0 0 .8 .6 .6 .6 0 0 0 .2-1 .6 .6 0 0 0-1 .3v.1h-14.6v-.8h28.7v.1a.61 .61 0 0 0 1 .3 .61 .61 0 0 0-.2-1 .61 .61 0 0 0-.8 .6h-28.7z"/>
<path d="M158.3 134.2l.3 .1a.61 .61 0 0 0 .9-.1 .61 .61 0 0 0-.1-.9v-.1l1.3-1.4h.2v2.3l-6.4 6.4-1.4 .1v-.2v-.9z"/>
<path d="M135.9 121.2l7.6-7.7h.2v1.8l-6.1 6.1-.1 1.3-.7 .2a.23 .23 0 0 1-.2 .1 .23 .23 0 0 1-.2-.2l-.6-.1z"/>
<path d="M151.8 121.2h.3l1.4 1.4-.1 .2h-.4l-.2 .1a.23 .23 0 0 1-.2 .1 .23 .23 0 0 1-.2-.2l-.6-.1z"/>
<path d="M134.2 116.6h.2a.65 .65 0 0 0 .6 .5 .65 .65 0 0 0 .6-.6h.2l.1 .1v.6l.1 .2 2 .1 .1 .2-3.1 3.1-.1 1.9-.6 .2-.2-.2v-2.6l.1-.1h.2a.61 .61 0 0 0 .8-.1 .61 .61 0 0 0 0-.9 .61 .61 0 0 0-.9 .1l-.2-.2v-2.2z"/>
<path d="M100.8 90.6l1-1h11.6l.1 .2-10.5 10.6v22a.15 .15 0 0 1-.2 .2 .15 .15 0 0 1-.1-.1l-.3-.2-.4-.1-.1-.2v-7.3l.5-.8v-4.4l-.9-1.1v-1l.8-.9v-12.3l-.8-1v-1.4l-.2-.2-.5-.1z"/>
<path d="M157 117.7l.5-.5h.1l3.7 3.7v1l-.2 .1-4.1-4.1z"/>
<path d="M120.9 115.3h.1l.4 .1a.19 .19 0 0 1 .2 .1 .19 .19 0 0 1-.1 .3 .62 .62 0 0 0 .1 .7 .62 .62 0 0 0 .7 .1l.7 .8v.2a.64 .64 0 0 0-.1 1v.5l.2 .3v.6a.16 .16 0 0 1 0 .2 .16 .16 0 0 1-.2 0l-1-.1a.71 .71 0 0 0-.2-.7 .71 .71 0 0 0-.8-.1z"/>
<path d="M113.9 114.8l3-.1 .1 1.8 .1 .2h1.9a.39 .39 0 0 0 .3-.5h.2a.32 .32 0 0 1 .5 0v3.6l-.1 .2-10.8-.1v-.3z"/>
<path d="M105.5 109h.2l1.9 1.8 .2 .1h9l.1 .1 .2 .6a.22 .22 0 0 1 .1 .2 .22 .22 0 0 1-.2 .2l-.1 1.8-3.3 .1-5.2 5.1a.64 .64 0 0 0-.5 .8l-.2 .1h-1.1l-1.1-1.1z"/>
<path d="M166 114.9l2.3-.1 .1-.2v-1.4h.2l.2 .2 .1 5.3-.1 .1h-.2l-.1-.3-.5-.4-.5 .1-.6-.1-.4 .1-.5-.2-.2-.1v-2.6z"/>
<path d="M142.7 111.2h.2l.1 .1v1.5l-4.6 4.6a.15 .15 0 0 1-.1 0 .15 .15 0 0 1-.1-.2v-1.4z"/>
<path d="M152.5 112.3h.7a.35 .35 0 0 1 .5-.1l.1 .1a.23 .23 0 0 1 .1 .3 .23 .23 0 0 1-.2 .2v1.4l-.2 .2-1.1-1.1z"/>
<path d="M140.1 111.3l1.8-1.8h.2v1.1l-3.7 3.7h-.2v-1.1z"/>
<path d="M154.8 98.9h.2l.3 .3v6.8l1.3 1.5v3.8l-.4 .5-.2-.1v-1.4l-.3-.2h-1.8l-.2 .1-.1 .6-1 .2-.2-.2v-8.9l.2-.1 2 .1 .2-.2v-1.9l-.1-.2a.23 .23 0 0 1-.1-.2 .23 .23 0 0 1 .2-.2z"/>
<path d="M135.1 101.9h1.7l.2-.3 .1-.4 .9-.1 1.7-1.7 .1-1.7 1.3-1.4h.2l.1 12.5-3 3-.2-.1v-1.3l-.1-.3a.23 .23 0 0 1-.2-.2 .23 .23 0 0 1 .2-.2l.1-1.9-.1-.2h-2l-.2 .1v.3a.35 .35 0 0 1-.5 .1h-.2l-.1-.1z"/>
<path d="M120.9 108.8l.2-.1 1.4 1.5v.1l-.3 .2-1.2 1.1-.2-.1z"/>
<path d="M106 107.1h.2l1.4 1.3h9.2h.1l.2 .6a.22 .22 0 0 1 .1 .3 .22 .22 0 0 1-.2 .2l-.1 .5-.1 .1h-8.7l-2.1-2z"/>
<path d="M121.3 101.8l.8-.8a.31 .31 0 0 1 .4 .4l.1 .2 .2 .1h2.7l1.4-1.4 .1-.6h.2l.7 .6a.36 .36 0 0 1 .3 .5v.6l.3 .3 3.9-.1a.32 .32 0 0 1 .1 .5l.3 .6v2.3h-.3l-.9-1a.63 .63 0 0 0-.6-.6 .63 .63 0 0 0-.7 .6 .63 .63 0 0 0 .7 .6l.9 1v2.1l-.1 .4-.2 .2-4.1 .1-.8 .7-.4 .2a.19 .19 0 0 1-.3 0 .19 .19 0 0 1 .1-.3l-.1-1-.2-.3-2.1 .1-.4-.4h-.5a.6 .6 0 0 0-1 .3v.1a.17 .17 0 0 1-.1 .2 .17 .17 0 0 1-.2-.2v-1h8.2a.61 .61 0 0 0 .8 .6 .61 .61 0 0 0 .2-1 .61 .61 0 0 0-1 .3v.1h-8.2v-2.4h6.2a.61 .61 0 0 0 .8 .6 .61 .61 0 0 0 .2-1 .61 .61 0 0 0-1 .3l-6.2 .1v-1.5a.64 .64 0 0 0-.2-1z"/>
<path d="M98.4 97.8l.7-.6 .1 .2v1.3l.1 .2h2l.1 .2v7.1l-.5 .6h-1.6l-.1 .2v1.4l-.2 .1-.7-.7z"/>
<path d="M106.5 101.9l6.4-6.4h2.3a.61 .61 0 0 0 .9 .6 .61 .61 0 0 0 .1-1 .61 .61 0 0 0-1 .3v.1h-2.3l3.9-3.8 .2 .2v1.8a.25 .25 0 0 1 .2 .3 .25 .25 0 0 1-.2 .2v2.1a.25 .25 0 0 1 .2 .2 .25 .25 0 0 1-.2 .3v2a.25 .25 0 0 1 .2 .3 .25 .25 0 0 1-.2 .2v2l.2 .2h1.9v5.1l-.2 .2h-1.7l-.2 .1-.1 .5-.1 .1h-8.9l-1.4-1.4z"/>
<path d="M161.8 101.5a.27 .27 0 0 1 .3 .3l.3 .1h1.1v.6l.2 .3v.5h-.7l-1.2-1.2a.25 .25 0 0 1-.2-.2 .25 .25 0 0 1 .2-.2z"/>
<path d="M124.6 98.4h.5l.3 .2 .5-.1 .1 .1v1.3l-.9 .8h-.4l-.2-.1v-1.7z"/>
<path d="M119.3 98.3l.1-.1h1.5l.7 .8-1.3 1.3-.4-.2-.6-.2-.2-.7a.23 .23 0 0 1-.1-.2 .23 .23 0 0 1 .2-.2z"/>
<path d="M134.2 96.4l.4-.3 .1 .1 .1 .4a.3 .3 0 0 1 .2 .3 .3 .3 0 0 1-.2 .3l-.1 1.9a.39 .39 0 0 1 .3 .3 .39 .39 0 0 1-.3 .4l-.1 .1h-.1l-.7-.8 .4-.6z"/>
<path d="M119.3 95.7l.6-.1 3-3h9.9l.3-.2h.2a.93 .93 0 0 0 .7 .5l.2 .3v.2l-1.5 1.4-.1 1-.7 .1-.6 .5-.5 .2-.2 .3-3.4-.1-1 .9-.4-.3a.17 .17 0 0 1-.3-.1 .17 .17 0 0 1 .1-.2 .62 .62 0 0 0 0-.9 .62 .62 0 0 0-.8 0h-2h-.2l-.1 .3v1.5l-.2 .2h-.3l-.8-.8-1.9-.1v-.4a.39 .39 0 0 1-.3-.4 .39 .39 0 0 1 .3-.3z"/>
<path d="M139.1 85.9l.1-.1 .6 .1v2.1l-.1 .2a.63 .63 0 0 0-.9 .5 .63 .63 0 0 0 .9 .7l.1 .1v5.7l-2.6 2.5-.2-.1v-.4l-.1-.1a.23 .23 0 0 1-.1-.3 .23 .23 0 0 1 .2-.2v-1.9l-.1-.2a.23 .23 0 0 1-.1-.2 .23 .23 0 0 1 .2-.2v-1.9l-.1-.2-1.9-.1-.5 .2-.5-.5v-.1l5-4.9z"/>
<path d="M98.4 90.6l1.4-1.4 .9 .1v.1l-.8 .9v1.2l-.5 .1-.2 .2v1.3l-.2 .2-.7-.7z"/>
<path d="M93.5 86.1l.1-.1a1.24 1.24 0 0 0 2.1-.2h1.5a.19 .19 0 0 1 .2 .2 .19 .19 0 0 1-.1 .2l-.4 .2-.9 .8-.1 1.3-.7 .7-1.6 .1-.1-.2z"/>
<path d="M130.8 71.6l.1-.1h1.9l1.9 2 .8 .1a.6 .6 0 0 0 1-.3 1.23 1.23 0 0 0 .8-.6h.4l.3-.4a1.24 1.24 0 0 0 .9-.6 .62 .62 0 0 0 .6-.4 .62 .62 0 0 0-.2-.7l.2-.2h1.7l.2 .1v.3l-4.2 4.1a.61 .61 0 0 0-.5 .7 .61 .61 0 0 0 .7 .6 .61 .61 0 0 0 .5-.7l.3-.2h.2a.63 .63 0 0 0 .7 .2 .63 .63 0 0 0 .4-.6l3.3-3.4h.2l.4 .2h.4a.42 .42 0 0 1 .5 0h1.6l.3-.2h.4l.5 .4h1.7l.2-.2 .2-.2v-.8a.55 .55 0 0 0-.5-.5h-.7l.1-1.2h7.5l1.8 1.8-.1 .3-.5 .2-.3-.2a.64 .64 0 0 0-.8 .6l-.1 .2-.2-.1v-.5l.1-.3v-.7l-.3-.2h-.4a.44 .44 0 0 1-.7 0l-.5 .1-.3 .3h-.4l-.5 .3-.5-.1h-.5l-.3 .1-.6-.1h-.7l-.2 .3v.5l.2 .2-.2 .3v.5l-.1 .1-.3-.1h-2.5l-.4 .2-.2-.5-.2-.1-1.7 .1-.1 .2v7.1l.2 .2h1.6l.3-.3v-4.8v-.7l.3-.1 .2 .1v.7l.2 .3 .2 .1h2.1a.69 .69 0 0 0 1.1-.3l.7 .7-.1 4.2-.1 .1h-.4h-.5l-.4-.3h-1.2a.62 .62 0 0 0-.5 .8l-.2 .1-.3-.1-3-.1-.2 .1v3.2l.1 .2 .4 .1 .1 .1v.8l-.5 .5-.2-.1v-1l-.3-.3h-12.6l-.3 .3 .1 1.7 .2 .1h1.2l.1 .2-2.6 2.6h-8.1l-.1-.2 2.6-2.6 .1-2.7 .2-.5 1.3-1.3h.2a.64 .64 0 0 0 .8 .6l.4 .2v.5l-.7 .8-.1 1.3-.4 .4a.6 .6 0 0 0-.6 .8v.2a.62 .62 0 0 0-.7 .6 .62 .62 0 0 0 .7 .6 .62 .62 0 0 0 .5-.7v-.2l.5-.3 .2-.4 .7-.7v-1.2l.2-.2 1.1-.1 .3 .2h1.6l.2-.2 .1-6.5v-.2l.2-.1a.61 .61 0 0 0 1-.1 .61 .61 0 0 0-.5-.9v-.9l.2-.5-.1-.4 .1-.4-.2-.4 .1-.2a.62 .62 0 0 0-.1-.7 .62 .62 0 0 0-.6-.2l-.1-.1z"/>
<path d="M121.9 84.1l1.1-1.2h.3l.1 .3v2.2l-2.7 2.7-.6 .1v-.3l1.7-1.7z"/>
<path d="M147.9 81.3l.3-.1 .3-.2 1.1-.1a.36 .36 0 0 1 .6-.1l.3 .1 .1 .2-.9 .9v.9l-.2 .2-1.6-1.6z"/>
<path d="M126.6 80.1l.7-.7a.33 .33 0 0 1 .4 .3l.1 .1-.1 .4-.7 .1a.26 .26 0 0 1-.4 .1z"/>
<path d="M124.9 78.4l.7-.2 .1-.1v-.4l.2-.1 .3 .1 .5 .1 .1 .1-1.6 1.6-.2-.1z"/>
<path d="M156.9 75.5a.38 .38 0 0 1 .4 .4 .62 .62 0 0 0 .8 0 .62 .62 0 0 0 .2-.8l.1-.1h.9a.17 .17 0 0 1 .3 0 .17 .17 0 0 1 0 .2l-1.7 1.7-1.4 .1-1 .9-.1 .7-1.2 .1a.19 .19 0 0 1-.2-.1 .19 .19 0 0 1 0-.2z"/>
<path d="M156.9 77.8h1.1v.8l-.5 .1-1.1-.1-.1-.3z"/>
<path d="M150.8 71.8l.3-.1 .3 .1h.5l.3-.1h.7a.35 .35 0 0 1 .5 .2l-.1 .6 .2 .4v1.9l-.1 .1a.61 .61 0 0 0-.5 1 .61 .61 0 0 0 1 0h.1a.3 .3 0 0 1 .2 .4l-2.1 2.2h-.2l-.1-3.4-.9-1a.3 .3 0 0 1 .4-.3 .62 .62 0 0 0 .3-.7 .62 .62 0 0 0-.7-.5z"/>
<path d="M116.8 75.7l.2-.1 .8 .8v.9a.24 .24 0 0 1-.2 .3 .24 .24 0 0 1-.3-.3h-.6l-.2 .1a.18 .18 0 0 1-.3 .1 .18 .18 0 0 1 0-.2l.5-.7z"/>
<path d="M114.6 68.6l.4-.4 .7 .1 .1 .3a.43 .43 0 0 1 0 .6v.5l.1 .3v6.3l-.4 .4-.1-.2-.1-1.6-.7-.8z"/>
<path d="M139.9 68.1l.3-.2h6.5a.17 .17 0 0 1 .1 .1 .17 .17 0 0 1-.2 .2l-1.3 1.3-.3 .5v.5h-.7a.23 .23 0 0 1-.3 0 .23 .23 0 0 1 0-.3v-1.6l-.1-.2-3.9-.1h-.1z"/>
<path d="M118.7 68.3l1.3-1.2h3.3l.1 .1v.2l-1.2 1.2h-.7a.44 .44 0 0 1-.7 0h-.5a.4 .4 0 0 1-.5 0h-.6l-.5 .3v-.1z"/>
<path d="M160.6 113.6l1.7-.1v-1.5l.2-.1 3.1 .8v.1v.7h1.4v.5h-1.4v.6l.1 .3-.2 .2v2.9l.4 .4 .6 .1 .4-.1 .6 .1 .4-.1 .4 .4v2.6l-.1 .1h-.4v2.1l-.5-.1v-2h-.4v-.9l-.4-.3h-2.4l-.4-.4v-4.2h-1.3l-.1-1.7h-1.6h-.1z"/>
<circle cx="179.7" cy="145" r="2.85"/>
<circle cx="179.7" cy="65" r="2.85"/>
<circle cx="94" cy="67.6" r="2.85"/>
<circle cx="94" cy="141.2" r="2.85"/>
<circle cx="172.1" cy="143.8" r=".85"/>
<circle cx="174.6" cy="141.2" r=".85"/>
<circle cx="172.1" cy="141.2" r=".85"/>
<circle cx="174.6" cy="138.7" r=".85"/>
<circle cx="172.1" cy="138.7" r=".85"/>
<circle cx="174.6" cy="136.1" r=".85"/>
<circle cx="172.1" cy="136.1" r=".85"/>
<circle cx="174.6" cy="133.6" r=".85"/>
<circle cx="172.1" cy="133.6" r=".85"/>
<circle cx="174.6" cy="131.1" r=".85"/>
<circle cx="172.1" cy="131.1" r=".85"/>
<circle cx="174.6" cy="128.5" r=".85"/>
<circle cx="172.1" cy="128.5" r=".85"/>
<circle cx="174.6" cy="126" r=".85"/>
<circle cx="172.1" cy="126" r=".85"/>
<circle cx="174.6" cy="123.4" r=".85"/>
<circle cx="172.1" cy="123.4" r=".85"/>
<circle cx="174.6" cy="120.9" r=".85"/>
<circle cx="172.1" cy="120.9" r=".85"/>
<circle cx="174.6" cy="118.4" r=".85"/>
<circle cx="172.1" cy="118.4" r=".85"/>
<circle cx="174.6" cy="115.8" r=".85"/>
<circle cx="172.1" cy="115.8" r=".85"/>
<circle cx="174.6" cy="113.3" r=".85"/>
<circle cx="172.1" cy="113.3" r=".85"/>
<circle cx="174.6" cy="110.7" r=".85"/>
<circle cx="172.1" cy="110.7" r=".85"/>
<circle cx="174.6" cy="108.2" r=".85"/>
<circle cx="172.1" cy="108.2" r=".85"/>
<circle cx="174.6" cy="105.7" r=".85"/>
<circle cx="172.1" cy="105.7" r=".85"/>
<circle cx="174.6" cy="103.1" r=".85"/>
<circle cx="172.1" cy="103.1" r=".85"/>
<circle cx="174.6" cy="100.6" r=".85"/>
<circle cx="172.1" cy="100.6" r=".85"/>
<circle cx="174.6" cy="98" r=".85"/>
<circle cx="172.1" cy="98" r=".85"/>
<circle cx="174.6" cy="95.5" r=".85"/>
<circle cx="172.1" cy="95.5" r=".85"/>
<circle cx="174.6" cy="93" r=".85"/>
<circle cx="172.1" cy="93" r=".85"/>
<circle cx="174.6" cy="90.4" r=".85"/>
<circle cx="172.1" cy="90.4" r=".85"/>
<circle cx="174.6" cy="87.9" r=".85"/>
<circle cx="172.1" cy="87.9" r=".85"/>
<circle cx="174.6" cy="85.3" r=".85"/>
<circle cx="172.1" cy="85.3" r=".85"/>
<circle cx="174.6" cy="82.8" r=".85"/>
<circle cx="172.1" cy="82.8" r=".85"/>
<circle cx="174.6" cy="80.3" r=".85"/>
<circle cx="172.1" cy="80.3" r=".85"/>
<circle cx="174.6" cy="77.7" r=".85"/>
<circle cx="172.1" cy="77.7" r=".85"/>
<circle cx="174.6" cy="75.2" r=".85"/>
<circle cx="172.1" cy="75.2" r=".85"/>
<circle cx="174.6" cy="72.6" r=".85"/>
<circle cx="172.1" cy="72.6" r=".85"/>
<circle cx="174.6" cy="70.1" r=".85"/>
<circle cx="172.1" cy="70.1" r=".85"/>
<circle cx="174.6" cy="67.6" r=".85"/>
<circle cx="172.1" cy="67.6" r=".85"/>
<circle cx="174.6" cy="65" r=".85"/>
<circle cx="172.1" cy="65" r=".85"/>
<circle cx="94.6" cy="85.3" r=".85"/>
<circle cx="111.4" cy="85.7" r="2.2"/>
<circle cx="111.4" cy="67.3" r="2.2"/>
<circle cx="166.1" cy="67.3" r="2.2"/>
<circle cx="166.1" cy="85.7" r="2.2"/>
<circle cx="111.4" cy="72.6" r=".5"/>
<circle cx="111.4" cy="73.9" r=".5"/>
<circle cx="111.4" cy="75.2" r=".5"/>
<circle cx="111.4" cy="77.7" r=".5"/>
<circle cx="111.4" cy="79" r=".5"/>
<circle cx="94.6" cy="115.3" r=".5"/>
<circle cx="166.1" cy="141.2" r="2.2"/>
<circle cx="94.6" cy="105.8" r=".85"/>
<circle cx="94.6" cy="95.6" r=".85"/>
<circle cx="94.6" cy="122.8" r=".5"/>
<circle cx="138.4" cy="131.4" r=".3"/>
<circle cx="132.1" cy="141.2" r=".3"/>
<circle cx="137" cy="106.5" r=".3"/>
<circle cx="133.5" cy="82" r=".3"/>
<circle cx="142.1" cy="136.8" r=".3"/>
<circle cx="141.2" cy="116.8" r=".3"/>
<circle cx="151.3" cy="134.7" r=".3"/>
<circle cx="162.7" cy="139.9" r=".3"/>
<circle cx="154.6" cy="104.8" r=".3"/>
<circle cx="109.7" cy="137.4" r=".3"/>
<circle cx="121.8" cy="144.4" r=".3"/>
<circle cx="119.3" cy="118.9" r=".3"/>
<circle cx="146.8" cy="87.6" r=".3"/>
<circle cx="149" cy="81.8" r=".3"/>
<circle cx="100.3" cy="140.6" r=".3"/>
<circle cx="168.9" cy="104.4" r=".3"/>
<circle cx="100.1" cy="128.9" r=".3"/>
<circle cx="160.3" cy="139.6" r=".3"/>
<circle cx="154.1" cy="106" r=".3"/>
<circle cx="109.9" cy="114.2" r=".3"/>
<circle cx="159" cy="82.4" r=".3"/>
<circle cx="160.3" cy="66.5" r=".3"/>
<circle cx="160.7" cy="105.3" r=".3"/>
<circle cx="163.2" cy="136.9" r=".3"/>
<circle cx="112.9" cy="97.8" r=".3"/>
<circle cx="164.3" cy="74.4" r=".3"/>
<circle cx="140.1" cy="112" r=".3"/>
<circle cx="153" cy="119.1" r=".3"/>
<circle cx="128.9" cy="142.2" r=".3"/>
<circle cx="107.1" cy="87" r=".3"/>
<circle cx="135" cy="135.4" r=".3"/>
<circle cx="161.5" cy="87.6" r=".3"/>
<circle cx="124.8" cy="106.3" r=".3"/>
<circle cx="138.9" cy="122.2" r=".3"/>
<circle cx="131.8" cy="113.8" r=".3"/>
<circle cx="147.3" cy="94.2" r=".3"/>
<circle cx="98.2" cy="66.3" r=".3"/>
<circle cx="118.4" cy="136.8" r=".3"/>
<circle cx="152.7" cy="122.3" r=".3"/>
<circle cx="115.8" cy="113.3" r=".3"/>
<circle cx="115.7" cy="108.7" r=".3"/>
<circle cx="149" cy="141.9" r=".3"/>
<circle cx="141.5" cy="78.4" r=".3"/>
<circle cx="102.6" cy="109.8" r=".3"/>
<circle cx="166.1" cy="97.9" r=".3"/>
<circle cx="157.1" cy="136.1" r=".3"/>
<circle cx="106.7" cy="95" r=".3"/>
<circle cx="102.5" cy="115.9" r=".3"/>
<circle cx="161.8" cy="69.8" r=".3"/>
<circle cx="111.5" cy="105.4" r=".3"/>
<circle cx="100.8" cy="118" r=".3"/>
<circle cx="177.9" cy="75.2" r=".3"/>
<circle cx="102.5" cy="107.9" r=".3"/>
<circle cx="125.2" cy="99.4" r=".3"/>
<circle cx="125.3" cy="82.8" r=".3"/>
<circle cx="147.1" cy="96" r=".3"/>
<circle cx="159.5" cy="126.1" r=".3"/>
<circle cx="166.4" cy="96.5" r=".3"/>
<circle cx="124.2" cy="94.7" r=".3"/>
<circle cx="145.4" cy="139.4" r=".3"/>
<circle cx="151" cy="127.9" r=".3"/>
<circle cx="169.2" cy="137.7" r=".3"/>
<circle cx="162.3" cy="82.7" r=".3"/>
<circle cx="124.8" cy="104.6" r=".3"/>
<circle cx="168.3" cy="103" r=".3"/>
<circle cx="137" cy="121" r=".3"/>
<circle cx="168.9" cy="106" r=".3"/>
<circle cx="160.8" cy="110.7" r=".3"/>
<circle cx="150.1" cy="76.1" r=".3"/>
<circle cx="157.7" cy="118" r=".3"/>
<circle cx="106.3" cy="111.2" r=".3"/>
<circle cx="119.6" cy="75.8" r=".3"/>
<circle cx="99.1" cy="103.6" r=".3"/>
<circle cx="147.6" cy="142.5" r=".3"/>
<circle cx="147.8" cy="116.8" r=".3"/>
<circle cx="103.3" cy="126.7" r=".3"/>
<circle cx="121.4" cy="77.5" r=".3"/>
<circle cx="155.4" cy="129.2" r=".3"/>
<circle cx="121.9" cy="131.3" r=".3"/>
<circle cx="168.5" cy="117.9" r=".3"/>
<circle cx="117.2" cy="76.7" r=".3"/>
<circle cx="158.9" cy="108.6" r=".3"/>
<circle cx="160" cy="128.6" r=".3"/>
<circle cx="129.7" cy="87.2" r=".3"/>
<circle cx="148.7" cy="132.6" r=".3"/>
<circle cx="129.4" cy="84.4" r=".3"/>
<circle cx="125.5" cy="73.1" r=".3"/>
<circle cx="159.3" cy="144.3" r=".3"/>
<circle cx="113.3" cy="141.3" r=".3"/>
<circle cx="152.4" cy="131.8" r=".3"/>
<circle cx="111" cy="143.4" r=".3"/>
<circle cx="137.7" cy="80.1" r=".3"/>
<circle cx="158.9" cy="106.5" r=".3"/>
<circle cx="139.3" cy="104" r=".3"/>
<circle cx="103.6" cy="133.3" r=".3"/>
<circle cx="138.7" cy="116.5" r=".3"/>
<circle cx="146.9" cy="92.5" r=".3"/>
<circle cx="96.5" cy="138.2" r=".3"/>
<circle cx="131.2" cy="124.7" r=".3"/>
<circle cx="121.7" cy="86.7" r=".3"/>
<circle cx="168.4" cy="100.2" r=".3"/>
<circle cx="99.1" cy="105.9" r=".3"/>
<circle cx="158.5" cy="135" r=".3"/>
<circle cx="96.1" cy="127" r=".3"/>
<circle cx="152.7" cy="136" r=".3"/>
<circle cx="146.3" cy="101.7" r=".3"/>
<circle cx="152.3" cy="133.2" r=".3"/>
<circle cx="122.7" cy="85.3" r=".3"/>
<circle cx="115.3" cy="128.9" r=".3"/>
<circle cx="153.5" cy="107.4" r=".3"/>
<circle cx="98.9" cy="91.2" r=".3"/>
<circle cx="121.4" cy="74.2" r=".3"/>
<circle cx="142.4" cy="128.6" r=".3"/>
<circle cx="125" cy="113.9" r=".3"/>
<circle cx="135.3" cy="102.7" r=".3"/>
<circle cx="102.6" cy="99.1" r=".3"/>
<circle cx="136.9" cy="65.5" r=".3"/>
<circle cx="121.5" cy="110" r=".3"/>
<circle cx="147.1" cy="76.1" r=".3"/>
<circle cx="131.2" cy="141.6" r=".3"/>
<circle cx="141.5" cy="82.2" r=".3"/>
<circle cx="149.1" cy="72.3" r=".3"/>
<circle cx="100.1" cy="118.9" r=".3"/>
<circle cx="112.1" cy="125.9" r=".3"/>
<circle cx="133.7" cy="138.2" r=".3"/>
<circle cx="121" cy="126.2" r=".3"/>
<circle cx="118.5" cy="106" r=".3"/>
<circle cx="110.5" cy="119" r=".3"/>
<circle cx="116.2" cy="134.4" r=".3"/>
<circle cx="154.1" cy="139.3" r=".3"/>
<circle cx="154.7" cy="136" r=".3"/>
<circle cx="114" cy="143.3" r=".3"/>
<circle cx="124.8" cy="128.6" r=".3"/>
<circle cx="104.5" cy="83.2" r=".3"/>
<circle cx="146.2" cy="118" r=".3"/>
<circle cx="140.7" cy="98.2" r=".3"/>
<circle cx="113.2" cy="116.6" r=".3"/>
<circle cx="146.8" cy="84.6" r=".3"/>
<circle cx="123.4" cy="130" r=".3"/>
<circle cx="153" cy="112.9" r=".3"/>
<circle cx="166.8" cy="90.4" r=".3"/>
<circle cx="128.1" cy="125.7" r=".3"/>
<circle cx="121.3" cy="94.5" r=".3"/>
<circle cx="178.4" cy="104" r=".3"/>
<circle cx="98.4" cy="109.8" r=".3"/>
<circle cx="98.3" cy="142.1" r=".3"/>
<circle cx="109.6" cy="109.2" r=".3"/>
<circle cx="134.7" cy="118.4" r=".3"/>
<circle cx="115.7" cy="75.4" r=".3"/>
<circle cx="135.4" cy="132.2" r=".3"/>
<circle cx="134.2" cy="99.1" r=".3"/>
<circle cx="140.2" cy="100.1" r=".3"/>
<circle cx="136.1" cy="66.7" r=".3"/>
<circle cx="126.7" cy="80.3" r=".3"/>
<circle cx="133.5" cy="78.4" r=".3"/>
<circle cx="157.6" cy="76.3" r=".3"/>
<circle cx="124.3" cy="138" r=".3"/>
<circle cx="100.2" cy="104.9" r=".3"/>
<circle cx="160.8" cy="121.2" r=".3"/>
<circle cx="130.9" cy="93.2" r=".3"/>
<circle cx="124.8" cy="102.9" r=".3"/>
<circle cx="169.7" cy="97.4" r=".3"/>
<circle cx="138.6" cy="128.9" r=".3"/>
<circle cx="119.5" cy="98.5" r=".3"/>
<circle cx="97.3" cy="144.3" r=".3"/>
<circle cx="113" cy="112.1" r=".3"/>
<circle cx="160.1" cy="117" r=".3"/>
<circle cx="111" cy="90.5" r=".3"/>
<circle cx="147.1" cy="78.2" r=".3"/>
<circle cx="112" cy="109.2" r=".3"/>
<circle cx="152.4" cy="76.8" r=".3"/>
<circle cx="99.9" cy="137.9" r=".3"/>
<circle cx="130.9" cy="105.5" r=".3"/>
<circle cx="177.2" cy="142" r=".3"/>
<circle cx="115.1" cy="142" r=".3"/>
<circle cx="156.6" cy="89.3" r=".3"/>
<circle cx="140" cy="70.9" r=".3"/>
<circle cx="162.4" cy="104.9" r=".3"/>
<circle cx="160.9" cy="143.9" r=".3"/>
<circle cx="140" cy="107.8" r=".3"/>
<circle cx="107.3" cy="132.5" r=".3"/>
<circle cx="123.8" cy="86.8" r=".3"/>
<circle cx="137.7" cy="144.4" r=".3"/>
<circle cx="144.9" cy="69" r=".3"/>
<circle cx="116.6" cy="103.8" r=".3"/>
<circle cx="146.8" cy="141.3" r=".3"/>
<circle cx="142.6" cy="139.6" r=".3"/>
<circle cx="135.1" cy="128.6" r=".3"/>
<circle cx="103.1" cy="93.1" r=".3"/>
<circle cx="102.6" cy="101.7" r=".3"/>
<circle cx="152" cy="139.2" r=".3"/>
<circle cx="123.8" cy="136.9" r=".3"/>
<circle cx="157.6" cy="78.2" r=".3"/>
<circle cx="119.9" cy="84.4" r=".3"/>
<circle cx="149.1" cy="124.6" r=".3"/>
<circle cx="128.1" cy="119.5" r=".3"/>
<circle cx="146.3" cy="110" r=".3"/>
<circle cx="159.1" cy="85.3" r=".3"/>
<circle cx="128.8" cy="141.3" r=".3"/>
<circle cx="162.9" cy="119.5" r=".3"/>
<circle cx="138.4" cy="92.3" r=".3"/>
<circle cx="144.8" cy="142.5" r=".3"/>
<circle cx="118.9" cy="143.8" r=".3"/>
<circle cx="158.6" cy="139.8" r=".3"/>
<circle cx="161" cy="142.4" r=".3"/>
<circle cx="154.1" cy="133.3" r=".3"/>
<circle cx="103.1" cy="91.1" r=".3"/>
<circle cx="98.9" cy="104.8" r=".3"/>
<circle cx="98" cy="95.1" r=".3"/>
<circle cx="149" cy="122.9" r=".3"/>
<circle cx="153.7" cy="91.2" r=".3"/>
<circle cx="115.2" cy="137.7" r=".3"/>
<circle cx="121.2" cy="117.7" r=".3"/>
<circle cx="116.6" cy="106.8" r=".3"/>
<circle cx="157.2" cy="65.7" r=".4"/>
<circle cx="130.9" cy="104" r=".3"/>
<circle cx="133.5" cy="135.9" r=".3"/>
<circle cx="152.9" cy="111.6" r=".4"/>
<circle cx="140.6" cy="143.4" r=".4"/>
<circle cx="162.7" cy="129.7" r=".3"/>
<circle cx="153.4" cy="75.6" r=".3"/>
<circle cx="143.5" cy="71" r=".4"/>
<circle cx="149.6" cy="135.1" r=".3"/>
<circle cx="162.4" cy="105.9" r=".3"/>
<circle cx="162.7" cy="127.9" r=".3"/>
<circle cx="123.7" cy="114.4" r=".3"/>
<circle cx="163.6" cy="127.5" r=".3"/>
<circle cx="156.8" cy="117" r=".4"/>
<circle cx="104.4" cy="144.6" r=".4"/>
<circle cx="134.7" cy="119.5" r=".3"/>
<circle cx="162.7" cy="127" r=".3"/>
<circle cx="154.1" cy="131.4" r=".3"/>
<circle cx="164" cy="107.8" r=".3"/>
<circle cx="131.1" cy="74.3" r=".3"/>
<circle cx="152.7" cy="95.6" r=".4"/>
<circle cx="152" cy="130.7" r=".3"/>
<circle cx="163.6" cy="128.4" r=".3"/>
<circle cx="159" cy="133.8" r=".3"/>
<circle cx="163.6" cy="129.3" r=".3"/>
<circle cx="162.7" cy="126.1" r=".3"/>
<circle cx="131.4" cy="76.3" r=".3"/>
<circle cx="116.3" cy="84.3" r=".3"/>
<circle cx="156.5" cy="143.3" r=".4"/>
<circle cx="126.6" cy="109.8" r=".3"/>
<circle cx="124.5" cy="68.7" r=".4"/>
<circle cx="117.1" cy="126.7" r=".3"/>
<circle cx="125.5" cy="143.5" r=".4"/>
<circle cx="162.7" cy="128.8" r=".3"/>
<circle cx="109.2" cy="141.1" r=".4"/>
<circle cx="100.3" cy="112.3" r=".4"/>
<circle cx="99.9" cy="96.9" r=".4"/>
<circle cx="97.5" cy="115.1" r=".3"/>
<circle cx="101.5" cy="114.3" r=".3"/>
<circle cx="123.8" cy="82.7" r=".3"/>
<circle cx="125.3" cy="71.9" r=".3"/>
<circle cx="127.3" cy="139.2" r=".3"/>
<circle cx="124.1" cy="81.3" r=".3"/>
<circle cx="114.3" cy="77.3" r=".3"/>
<circle cx="135.9" cy="73.1" r=".3"/>
<circle cx="126" cy="85.7" r=".3"/>
<circle cx="131.2" cy="125.9" r=".3"/>
<circle cx="131.1" cy="73.5" r=".3"/>
<circle cx="157.2" cy="71.7" r=".3"/>
<circle cx="138.2" cy="71.6" r=".3"/>
<circle cx="157.7" cy="75.4" r=".3"/>
<circle cx="145.6" cy="70.2" r=".3"/>
<circle cx="138.9" cy="71.1" r=".3"/>
<circle cx="137.4" cy="72.1" r=".3"/>
<circle cx="119.5" cy="115.6" r=".3"/>
<circle cx="121" cy="113.9" r=".3"/>
<circle cx="119.6" cy="100.6" r=".3"/>
<circle cx="121" cy="102.5" r=".3"/>
<circle cx="133.1" cy="102.1" r=".3"/>
<circle cx="135.4" cy="108.7" r=".3"/>
<circle cx="132.7" cy="110.8" r=".3"/>
<circle cx="108.5" cy="119.6" r=".3"/>
<circle cx="112" cy="122" r=".3"/>
<circle cx="121.4" cy="114.8" r=".3"/>
<circle cx="134.4" cy="114.2" r=".3"/>
<circle cx="156.3" cy="122.2" r=".3"/>
<circle cx="157.5" cy="120.8" r=".3"/>
<circle cx="132.8" cy="112.4" r=".3"/>
<circle cx="100.6" cy="85.3" r=".3"/>
<circle cx="138.8" cy="74.9" r=".3"/>
<circle cx="100.5" cy="86.2" r=".3"/>
<circle cx="137.3" cy="75.5" r=".3"/>
<circle cx="125.6" cy="98" r=".3"/>
<circle cx="123.7" cy="109.5" r=".3"/>
<circle cx="124.8" cy="97.3" r=".3"/>
<circle cx="123" cy="108.6" r=".3"/>
<circle cx="125.2" cy="96.6" r=".3"/>
<circle cx="126.6" cy="81.3" r=".3"/>
<circle cx="127.4" cy="98.2" r=".3"/>
<circle cx="129" cy="111.2" r=".3"/>
<circle cx="136.7" cy="72.6" r=".3"/>
<circle cx="154.6" cy="75.6" r=".3"/>
<circle cx="131.1" cy="72.6" r=".3"/>
<circle cx="109.1" cy="79" r=".3"/>
<circle cx="127.1" cy="138.3" r=".3"/>
<circle cx="139.8" cy="136.9" r=".3"/>
<circle cx="165" cy="133.7" r=".3"/>
<circle cx="138.5" cy="138.2" r=".3"/>
<circle cx="157.2" cy="128.3" r=".3"/>
<circle cx="159" cy="127.9" r=".3"/>
<circle cx="137.3" cy="139.4" r=".3"/>
<circle cx="166.8" cy="133.7" r=".3"/>
<circle cx="157.5" cy="127.5" r=".3"/>
<circle cx="137.9" cy="138.8" r=".3"/>
<circle cx="140.7" cy="136.1" r=".3"/>
<circle cx="122" cy="116.1" r=".3"/>
<circle cx="115.8" cy="95.5" r=".3"/>
<circle cx="127.6" cy="112.1" r=".3"/>
<circle cx="102.1" cy="122.8" r=".3"/>
<circle cx="121.3" cy="119.9" r=".3"/>
<circle cx="135" cy="116.5" r=".3"/>
<circle cx="125.4" cy="86.7" r=".3"/>
<circle cx="155.1" cy="89.4" r=".3"/>
<circle cx="134.5" cy="92.7" r=".3"/>
<circle cx="132.6" cy="115.4" r=".3"/>
<circle cx="133.9" cy="92.3" r=".3"/>
<circle cx="139.4" cy="88.8" r=".3"/>
<circle cx="132.1" cy="114.8" r=".3"/>
<circle cx="96.2" cy="100.3" r=".3"/>
<circle cx="140.5" cy="139.4" r=".3"/>
<circle cx="141.2" cy="139.7" r=".3"/>
<circle cx="156.3" cy="128.6" r=".3"/>
<circle cx="139.2" cy="137.5" r=".3"/>
<circle cx="129.2" cy="117" r=".3"/>
<circle cx="128.3" cy="104.4" r=".3"/>
<circle cx="130.1" cy="130.4" r=".3"/>
<circle cx="123.6" cy="119.7" r=".3"/>
<circle cx="123.5" cy="118.9" r=".3"/>
<circle cx="128" cy="129.7" r=".3"/>
<circle cx="123.3" cy="118.1" r=".3"/>
<circle cx="157.1" cy="85.5" r=".3"/>
<circle cx="164.3" cy="90.3" r=".3"/>
<circle cx="152.9" cy="134.7" r=".3"/>
<circle cx="151.4" cy="80" r=".3"/>
<circle cx="161.8" cy="119.5" r=".3"/>
<circle cx="162.2" cy="117.7" r=".3"/>
</g>
<g fill="none" stroke="#b3ffb3" stroke-width=".25">
<path d="M92.2 73.5h2M94.2 67.8v4.1M106.7 77.6v1.2M107.8 76.5h3.6M108.1 77.2v2.3l.2 .2M111.4 79h2.9M111.4 73.9h1.4M114.2 68.4v5.9l.7 .7v4.5M116.3 65.9v1.1M116.3 68.3v8.2l-.6 .6v1.4M117 71.4v3.6M117.4 68.3l2-2.1h13.2l2 2v2.2l1.1 1.1h2.4l.1 .1"/>
<path d="M117.5 65.8h15.3l2.6 2.6v2l.6 .6h2.8l.1 .1M118.2 76.3v4.2l.3 .3v.1l1.1 1.1M118.2 78.5h1.3M120.6 69.2h-1.1v2.2M121.7 69.2h.5l2.1-2.1h7.1l.8 .8v1.5M123.1 75.1v.9l.2 .2h3.4M123.5 73.3v1.4M124.4 73.3v1.4M124.9 77.2h1.8M125.3 71.9h1.3M126.5 74.4h1.4M127.5 67.8h1.6"/>
<path d="M127.5 77.8l-6.1 6.1M127.6 71.9h2.1M128 73.5h3.1M128 74.3h3.1v1.6l.3 .4M128.1 75.9h1.6M128.3 79.1h1.4M128.4 76.7h1.3M128.5 79.9h1.2M128.7 77.5h1M129.7 78.3h-1.9l-1.7 1.7M129.7 71.1h3.2l2.1 2h.9M129.7 73.5h.1"/>
<path d="M130 67.8h1.2l.2 .2M131.1 72.6l-1.4 .1M133 69.4v.9l2.3 2.2h1.2l.2 .1M133.8 68.1l-1.4-1.4h-12.6l-1.6 1.5v3.2M133.8 69.4v.9l1.7 1.7h1.8l.1 .1M137 69.4v-.9l2.4-2.4h16.5l4.4 4.4v4.6l-2.2 2.2h-1.4l-.8 .9v1.5M137.8 69.4v-1.1l1.8-1.8h16.1l4.1 4.1v3.4M138.6 69.4v-1.3l1.2-1.1h15.7l3.6 3.6v3.4M139.4 69.4v-1.4l.6-.6h15.3l3.2 3.2v3.4M141.8 69.4v1.6l-4.5 4.5M142.6 69.4v1.7l-3.8 3.8M145.1 71.1h1.2"/>
<path d="M145.1 73.5h1.1l.6-.6h2.3l2.3 2.3v4.8M145.6 69.8l1.2-1.2h9l2 2v4.7l-.1 .1M147.1 79.8l-.1 .1M147.5 69.6h-.7l-.4 .4M150.3 71.3h1.3M153.9 74h.1M153.9 72.3v2.8l-.5 .5M153.9 79.7v1.1l2.7 2.6h.4M154.6 73.1v.9M154.6 79.7v.8l1.6 1.7M154.9 70.7v2.1M155.2 74v.9l-.6 .7"/>
<path d="M155.9 72.2v3.1l-3.8 3.7v1.1l-2 2.1v2.1l1.3 1.3v1.7M156.5 72.4v2.8l-3.8 3.9v4.3M160.5 75.7l-2 2v2M162.8 73.9l.4 .4M163.2 77.9v-.9l-.2-.1h-2.3l-1.6 1.6v2.6l.2 .2M179.1 65.7v3.6M94.6 85.3h3.1M97.7 86.7h-.5l-.8 .8v1.1l-1.8 1.8M98.5 97.1h.1M98.7 85.3h1.9M100.5 86.2h-1.3l-.5 .5M103 80.8h5.3"/>
<path d="M113.5 88.8h-13.9l-1.7 1.6v2.4l2.4 2.4-2.4 2.4v10.5l2.4 2.4-1.9 1.9v27.8l3.6 3.6h1.9l2-2.1 2.7 2.7h10.7l2.6-2.7 2.7 2.7h11.8l1.5-1.5M113.7 89.2h-12.2l-1.2 1.2v2.3l1.6 1.5v12.2l-1.6 1.5 1.7 1.7v4.2l-.5 .5v25.6l1.9 1.8 1.5-1.5h13l1.5 1.5 1.5-1.5h13l1.5 1.5 1.4-1.4h11.8l1.4 1.4h1.4l1.2-1.2v-1.2l8.3-8.2v-8.7l-8.9-8.9v-12.5l.3-.3h1.4M118.1 97.8h2.9l.8 .8h1.8M121.4 86l-2.2 2.2h-5M123.6 99.3h-1.6l-2.5 2.4v11.2l-.1 .1h-1.3M123.6 99.9h-1.6l-2 2v11.6l-.9 .8h-5.3l-5.3 5.3M123.6 98h2M123.6 97.3h1.2M126.1 80.4l-2.3 2.3v2.9l-3 3h-6.5M127.4 99.3l.6 .6h1.4M128.7 81.5h1M128.7 82.3h1"/>
<path d="M129.4 99.3h.9l.1 .1h3l1.3 1.2v8.3l2.3 2.3M129.4 98.6v.1h1.1M129.4 98h1.8h.1M129.7 83.1h-2.3l-.5 .5v1.2l-.9 .9M129.7 80.7h-2.5l-.6 .6M132 96.4l-1 .9h-1.6M133 84.8v1.3l-3 2.9h-15.1l-11.5 11.6v23.3M133.8 84.8v1.2l-3.5 3.5h-15.1l-11.3 11.3v18.7l2 2v2.4M134.6 84.8v1.2l-4 3.9h-15l-11.1 11.1v18.3l1.6 1.6h11.8l1.5 1.5v1.5M135.4 84.8v1.2l-4.4 4.4h-15.1l-10.9 10.9v17.7l1.4 1.3h13.2l2.3 2.4v1.2M135.9 95.6h-1.5l-.7 .7v2.1l-.5 .5h-2.4M135.9 93.1h-.9l-1.9 1.9v2.8"/>
<path d="M136.2 84.8v1.3l-4.7 4.7h-15.3l-10.7 10.7v6.7l2.3 2.3h10.3M137 84.8v1.3l-5.2 5.2h-15.3l-10.5 10.5v4.5l1.7 1.6h10.4M137.8 84.8v1.4l-5.5 5.5h-10.8l-1 1h-2.4M138.6 84.8v1.5l-5.9 5.9h-10l-3.1 3h-1.5M140.2 84.8v10.6l-2.8 2.8h-1.5M141 84.8v11l-1.7 1.7v1.7l-1.5 1.5h-1.9M141.8 84.8v24.2l-4.8 4.8M142.6 84.8v25.9l-5.6 5.6M143.4 84.8v28.2l-8 8v2.9M145.1 81.5h2.2l2.1 2v34.4l4.5 4.5v1.5M145.1 83.1v1.7l-1 1v29.7l-6.2 6.2v2.2M145.1 82.3h2.2l1.4 1.4v34.3l2.7 2.6v3.3"/>
<path d="M147 80.7h.1M150.1 85.6v3.2l.6 .6h2.7l.5-.5v-1.6M152.7 85.8v1.5M153.7 98.2h1.2l.8 .7v7l1.4 1.4v4.2l-2.3 2.3M157 84.5v.9l.1 .1M157.7 82.2l.4 .3v.9M158.1 84.5v1.1l2.4 2.4v4.3M158.5 81l-.3 .3M161.6 99.2l.2 .1M161.8 90.3v3.2l-1.3 1.2v2.5M164.3 90.3v2M94.6 117.8h3.8"/>
<path d="M97.5 115.1l-.3 .2h-2.6M118.1 115.6h1.4M118.1 100.3h1.3l.2 .3M121 102.5v5.6l2.1 2.1h1.9M123 108.6l.2 .2 1.8 .1M123.6 100.6h-1.7l-1.5 1.5v18.2M123.7 109.5h1.3M125 111.5h-2.2l-.8 .8v1.9l-.6 .6M125 110.8h-2.5l-1.5 1.5v1.6M125 112.1h-1.9l-.4 .4v4l4.3 4.3v3.1M129 111.2l.2 .3h1.6M129.4 101.2h3.9l.4 .4v23l1.1 1.1h5.2l.5-.5v-1.3"/>
<path d="M129.4 100.6h4.2l.6 .6v12.8l.2 .2M130.8 108.9h-3.3l-.9 .9M130.8 112.1h1.9l.1 .3M130.8 112.8h1.3l1.2 1.2v10.8l1.3 1.4h7.6l.8-.9v-1.4M130.9 104l1.4 1.4v2.5M132.5 108.1l-.8 .8M132.5 109.1l-.5 .4M132.5 110.1v.1M132.8 110.8h-2M133.1 102.1l.1 .1v7.6l-.3 .3-2.1 .1M137 108.7h-1.6M154.8 113.8l7 7v1.2l-.4 .4v11.8l-7.5 7.5v1.7l-1 1h-13.5l-1.5-1.5"/>
<path d="M154.8 113.8h.1M159.6 101.3v.6l.5 .6h1.4l1.3 1.3M160.8 113.8h-2.2M163.7 103.8l6.4 6.3v1.1l2 2.1M164.1 103.5l6.4 6.4v1.2l1 .9h1.9l1.2 1.3M167.1 109.2v2.3M92.2 137l2 .1v3.9M94.2 135.4l-2 .1M94.6 122.8h2.3M94.6 122.8h.1M96.9 123.8l-.3 .3h-2M108.5 121.7v2.2"/>
<path d="M111.6 122l-.6 .7v1.2M120.8 120.6h2l1.7 1.7v1.6M157.5 120.8l1.4 1.4v1.6l.1 .1M165.2 124v2.4M166.1 128.6v.8M167 131.2h-1.3M167 130v.2M167.1 123.7v2.7M168.6 128.5l-1.5 .1v1.5M123.7 143.5v.1M137.9 141.7v1.2M179.1 140.7v3.7"/>
</g>
<g fill="none" stroke="#b3ffb3" stroke-width=".35">
<path d="M101.7 79.7h3M104.7 79.7v.1M105.5 78l-.8 .8v1M145.1 79.9h1.9M148 74.2h1.3M99.9 96.9l.4 .4v.5M116.7 80.9l-.1 3.1-.3 .3M129.4 97.3h-2.1l-.8 .8v2l-1.1 1.1h-1.8M145.1 80.7h1.9M147.1 80.7h1M148.6 80.2h1.7M152.7 95.6h1"/>
<path d="M159.1 97.2h1.4M161.8 90.3h.9M100.3 112.3v.7M126.6 109.8v2.6l-.4 .4h-2.2l-.3 .2v1.4M154.8 111.2h-1.5l-.4 .4M156.3 122.2v1.6l.2 .1M109.2 141.1h-.1l-.6 .6M124.5 141.7v1.3l.5 .5h.5M140.5 141.7v1.6l.1 .1M156.5 141.7v1.6"/>
</g>
<path d="M94.9 118.9h1.7" fill="none" stroke="#b3ffb3" stroke-width=".2"/>
<g fill="#fff" stroke="#fff" stroke-width=".14">
<circle cx="138.4" cy="131.4" r=".15"/>
<circle cx="132.1" cy="141.2" r=".15"/>
<circle cx="137" cy="106.5" r=".15"/>
<circle cx="133.5" cy="82" r=".15"/>
<circle cx="142.1" cy="136.8" r=".15"/>
<circle cx="141.2" cy="116.8" r=".15"/>
<circle cx="151.3" cy="134.7" r=".15"/>
<circle cx="162.7" cy="139.9" r=".15"/>
<circle cx="154.6" cy="104.8" r=".15"/>
<circle cx="109.7" cy="137.4" r=".15"/>
<circle cx="121.8" cy="144.4" r=".15"/>
<circle cx="119.3" cy="118.9" r=".15"/>
<circle cx="146.8" cy="87.6" r=".15"/>
<circle cx="100.3" cy="140.6" r=".15"/>
<circle cx="168.9" cy="104.4" r=".15"/>
<circle cx="100.1" cy="128.9" r=".15"/>
<circle cx="160.3" cy="139.6" r=".15"/>
<circle cx="154.1" cy="106" r=".15"/>
<circle cx="109.9" cy="114.2" r=".15"/>
<circle cx="160.3" cy="66.5" r=".15"/>
<circle cx="160.7" cy="105.3" r=".15"/>
<circle cx="163.2" cy="136.9" r=".15"/>
<circle cx="140.1" cy="112" r=".15"/>
<circle cx="153" cy="119.1" r=".15"/>
<circle cx="128.9" cy="142.2" r=".15"/>
<circle cx="107.1" cy="87" r=".15"/>
<circle cx="135" cy="135.4" r=".15"/>
<circle cx="161.5" cy="87.6" r=".15"/>
<circle cx="138.9" cy="122.2" r=".15"/>
<circle cx="131.8" cy="113.8" r=".15"/>
<circle cx="147.3" cy="94.2" r=".15"/>
<circle cx="98.2" cy="66.3" r=".15"/>
<circle cx="118.4" cy="136.8" r=".15"/>
<circle cx="152.7" cy="122.3" r=".15"/>
<circle cx="115.8" cy="113.3" r=".15"/>
<circle cx="115.7" cy="108.7" r=".15"/>
<circle cx="149" cy="141.9" r=".15"/>
<circle cx="141.5" cy="78.4" r=".15"/>
<circle cx="102.6" cy="109.8" r=".15"/>
<circle cx="166.1" cy="97.9" r=".15"/>
<circle cx="157.1" cy="136.1" r=".15"/>
<circle cx="106.7" cy="95" r=".15"/>
<circle cx="102.5" cy="115.9" r=".15"/>
<circle cx="161.8" cy="69.8" r=".15"/>
<circle cx="111.5" cy="105.4" r=".15"/>
<circle cx="100.8" cy="118" r=".15"/>
<circle cx="177.9" cy="75.2" r=".15"/>
<circle cx="102.5" cy="107.9" r=".15"/>
<circle cx="125.2" cy="99.4" r=".15"/>
<circle cx="125.3" cy="82.8" r=".15"/>
<circle cx="147.1" cy="96" r=".15"/>
<circle cx="159.5" cy="126.1" r=".15"/>
<circle cx="166.4" cy="96.5" r=".15"/>
<circle cx="145.4" cy="139.4" r=".15"/>
<circle cx="151" cy="127.9" r=".15"/>
<circle cx="169.2" cy="137.7" r=".15"/>
<circle cx="162.3" cy="82.7" r=".15"/>
<circle cx="124.8" cy="104.6" r=".15"/>
<circle cx="168.3" cy="103" r=".15"/>
<circle cx="137" cy="121" r=".15"/>
<circle cx="168.9" cy="106" r=".15"/>
<circle cx="160.8" cy="110.7" r=".15"/>
<circle cx="150.1" cy="76.1" r=".15"/>
<circle cx="157.7" cy="118" r=".15"/>
<circle cx="106.3" cy="111.2" r=".15"/>
<circle cx="119.6" cy="75.8" r=".15"/>
<circle cx="99.1" cy="103.6" r=".15"/>
<circle cx="147.6" cy="142.5" r=".15"/>
<circle cx="147.8" cy="116.8" r=".15"/>
<circle cx="103.3" cy="126.7" r=".15"/>
<circle cx="121.4" cy="77.5" r=".15"/>
<circle cx="155.4" cy="129.2" r=".15"/>
<circle cx="121.9" cy="131.3" r=".15"/>
<circle cx="168.5" cy="117.9" r=".15"/>
<circle cx="117.2" cy="76.7" r=".15"/>
<circle cx="158.9" cy="108.6" r=".15"/>
<circle cx="129.7" cy="87.2" r=".15"/>
<circle cx="148.7" cy="132.6" r=".15"/>
<circle cx="129.4" cy="84.4" r=".15"/>
<circle cx="125.5" cy="73.1" r=".15"/>
<circle cx="159.3" cy="144.3" r=".15"/>
<circle cx="113.3" cy="141.3" r=".15"/>
<circle cx="152.4" cy="131.8" r=".15"/>
<circle cx="111" cy="143.4" r=".15"/>
<circle cx="137.7" cy="80.1" r=".15"/>
<circle cx="158.9" cy="106.5" r=".15"/>
<circle cx="139.3" cy="104" r=".15"/>
<circle cx="103.6" cy="133.3" r=".15"/>
<circle cx="138.7" cy="116.5" r=".15"/>
<circle cx="146.9" cy="92.5" r=".15"/>
<circle cx="96.5" cy="138.2" r=".15"/>
<circle cx="131.2" cy="124.7" r=".15"/>
<circle cx="121.7" cy="86.7" r=".15"/>
<circle cx="168.4" cy="100.2" r=".15"/>
<circle cx="99.1" cy="105.9" r=".15"/>
<circle cx="158.5" cy="135" r=".15"/>
<circle cx="96.1" cy="127" r=".15"/>
<circle cx="152.7" cy="136" r=".15"/>
<circle cx="146.3" cy="101.7" r=".15"/>
<circle cx="152.3" cy="133.2" r=".15"/>
<circle cx="122.7" cy="85.3" r=".15"/>
<circle cx="115.3" cy="128.9" r=".15"/>
<circle cx="153.5" cy="107.4" r=".15"/>
<circle cx="98.9" cy="91.2" r=".15"/>
<circle cx="121.4" cy="74.2" r=".15"/>
<circle cx="142.4" cy="128.6" r=".15"/>
<circle cx="125" cy="113.9" r=".15"/>
<circle cx="135.3" cy="102.7" r=".15"/>
<circle cx="102.6" cy="99.1" r=".15"/>
<circle cx="136.9" cy="65.5" r=".15"/>
<circle cx="121.5" cy="110" r=".15"/>
<circle cx="147.1" cy="76.1" r=".15"/>
<circle cx="131.2" cy="141.6" r=".15"/>
<circle cx="141.5" cy="82.2" r=".15"/>
<circle cx="100.1" cy="118.9" r=".15"/>
<circle cx="112.1" cy="125.9" r=".15"/>
<circle cx="133.7" cy="138.2" r=".15"/>
<circle cx="121" cy="126.2" r=".15"/>
<circle cx="118.5" cy="106" r=".15"/>
<circle cx="110.5" cy="119" r=".15"/>
<circle cx="116.2" cy="134.4" r=".15"/>
<circle cx="154.1" cy="139.3" r=".15"/>
<circle cx="154.7" cy="136" r=".15"/>
<circle cx="114" cy="143.3" r=".15"/>
<circle cx="124.8" cy="128.6" r=".15"/>
<circle cx="104.5" cy="83.2" r=".15"/>
<circle cx="146.2" cy="118" r=".15"/>
<circle cx="140.7" cy="98.2" r=".15"/>
<circle cx="146.8" cy="84.6" r=".15"/>
<circle cx="123.4" cy="130" r=".15"/>
<circle cx="153" cy="112.9" r=".15"/>
<circle cx="166.8" cy="90.4" r=".15"/>
<circle cx="128.1" cy="125.7" r=".15"/>
<circle cx="121.3" cy="94.5" r=".15"/>
<circle cx="178.4" cy="104" r=".15"/>
<circle cx="98.4" cy="109.8" r=".15"/>
<circle cx="98.3" cy="142.1" r=".15"/>
<circle cx="109.6" cy="109.2" r=".15"/>
<circle cx="134.7" cy="118.4" r=".15"/>
<circle cx="115.7" cy="75.4" r=".15"/>
<circle cx="135.4" cy="132.2" r=".15"/>
<circle cx="134.2" cy="99.1" r=".15"/>
<circle cx="140.2" cy="100.1" r=".15"/>
<circle cx="136.1" cy="66.7" r=".15"/>
<circle cx="126.7" cy="80.3" r=".15"/>
<circle cx="133.5" cy="78.4" r=".15"/>
<circle cx="157.6" cy="76.3" r=".15"/>
<circle cx="124.3" cy="138" r=".15"/>
<circle cx="100.2" cy="104.9" r=".15"/>
<circle cx="160.8" cy="121.2" r=".15"/>
<circle cx="130.9" cy="93.2" r=".15"/>
<circle cx="124.8" cy="102.9" r=".15"/>
<circle cx="138.6" cy="128.9" r=".15"/>
<circle cx="119.5" cy="98.5" r=".15"/>
<circle cx="113" cy="112.1" r=".15"/>
<circle cx="160.1" cy="117" r=".15"/>
<circle cx="111" cy="90.5" r=".15"/>
<circle cx="147.1" cy="78.2" r=".15"/>
<circle cx="112" cy="109.2" r=".15"/>
<circle cx="152.4" cy="76.8" r=".15"/>
<circle cx="99.9" cy="137.9" r=".15"/>
<circle cx="130.9" cy="105.5" r=".15"/>
<circle cx="177.2" cy="142" r=".15"/>
<circle cx="115.1" cy="142" r=".15"/>
<circle cx="156.6" cy="89.3" r=".15"/>
<circle cx="140" cy="70.9" r=".15"/>
<circle cx="162.4" cy="104.9" r=".15"/>
<circle cx="160.9" cy="143.9" r=".15"/>
<circle cx="140" cy="107.8" r=".15"/>
<circle cx="123.8" cy="86.8" r=".15"/>
<circle cx="137.7" cy="144.4" r=".15"/>
<circle cx="144.9" cy="69" r=".15"/>
<circle cx="116.6" cy="103.8" r=".15"/>
<circle cx="146.8" cy="141.3" r=".15"/>
<circle cx="142.6" cy="139.6" r=".15"/>
<circle cx="135.1" cy="128.6" r=".15"/>
<circle cx="103.1" cy="93.1" r=".15"/>
<circle cx="102.6" cy="101.7" r=".15"/>
<circle cx="152" cy="139.2" r=".15"/>
<circle cx="157.6" cy="78.2" r=".15"/>
<circle cx="119.9" cy="84.4" r=".15"/>
<circle cx="128.1" cy="119.5" r=".15"/>
<circle cx="146.3" cy="110" r=".15"/>
<circle cx="128.8" cy="141.3" r=".15"/>
<circle cx="162.9" cy="119.5" r=".15"/>
<circle cx="138.4" cy="92.3" r=".15"/>
<circle cx="144.8" cy="142.5" r=".15"/>
<circle cx="118.9" cy="143.8" r=".15"/>
<circle cx="158.6" cy="139.8" r=".15"/>
<circle cx="161" cy="142.4" r=".15"/>
<circle cx="154.1" cy="133.3" r=".15"/>
<circle cx="103.1" cy="91.1" r=".15"/>
<circle cx="98.9" cy="104.8" r=".15"/>
<circle cx="98" cy="95.1" r=".15"/>
<circle cx="149" cy="122.9" r=".15"/>
<circle cx="153.7" cy="91.2" r=".15"/>
<circle cx="115.2" cy="137.7" r=".15"/>
<circle cx="121.2" cy="117.7" r=".15"/>
<circle cx="116.6" cy="106.8" r=".15"/>
<circle cx="157.2" cy="65.7" r=".2"/>
<circle cx="130.9" cy="104" r=".15"/>
<circle cx="133.5" cy="135.9" r=".15"/>
<circle cx="152.9" cy="111.6" r=".2"/>
<circle cx="140.6" cy="143.4" r=".2"/>
<circle cx="162.7" cy="129.7" r=".15"/>
<circle cx="153.4" cy="75.6" r=".15"/>
<circle cx="143.5" cy="71" r=".2"/>
<circle cx="149.6" cy="135.1" r=".15"/>
<circle cx="162.4" cy="105.9" r=".15"/>
<circle cx="162.7" cy="127.9" r=".15"/>
<circle cx="123.7" cy="114.4" r=".15"/>
<circle cx="163.6" cy="127.5" r=".15"/>
<circle cx="156.8" cy="117" r=".2"/>
<circle cx="104.4" cy="144.6" r=".2"/>
<circle cx="134.7" cy="119.5" r=".15"/>
<circle cx="162.7" cy="127" r=".15"/>
<circle cx="154.1" cy="131.4" r=".15"/>
<circle cx="164" cy="107.8" r=".15"/>
<circle cx="131.1" cy="74.3" r=".15"/>
<circle cx="152.7" cy="95.6" r=".2"/>
<circle cx="152" cy="130.7" r=".15"/>
<circle cx="163.6" cy="128.4" r=".15"/>
<circle cx="159" cy="133.8" r=".15"/>
<circle cx="163.6" cy="129.3" r=".15"/>
<circle cx="162.7" cy="126.1" r=".15"/>
<circle cx="131.4" cy="76.3" r=".15"/>
<circle cx="116.3" cy="84.3" r=".15"/>
<circle cx="156.5" cy="143.3" r=".2"/>
<circle cx="126.6" cy="109.8" r=".15"/>
<circle cx="124.5" cy="68.7" r=".2"/>
<circle cx="117.1" cy="126.7" r=".15"/>
<circle cx="125.5" cy="143.5" r=".2"/>
<circle cx="162.7" cy="128.8" r=".15"/>
<circle cx="109.2" cy="141.1" r=".2"/>
<circle cx="100.3" cy="112.3" r=".2"/>
<circle cx="99.9" cy="96.9" r=".2"/>
<circle cx="97.5" cy="115.1" r=".15"/>
<circle cx="101.5" cy="114.3" r=".15"/>
<circle cx="123.8" cy="82.7" r=".15"/>
<circle cx="125.3" cy="71.9" r=".15"/>
<circle cx="127.3" cy="139.2" r=".15"/>
<circle cx="124.1" cy="81.3" r=".15"/>
<circle cx="135.9" cy="73.1" r=".15"/>
<circle cx="126" cy="85.7" r=".15"/>
<circle cx="131.2" cy="125.9" r=".15"/>
<circle cx="131.1" cy="73.5" r=".15"/>
<circle cx="157.2" cy="71.7" r=".15"/>
<circle cx="138.2" cy="71.6" r=".15"/>
<circle cx="157.7" cy="75.4" r=".15"/>
<circle cx="145.6" cy="70.2" r=".15"/>
<circle cx="138.9" cy="71.1" r=".15"/>
<circle cx="137.4" cy="72.1" r=".15"/>
<circle cx="119.5" cy="115.6" r=".15"/>
<circle cx="121" cy="113.9" r=".15"/>
<circle cx="119.6" cy="100.6" r=".15"/>
<circle cx="121" cy="102.5" r=".15"/>
<circle cx="133.1" cy="102.1" r=".15"/>
<circle cx="135.4" cy="108.7" r=".15"/>
<circle cx="132.7" cy="110.8" r=".15"/>
<circle cx="108.5" cy="119.6" r=".15"/>
<circle cx="112" cy="122" r=".15"/>
<circle cx="121.4" cy="114.8" r=".15"/>
<circle cx="134.4" cy="114.2" r=".15"/>
<circle cx="156.3" cy="122.2" r=".15"/>
<circle cx="157.5" cy="120.8" r=".15"/>
<circle cx="132.8" cy="112.4" r=".15"/>
<circle cx="100.6" cy="85.3" r=".15"/>
<circle cx="138.8" cy="74.9" r=".15"/>
<circle cx="100.5" cy="86.2" r=".15"/>
<circle cx="137.3" cy="75.5" r=".15"/>
<circle cx="125.6" cy="98" r=".15"/>
<circle cx="123.7" cy="109.5" r=".15"/>
<circle cx="124.8" cy="97.3" r=".15"/>
<circle cx="123" cy="108.6" r=".15"/>
<circle cx="125.2" cy="96.6" r=".15"/>
<circle cx="126.6" cy="81.3" r=".15"/>
<circle cx="136.7" cy="72.6" r=".15"/>
<circle cx="154.6" cy="75.6" r=".15"/>
<circle cx="131.1" cy="72.6" r=".15"/>
<circle cx="127.1" cy="138.3" r=".15"/>
<circle cx="139.8" cy="136.9" r=".15"/>
<circle cx="165" cy="133.7" r=".15"/>
<circle cx="138.5" cy="138.2" r=".15"/>
<circle cx="157.2" cy="128.3" r=".15"/>
<circle cx="159" cy="127.9" r=".15"/>
<circle cx="137.3" cy="139.4" r=".15"/>
<circle cx="166.8" cy="133.7" r=".15"/>
<circle cx="157.5" cy="127.5" r=".15"/>
<circle cx="137.9" cy="138.8" r=".15"/>
<circle cx="140.7" cy="136.1" r=".15"/>
<circle cx="122" cy="116.1" r=".15"/>
<circle cx="115.8" cy="95.5" r=".15"/>
<circle cx="127.6" cy="112.1" r=".15"/>
<circle cx="102.1" cy="122.8" r=".15"/>
<circle cx="121.3" cy="119.9" r=".15"/>
<circle cx="135" cy="116.5" r=".15"/>
<circle cx="125.4" cy="86.7" r=".15"/>
<circle cx="155.1" cy="89.4" r=".15"/>
<circle cx="134.5" cy="92.7" r=".15"/>
<circle cx="132.6" cy="115.4" r=".15"/>
<circle cx="133.9" cy="92.3" r=".15"/>
<circle cx="139.4" cy="88.8" r=".15"/>
<circle cx="132.1" cy="114.8" r=".15"/>
<circle cx="96.2" cy="100.3" r=".15"/>
<circle cx="140.5" cy="139.4" r=".15"/>
<circle cx="141.2" cy="139.7" r=".15"/>
<circle cx="156.3" cy="128.6" r=".15"/>
<circle cx="139.2" cy="137.5" r=".15"/>
<circle cx="129.2" cy="117" r=".15"/>
<circle cx="128.3" cy="104.4" r=".15"/>
<circle cx="130.1" cy="130.4" r=".15"/>
<circle cx="123.6" cy="119.7" r=".15"/>
<circle cx="123.5" cy="118.9" r=".15"/>
<circle cx="123.3" cy="118.1" r=".15"/>
<circle cx="157.1" cy="85.5" r=".15"/>
<circle cx="164.3" cy="90.3" r=".15"/>
<circle cx="152.9" cy="134.7" r=".15"/>
<circle cx="151.4" cy="80" r=".15"/>
<circle cx="161.8" cy="119.5" r=".15"/>
<circle cx="162.2" cy="117.7" r=".15"/>
<circle cx="179.7" cy="145" r="1.6"/>
<circle cx="179.7" cy="65" r="1.6"/>
<circle cx="94" cy="67.6" r="1.6"/>
<circle cx="94" cy="141.2" r="1.6"/>
<circle cx="174.6" cy="143.8" r=".5"/>
<circle cx="172.1" cy="143.8" r=".5"/>
<circle cx="174.6" cy="141.2" r=".5"/>
<circle cx="172.1" cy="141.2" r=".5"/>
<circle cx="174.6" cy="138.7" r=".5"/>
<circle cx="172.1" cy="138.7" r=".5"/>
<circle cx="174.6" cy="136.1" r=".5"/>
<circle cx="172.1" cy="136.1" r=".5"/>
<circle cx="174.6" cy="133.6" r=".5"/>
<circle cx="172.1" cy="133.6" r=".5"/>
<circle cx="174.6" cy="131.1" r=".5"/>
<circle cx="172.1" cy="131.1" r=".5"/>
<circle cx="174.6" cy="128.5" r=".5"/>
<circle cx="172.1" cy="128.5" r=".5"/>
<circle cx="174.6" cy="126" r=".5"/>
<circle cx="172.1" cy="126" r=".5"/>
<circle cx="174.6" cy="123.4" r=".5"/>
<circle cx="172.1" cy="123.4" r=".5"/>
<circle cx="174.6" cy="120.9" r=".5"/>
<circle cx="172.1" cy="120.9" r=".5"/>
<circle cx="174.6" cy="118.4" r=".5"/>
<circle cx="172.1" cy="118.4" r=".5"/>
<circle cx="174.6" cy="115.8" r=".5"/>
<circle cx="172.1" cy="115.8" r=".5"/>
<circle cx="174.6" cy="113.3" r=".5"/>
<circle cx="172.1" cy="113.3" r=".5"/>
<circle cx="174.6" cy="110.7" r=".5"/>
<circle cx="172.1" cy="110.7" r=".5"/>
<circle cx="174.6" cy="108.2" r=".5"/>
<circle cx="172.1" cy="108.2" r=".5"/>
<circle cx="174.6" cy="105.7" r=".5"/>
<circle cx="172.1" cy="105.7" r=".5"/>
<circle cx="174.6" cy="103.1" r=".5"/>
<circle cx="172.1" cy="103.1" r=".5"/>
<circle cx="174.6" cy="100.6" r=".5"/>
<circle cx="172.1" cy="100.6" r=".5"/>
<circle cx="174.6" cy="98" r=".5"/>
<circle cx="172.1" cy="98" r=".5"/>
<circle cx="174.6" cy="95.5" r=".5"/>
<circle cx="172.1" cy="95.5" r=".5"/>
<circle cx="174.6" cy="93" r=".5"/>
<circle cx="172.1" cy="93" r=".5"/>
<circle cx="174.6" cy="90.4" r=".5"/>
<circle cx="172.1" cy="90.4" r=".5"/>
<circle cx="174.6" cy="87.9" r=".5"/>
<circle cx="172.1" cy="87.9" r=".5"/>
<circle cx="174.6" cy="85.3" r=".5"/>
<circle cx="172.1" cy="85.3" r=".5"/>
<circle cx="174.6" cy="82.8" r=".5"/>
<circle cx="172.1" cy="82.8" r=".5"/>
<circle cx="174.6" cy="80.3" r=".5"/>
<circle cx="172.1" cy="80.3" r=".5"/>
<circle cx="174.6" cy="77.7" r=".5"/>
<circle cx="172.1" cy="77.7" r=".5"/>
<circle cx="174.6" cy="75.2" r=".5"/>
<circle cx="172.1" cy="75.2" r=".5"/>
<circle cx="174.6" cy="72.6" r=".5"/>
<circle cx="172.1" cy="72.6" r=".5"/>
<circle cx="174.6" cy="70.1" r=".5"/>
<circle cx="172.1" cy="70.1" r=".5"/>
<circle cx="174.6" cy="67.6" r=".5"/>
<circle cx="172.1" cy="67.6" r=".5"/>
<circle cx="174.6" cy="65" r=".5"/>
<circle cx="172.1" cy="65" r=".5"/>
<circle cx="94.6" cy="90.4" r=".5"/>
<circle cx="94.6" cy="85.3" r=".5"/>
<circle cx="111.4" cy="85.7" r="1.1"/>
<circle cx="111.4" cy="67.3" r="1.1"/>
<circle cx="166.1" cy="67.3" r="1.1"/>
<circle cx="166.1" cy="85.7" r="1.1"/>
<circle cx="111.4" cy="72.6" r=".33"/>
<circle cx="111.4" cy="73.9" r=".33"/>
<circle cx="111.4" cy="75.2" r=".33"/>
<circle cx="111.4" cy="77.7" r=".33"/>
<circle cx="111.4" cy="79" r=".33"/>
<circle cx="111.4" cy="80.3" r=".33"/>
<circle cx="94.6" cy="119.1" r=".33"/>
<circle cx="94.6" cy="115.3" r=".33"/>
<circle cx="166.1" cy="141.2" r="1.1"/>
<circle cx="94.6" cy="110.9" r=".5"/>
<circle cx="94.6" cy="105.8" r=".5"/>
<circle cx="94.6" cy="100.7" r=".5"/>
<circle cx="94.6" cy="95.6" r=".5"/>
<circle cx="94.6" cy="125.3" r=".33"/>
<circle cx="94.6" cy="122.8" r=".33"/>
</g>
<g fill="#ff8a8a" stroke="#ff8a8a" stroke-width=".14">
<path d="M128.5 101h1.4l.1 .3-1.4 .1z"/>
<path d="M128.5 100.4h1.4l.1 .3h-1.4z"/>
<path d="M128.5 99.7h1.4l.1 .3-1.4 .1z"/>
<path d="M128.5 99.1h1.4l.1 .3h-1.4z"/>
<path d="M128.5 98.4h1.4l.1 .3-1.4 .1z"/>
<path d="M128.5 97.8h1.4l.1 .3h-1.4z"/>
<path d="M128.5 97.1h1.4l.1 .3-1.4 .1z"/>
<path d="M128.5 96.5h1.4l.1 .3h-1.4z"/>
<path d="M122.8 96.5h1.4v.3h-1.4z"/>
<path d="M122.8 97.1h1.4v.3l-1.4 .1z"/>
<path d="M122.8 97.8h1.4v.3h-1.4z"/>
<path d="M122.8 98.4h1.4v.3l-1.4 .1z"/>
<path d="M122.8 99.1h1.4v.3h-1.4z"/>
<path d="M122.8 99.7h1.4v.3l-1.4 .1z"/>
<path d="M122.8 100.4h1.4v.3h-1.4z"/>
<path d="M122.8 101h1.4v.3l-1.4 .1z"/>
<path d="M130 112.6h1.4l.1 .3-1.4 .1z"/>
<path d="M130 111.9h1.4l.1 .3-1.4 .1z"/>
<path d="M130 111.3h1.4l.1 .3-1.4 .1z"/>
<path d="M130 110.6h1.4l.1 .3-1.4 .1z"/>
<path d="M130 110h1.4l.1 .3-1.4 .1z"/>
<path d="M130 109.3h1.4l.1 .3-1.4 .1z"/>
<path d="M130 108.7h1.4l.1 .3-1.4 .1z"/>
<path d="M130 108h1.4l.1 .3-1.4 .1z"/>
<path d="M124.3 108h1.4l.1 .3-1.4 .1z"/>
<path d="M124.3 108.7h1.4l.1 .3-1.4 .1z"/>
<path d="M124.3 109.3h1.4l.1 .3-1.4 .1z"/>
<path d="M124.3 110h1.4l.1 .3-1.4 .1z"/>
<path d="M124.3 110.6h1.4l.1 .3-1.4 .1z"/>
<path d="M124.3 111.3h1.4l.1 .3-1.4 .1z"/>
<path d="M124.3 111.9h1.4l.1 .3-1.4 .1z"/>
<path d="M124.3 112.6h1.4l.1 .3-1.4 .1z"/>
<path d="M119.3 70.6h.4l.1 .1v1.7l-.1 .1-.5-.1z"/>
<path d="M118 70.6h.4l.1 .1v1.7l-.1 .1-.5-.1z"/>
<path d="M116.7 70.6h.4l.2 .1v1.7l-.1 .1-.5-.1z"/>
<path d="M115.4 70.6h.4l.2 .1v1.7l-.1 .1-.5-.1z"/>
<path d="M115.4 77.6h.4l.2 .1v1.7l-.1 .1-.5-.1z"/>
<path d="M116.7 77.6h.4l.2 .1v1.7l-.1 .1-.5-.1z"/>
<path d="M118 77.6h.4l.1 .1v1.7l-.1 .1-.5-.1z"/>
<path d="M119.3 77.6h.4l.1 .1v1.7l-.1 .1-.5-.1z"/>
<path d="M119.2 82.3h.9v1.3h-.9z"/>
<path d="M116.2 82.3h.9v1.3h-.9z"/>
<path d="M117.7 82.3h.9v1.5h.4v3.1h-1.8v-3.1h.5z"/>
<path d="M131 97.8h.6v.5h-.6z"/>
<path d="M131 96.8h.6v.5h-.6z"/>
<path d="M132.2 107.8h.5v.5h-.5z"/>
<path d="M132.2 108.9h.5v.4h-.5z"/>
<path d="M121.4 68.9h.5v.6h-.5z"/>
<path d="M117.1 68h.5v.6h-.5z"/>
<path d="M117.1 65.6h.5v.6h-.5z"/>
<path d="M119.2 69h.6v.4h-.6z"/>
<path d="M119.2 68h.6v.4h-.6z"/>
<path d="M118.1 80.5h.7v.8h-.7z"/>
<path d="M119.6 80.5h.8v.8h-.8z"/>
<path d="M116.2 80.5h.8v.8h-.8z"/>
<path d="M146.8 80.5h.5v.5h-.5z"/>
<path d="M146.8 79.5h.5v.5h-.5z"/>
<path d="M162.5 79.5h.5v.5h-.5z"/>
<path d="M161.6 79.5h.5v.5h-.5z"/>
<path d="M157.8 95h.9v.8h-.9z"/>
<path d="M157.8 93.5h.9v.8h-.9z"/>
<path d="M162.6 98.9h.5v.6h-.5z"/>
<path d="M161.4 98.9h.5v.6h-.5z"/>
<path d="M160.4 98.9h.5v.6h-.5z"/>
<path d="M160.7 101.1h.8v.5h-.8z"/>
<path d="M162.4 101.1h.7v.5h-.7z"/>
<path d="M161.5 90h.6v.5h-.6z"/>
<path d="M161.5 89.1h.6v.4h-.6z"/>
<path d="M147.1 73.8l1.7-.1 .1 .2v.7l-.2 .1h-1.5l-.2-.2z"/>
<path d="M126.4 71.6h.4v.6h-.4z"/>
<path d="M127.2 67.6h.6v.4h-.6z"/>
<path d="M159 81h.5v.6h-.5z"/>
<path d="M158 81h.5v.6h-.5z"/>
<path d="M123.2 73h.5v.5h-.5z"/>
<path d="M124.2 73h.5v.5h-.5z"/>
<path d="M147.2 69.3h.5v.6h-.5z"/>
<path d="M148.2 69.3h.5v.6h-.5z"/>
<path d="M148.2 79.8l1.2-.1 .2 .2-.1 .6-.2 .2h-1l-.2-.3z"/>
<path d="M148.2 77.9l1.2-.1 .2 .2-.1 .6-.2 .2h-1l-.2-.3z"/>
<path d="M161.6 73.6h.5v.6h-.5z"/>
<path d="M162.5 73.6h.5v.6h-.5z"/>
<path d="M152.7 72h.5v.5h-.5z"/>
<path d="M159.4 101.1h.5v.5h-.5z"/>
<path d="M158.4 101.1h.5v.5h-.5z"/>
<path d="M164.8 102h.5v.5h-.5z"/>
<path d="M129.8 67.5h.5v.6h-.5z"/>
<path d="M144.4 70.8h1.5v.6h-1.5z"/>
<path d="M144.4 71.6h1.5v.6h-1.5z"/>
<path d="M144.4 72.4h1.5v.6h-1.5z"/>
<path d="M144.4 73.2h1.5v.6h-1.5z"/>
<path d="M144.4 74h1.5v.6h-1.5z"/>
<path d="M144.4 74.8h1.5v.6h-1.5z"/>
<path d="M144.4 75.6h1.5v.6h-1.5z"/>
<path d="M144.4 76.4h1.5v.6h-1.5z"/>
<path d="M144.4 77.2h1.5v.6h-1.5z"/>
<path d="M144.4 78h1.5v.6h-1.5z"/>
<path d="M144.4 78.8h1.5v.6h-1.5z"/>
<path d="M144.4 79.6h1.5v.6h-1.5z"/>
<path d="M144.4 80.4h1.5v.6h-1.5z"/>
<path d="M144.4 81.2h1.5v.6h-1.5z"/>
<path d="M144.4 82h1.5v.6h-1.5z"/>
<path d="M144.4 82.8h1.5v.6h-1.5z"/>
<path d="M143.1 84h.6v1.5h-.6z"/>
<path d="M142.3 84h.6v1.5h-.6z"/>
<path d="M141.5 84h.6v1.5h-.6z"/>
<path d="M140.7 84h.6v1.5h-.6z"/>
<path d="M139.9 84h.6v1.5h-.6z"/>
<path d="M139.1 84h.6v1.5h-.6z"/>
<path d="M138.3 84h.6v1.5h-.6z"/>
<path d="M137.5 84h.6v1.5h-.6z"/>
<path d="M136.7 84h.6v1.5h-.6z"/>
<path d="M135.9 84h.6v1.5h-.6z"/>
<path d="M135.1 84h.6v1.5h-.6z"/>
<path d="M134.3 84h.6v1.5h-.6z"/>
<path d="M133.5 84h.6v1.5h-.6z"/>
<path d="M132.7 84h.6v1.5h-.6z"/>
<path d="M131.9 84h.6v1.5h-.6z"/>
<path d="M131.1 84h.6v1.5h-.6z"/>
<path d="M129 82.8h1.5v.6h-1.5z"/>
<path d="M129 82h1.5v.6h-1.5z"/>
<path d="M129 81.2h1.5v.6h-1.5z"/>
<path d="M129 80.4h1.5v.6h-1.5z"/>
<path d="M129 79.6h1.5v.6h-1.5z"/>
<path d="M129 78.8h1.5v.6h-1.5z"/>
<path d="M129 78h1.5v.6h-1.5z"/>
<path d="M129 77.2h1.5v.6h-1.5z"/>
<path d="M129 76.4h1.5v.6h-1.5z"/>
<path d="M129 75.6h1.5v.6h-1.5z"/>
<path d="M129 74.8h1.5v.6h-1.5z"/>
<path d="M129 74h1.5v.6h-1.5z"/>
<path d="M129 73.2h1.5v.6h-1.5z"/>
<path d="M129 72.4h1.5v.6h-1.5z"/>
<path d="M129 71.6h1.5v.6h-1.5z"/>
<path d="M129 70.8h1.5v.6h-1.5z"/>
<path d="M134.3 68.6h.6v1.5h-.6z"/>
<path d="M135.1 68.6h.6v1.5h-.6z"/>
<path d="M135.9 68.6h.6v1.5h-.6z"/>
<path d="M136.7 68.6h.6v1.5h-.6z"/>
<path d="M137.5 68.6h.6v1.5h-.6z"/>
<path d="M138.3 68.6h.6v1.5h-.6z"/>
<path d="M139.1 68.6h.6v1.5h-.6z"/>
<path d="M139.9 68.6h.6v1.5h-.6z"/>
<path d="M140.7 68.6h.6v1.5h-.6z"/>
<path d="M141.5 68.6h.6v1.5h-.6z"/>
<path d="M142.3 68.6h.6v1.5h-.6z"/>
<path d="M143.1 68.6h.6v1.5h-.6z"/>
<path d="M162.6 77.2h1.2v1.4h-1.2z"/>
<path d="M162.6 75h1.2v1.4h-1.2z"/>
<path d="M117.3 107.1h1.7v1.7h-1.7z"/>
<path d="M117.3 109.6h1.7v1.7h-1.7z"/>
<path d="M117.3 112.2h1.7v1.7h-1.7z"/>
<path d="M117.3 114.7h1.7v1.7h-1.7z"/>
<path d="M99.5 107.1h1.7v1.7h-1.7z"/>
<path d="M99.5 109.6h1.7v1.7h-1.7z"/>
<path d="M99.5 112.2h1.7v1.7h-1.7z"/>
<path d="M99.5 114.7h1.7v1.7h-1.7z"/>
<path d="M117.3 91.9h1.7v1.7h-1.7z"/>
<path d="M117.3 94.4h1.7v1.7h-1.7z"/>
<path d="M117.3 96.9h1.7v1.7h-1.7z"/>
<path d="M117.3 99.5h1.7v1.7h-1.7z"/>
<path d="M99.5 91.9h1.7v1.7h-1.7z"/>
<path d="M99.5 94.4h1.7v1.7h-1.7z"/>
<path d="M99.5 96.9h1.7v1.7h-1.7z"/>
<path d="M99.5 99.5h1.7v1.7h-1.7z"/>
<path d="M135 99.9h1.7v1.7h-1.7z"/>
<path d="M135 97.3h1.7v1.7h-1.7z"/>
<path d="M135 94.8h1.7v1.7h-1.7z"/>
<path d="M135 92.2h1.7v1.7h-1.7z"/>
<path d="M152.8 99.9h1.7v1.7h-1.7z"/>
<path d="M152.8 97.3h1.7v1.7h-1.7z"/>
<path d="M152.8 94.8h1.7v1.7h-1.7z"/>
<path d="M152.8 92.2h1.7v1.7h-1.7z"/>
<path d="M136.2 115.5h1.7v1.7h-1.7z"/>
<path d="M136.2 112.9h1.7v1.7h-1.7z"/>
<path d="M136.2 110.4h1.7v1.7h-1.7z"/>
<path d="M136.2 107.9h1.7v1.7h-1.7z"/>
<path d="M154 115.5h1.7v1.7h-1.7z"/>
<path d="M154 112.9h1.7v1.7h-1.7z"/>
<path d="M154 110.4h1.7v1.7h-1.7z"/>
<path d="M154 107.9h1.7v1.7h-1.7z"/>
<path d="M102.5 123.1h1.7v1.7h-1.7z"/>
<path d="M105.1 123.1h1.7v1.7h-1.7z"/>
<path d="M107.6 123.1h1.7v1.7h-1.7z"/>
<path d="M110.1 123.1h1.7v1.7h-1.7z"/>
<path d="M102.5 140.9h1.7v1.7h-1.7z"/>
<path d="M105.1 140.9h1.7v1.7h-1.7z"/>
<path d="M107.6 140.9h1.7v1.7h-1.7z"/>
<path d="M110.1 140.9h1.7v1.7h-1.7z"/>
<path d="M150.5 123.1h1.7v1.7h-1.7z"/>
<path d="M153.1 123.1h1.7v1.7h-1.7z"/>
<path d="M155.6 123.1h1.7v1.7h-1.7z"/>
<path d="M158.2 123.1h1.7v1.7h-1.7z"/>
<path d="M150.5 140.9h1.7v1.7h-1.7z"/>
<path d="M153.1 140.9h1.7v1.7h-1.7z"/>
<path d="M155.6 140.9h1.7v1.7h-1.7z"/>
<path d="M158.2 140.9h1.7v1.7h-1.7z"/>
<path d="M118.5 123.1h1.7v1.7h-1.7z"/>
<path d="M121.1 123.1h1.7v1.7h-1.7z"/>
<path d="M123.6 123.1h1.7v1.7h-1.7z"/>
<path d="M126.2 123.1h1.6v1.7h-1.6z"/>
<path d="M118.5 140.9h1.7v1.7h-1.7z"/>
<path d="M121.1 140.9h1.7v1.7h-1.7z"/>
<path d="M123.6 140.9h1.7v1.7h-1.7z"/>
<path d="M126.2 140.9h1.6v1.7h-1.6z"/>
<path d="M134.5 123.1h1.7v1.7h-1.7z"/>
<path d="M137.1 123.1h1.7v1.7h-1.7z"/>
<path d="M139.6 123.1h1.7v1.7h-1.7z"/>
<path d="M142.2 123.1h1.7v1.7h-1.7z"/>
<path d="M134.5 140.9h1.7v1.7h-1.7z"/>
<path d="M137.1 140.9h1.7v1.7h-1.7z"/>
<path d="M139.6 140.9h1.7v1.7h-1.7z"/>
<path d="M142.2 140.9h1.7v1.7h-1.7z"/>
<path d="M153.7 79h.4v1.4h-.4z"/>
<path d="M154.4 79h.4l-.1 1.4h-.3z"/>
<path d="M155 79h.4v1.4h-.4z"/>
<path d="M155.7 79h.4l-.1 1.4h-.3z"/>
<path d="M156.3 79h.4v1.4h-.4z"/>
<path d="M157 79h.4l-.1 1.4h-.3z"/>
<path d="M157.6 79h.4v1.4h-.4z"/>
<path d="M158.3 79h.4l-.1 1.4h-.3z"/>
<path d="M158.9 79h.4v1.4h-.4z"/>
<path d="M159.6 79h.4l-.1 1.4h-.3z"/>
<path d="M159.6 73.3h.4l-.1 1.4-.3-.1z"/>
<path d="M158.9 73.3h.4v1.4l-.4-.1z"/>
<path d="M158.3 73.3h.4l-.1 1.4-.3-.1z"/>
<path d="M157.6 73.3h.4v1.4l-.4-.1z"/>
<path d="M157 73.3h.4l-.1 1.4-.3-.1z"/>
<path d="M156.3 73.3h.4v1.4l-.4-.1z"/>
<path d="M155.7 73.3h.4l-.1 1.4-.3-.1z"/>
<path d="M155 73.3h.4v1.4l-.4-.1z"/>
<path d="M154.4 73.3h.4l-.1 1.4-.3-.1z"/>
<path d="M153.7 73.3h.4v1.4l-.4-.1z"/>
<path d="M164.1 91.3h.4l.1 .1v1.7l-.1 .1-.5-.1z"/>
<path d="M162.8 91.3h.4l.2 .1v1.7l-.1 .1-.5-.1z"/>
<path d="M161.5 91.3h.4l.2 .1v1.7l-.1 .1-.5-.1z"/>
<path d="M160.3 91.3h.4l.1 .1v1.7l-.1 .1-.5-.1z"/>
<path d="M160.3 96.3l.4-.1 .1 .1v1.7l-.1 .2-.5-.1z"/>
<path d="M161.5 96.3l.4-.1 .2 .1v1.7l-.1 .2-.5-.1z"/>
<path d="M162.8 96.3l.4-.1 .2 .1v1.7l-.1 .2-.5-.1z"/>
<path d="M124.2 78.8h.5v.6h-.5z"/>
<path d="M123.2 78.8h.5v.6h-.5z"/>
<path d="M151 86.1h.8v2.4h-.8z"/>
<path d="M151 82.2h.8v2.4h-.8z"/>
<path d="M152.3 86.1h.7v2.4h-.7z"/>
<path d="M152.3 82.2h.7v2.4h-.7z"/>
<path d="M153.6 86.1h.7v2.4h-.7z"/>
<path d="M153.6 82.2h.7v2.4h-.7z"/>
<path d="M106.2 80.3h.9v.8h-.9z"/>
<path d="M106.2 78.4h.9v.8h-.9z"/>
<path d="M104.2 79.4h.9v.8h-.9z"/>
<path d="M108.1 80.5h.5v.5h-.5z"/>
<path d="M108.1 79.5h.5v.5h-.5z"/>
<path d="M102.7 79.5h.6v.5h-.6z"/>
<path d="M102.7 80.5h.6v.5h-.6z"/>
<path d="M124.2 76.6h1.2v1.4h-1.2z"/>
<path d="M124.2 74.4h1.2v1.4h-1.2z"/>
<path d="M122.5 74.4h1.2v1.4h-1.2z"/>
<path d="M122.5 76.6h1.2v1.4h-1.2z"/>
<path d="M91.8 73.2h.8v.7h-.8z"/>
<path d="M91.8 71.6h.8v.8h-.8z"/>
<path d="M164.2 122.1l.8-.1 .2 .2v2.2l-.1 .3h-.8l-.2-.2z"/>
<path d="M167.1 122.1l.8-.1 .2 .2v2.2l-.1 .3h-.7l-.3-.2z"/>
<path d="M96.6 123.6h.6v.5h-.6z"/>
<path d="M96.6 122.6h.6v.4h-.6z"/>
<path d="M178.7 140.4h.8v.7h-.8z"/>
<path d="M178.7 138.7h.8v.7h-.8z"/>
<path d="M158.4 113.6h.5v.5h-.5z"/>
<path d="M158.4 114.5h.5v.5h-.5z"/>
<path d="M96.4 115.1h.5v.4h-.5z"/>
<path d="M93.8 73.2h.9v.7h-.9z"/>
<path d="M156.7 83.2h.6v.5h-.6z"/>
<path d="M156.7 84.2h.6v.5h-.6z"/>
<path d="M157.8 84.2h.6v.5h-.6z"/>
<path d="M157.8 83.2h.6v.5h-.6z"/>
<path d="M96.4 117.6h.5v.5h-.5z"/>
<path d="M96.4 118.6h.5v.5h-.5z"/>
<path d="M91.8 135.1h.8v.8h-.8z"/>
<path d="M91.8 136.7h.8v.7h-.8z"/>
<path d="M166.1 115.3h2v1.5h-2z"/>
<path d="M159.8 111.9h2v3.8h-2z"/>
<path d="M166.1 113h2v1.5h-2z"/>
<path d="M166.1 110.7h2v1.5h-2z"/>
<path d="M166.7 130.9h.6v.5h-.6z"/>
<path d="M166.7 129.9h.6v.5h-.6z"/>
<path d="M98.5 86.5h.4v.5h-.4z"/>
<path d="M97.4 86.5h.5v.5h-.5z"/>
<path d="M93.8 136.7h.9v.7h-.9z"/>
<path d="M93.8 135.1h.9v.7h-.9z"/>
<path d="M164.8 128.1h.7v1h-.7z"/>
<path d="M165.8 128.1h.6v1h-.6z"/>
<path d="M166.7 128.1h.7v1h-.7z"/>
<path d="M166.7 125.9h.7v1h-.7z"/>
<path d="M164.8 125.9h.7v1h-.7z"/>
<path d="M165.5 130.9h.5v.6h-.5z"/>
<path d="M164.5 130.9h.4v.6h-.4z"/>
<path d="M178.7 70.6h.8v.7h-.8z"/>
</g>
<g fill="none" stroke="#626262" stroke-width=".14">
<path d="M98 65.9h8.8v8.8h-8.8zM104.9 78.2v.9M109 67.3v18.4M110.3 71.9v7.6h.5M111.4 64.9h54.1M112.5 71.9v7.6h-.6M115.1 72.3h-.7v5.5h.7M119.1 68.5v.4M120.1 70.6v1.7h.7v5.5h-.7M121.2 70.7v.8l-.4-.4M123.8 79.5h.3M125.6 74.2v4h-3.3"/>
<path d="M143.1 67.8h.8l-.4 .4zM152.7 79.2l.3 .4-.3 .4zM153.5 74.6v5.8M164 74.8v4h-3.3M168.5 67.3v18.4M170.8 63.7h5.2v78.8h-2.6v2.6h-2.6zM93.3 84h2.6v5.1h-2.6zM93.3 94.3h2.6v5.1h-2.6zM95.9 90.4v1.3h-1.3M101.3 89.4h-1.2v1.3M103.4 80.1v.3M104.9 80.4v.9h2.2"/>
<path d="M108 80.1v.3M111.4 88.1h38.8M112.5 80.3v.7h-1.1M115.7 81.4h.3M116 83.5h-.2v2.7h1.3M117.1 89.4h1.3v1.3M119.1 80.4h.3M120.2 82.4v1.1h.3v2.7h-1.3M121.8 94h12.3v20.2h-12.3zM130.9 97.4v.3M136.9 89.8h-1.3v1.3M146.7 80.2v.2"/>
<path d="M150.8 83.6v4.8M152.7 89.8h1.2v1.3M154.6 83.6v3.5M154.8 88.1h10.4M155.6 88.6h12.3v17.8h-12.3zM157.4 83.8v.3M157.7 83.8v.3M158.6 81.7h.3M161.4 89.7v.2M165 91.3v5.4M165.5 92.2l.4-.4v.8zM93.3 104.4h2.6v5.2h-2.6z"/>
<path d="M93.5 114.6v3.8h.6M95.7 114.6v3.8M95.9 100.7v1.3h-1.3M95.9 110.9v1.3h-1.3M97 114.6v.4M97 118.2v.3M100.1 117.6v1.3h1.2M100.1 102.4v1.2h1.2M101.3 104.6h-1.2v1.3M117.1 104.6h1.3v1.3M118.4 102.4v1.2h-1.3M118.4 117.6v1.3h-1.3"/>
<path d="M124.2 101.7h5.8M125.7 113.2h5.8M128.9 102.5l.4-.4 .4 .4zM132.5 112.8v.7l-.4-.3zM132.8 108.4v.3M135.6 102.7v1.3h1.3M136.8 118.4v1.2h1.2M138 105.4h-1.2v1.3M153.8 105.4h1.3v1.3M153.9 102.7v1.3h-1.2M155.1 118.4v1.2h-1.3M156.7 107.6h13.2v27h-6.8v-10.8l-6.4-6.3z"/>
<path d="M159 114.2v.2M159 101.7h.2M160.9 100.1h2.4M162 115.9v1.3h6.1M165.8 110.4h-3.8v1.2M92.7 136.1v.3M93.5 122.1v2.5h.6M93.7 136v.5M95.7 122.1v2.5h-.5M95.7 125.3v.8M96.5 123.2v.3M101.3 123.7h-1.2v1.3"/>
<path d="M113 123.7h1.3v1.3M117.3 123.7h-1.2v1.3M129 123.7h1.3v1.3M133.3 123.7h-1.2v1.3M145 123.7h1.3v1.3M149.4 123.7h-1.3v1.3M161 123.7h1.3v1.3M164.5 126.6v2.5M167.7 126.6v1.8M100.1 140.7v1.3h1.2M114.3 140.7v1.3h-1.3M116.1 140.7v1.3h1.2"/>
<path d="M130.3 140.7v1.3h-1.3M132.1 140.7v1.3h1.2M146.3 140.7v1.3h-1.3M148.1 140.7v1.3h1.3M162.3 140.7v1.3h-1.3M176 143.8v1.3h-1.4"/>
</g>
<g fill="none" stroke="#626262" stroke-width=".15">
<path d="M130.2 69.9v.7M144 68.6v1.3h.6v.7M178 76.6v.3l-.1 .1-.5-.1v-.3l.2-.1 .1 .5M120.8 88.5a.47 .47 0 0 0-.6 .5 .47 .47 0 0 0 .6 .4v-.4h-.2M130.2 83.6v.7h.7M133.8 88.8h.4M133.9 88.5v.8l.3 .2M144.6 83.6v.7h-.7M177 95.6l.5 .3-.5 .4M177.5 95.9h.5M98.3 128l1 .3-1 .4M100.4 120.3l-.4-.1-.2 .2 .1 .3 .4 .1v.3l-.1 .1h-.4"/>
<path d="M123 120.3a.47 .47 0 0 0-.7 .4 .47 .47 0 0 0 .5 .5l.2-.1M137.2 120.6l.3 .5 .4-.5M137.5 121.1v.5M153.9 120.6l.7 1M154.6 120.6l-.7 1"/>
</g>
<path d="M126.4 117.6l.3-.3 2.4 1.2 .1 .6-2.3-.4 2 .5a.92 .92 0 0 0 1.4-.3v-.4l-.1-.2-2.3-1.7 1.8 1.4-.6 .4-.8-.4 .9 .3a1.06 1.06 0 0 0-.9-.3l-1.1-.5 1.7 .4 .4 .2 .1-.1a2.22 2.22 0 0 0-2.2-.5l-.5-.2 .9-.2h.7l-.4-.4v-.2l1.3 .9a2.63 2.63 0 0 1 1.2 1.2v.3l-.3 .4a2.28 2.28 0 0 1-1.2 1.9 2.42 2.42 0 0 0 1-1.8l-2.9-.6a1.74 1.74 0 0 0-.2 2.3l.2 .1a2.17 2.17 0 0 1-1.3-1.7h.3a1.95 1.95 0 0 0 .7 1.5 1.97 1.97 0 0 1 0-2.4h.4l1.9 .4v-.1a.47 .47 0 0 0-.3-.6 1.01 1.01 0 0 0-1.6 .3h-.4l.4-.4 .5-.3-.4-.2a1.82 1.82 0 0 0-1.2 1.8h-.3v-.4a2.1 2.1 0 0 1 .7-1.5z" fill="#626262" stroke="#626262" stroke-width=".14"/>
<path d="M90.4 64a5.1 5.1 0 0 1 3.6-1.5h72.1l3.4-2.6h10.2a5.1 5.1 0 0 1 5.1 5.1v3.8l-3.8 3.8v64.8l3.8 3.8v3.8a5.1 5.1 0 0 1-5.1 5.1h-10.2l-5-3.8h-70.5a5.1 5.1 0 0 1-5.1-5.1v-12l3.2-2.6v-43.2l-3.2-2.5v-13.2a5.1 5.1 0 0 1 1.5-3.7z" fill="none" stroke="#ff8000" stroke-width=".14"/>
<g fill="none" stroke="#000080" stroke-width=".15">
<path d="M10 10.2h277v190.1h-277zM12 12.2h273v186.1h-273zM60 10.2v2M110 10.2v2M160 10.2v2M210 10.2v2M260 10.2v2M10 60.2h2M90 71a.47 .47 0 0 0-.7 .3 .47 .47 0 0 0 .5 .6l.2-.1M93.1 68.3l1 .3-1 .4M98 70.9h.6l-.4 .3 .3 .1v.5l-.1 .1-.4-.1M113 68.5v.6"/>
<path d="M130.4 70.1h13l1 1v13h-14zM160.5 71.6v.5M162.2 70a.47 .47 0 0 0-.6 .5 .47 .47 0 0 0 .6 .4v-.4h-.2M170 70.1l.4-.1 .2 .2-.6 .8h.6M175.7 68.4a.47 .47 0 0 0-.6 .3 .47 .47 0 0 0 .4 .6l.2-.1M183.7 68.3h.6l-.3 .4 .3 .1v.4l-.2 .1-.4-.1M285 60.2h2M97.4 86.2l.3-.2v1M97.4 87h.6M98.4 86v1M98.5 86.4l.5 .6M107.5 88.4a.47 .47 0 0 0-.6 .5 .47 .47 0 0 0 .6 .4v-.4h-.2"/>
<path d="M114 80.9l-1 .4 1 .3M115.3 88.5l.4-.1 .2 .3-.6 .7h.6M119.9 94.9h.7l-.4 1M128.4 82.6l-1 .3 1 .3M132.7 94.9h-.5v.5l.1-.1 .4 .1v.1v.3l-.1 .1-.4-.1M138.5 90.8l.3 .5 .4-.5M151.5 90.8h-.5v1h.5M158.5 89h1l-1 .6h1M161.5 81.3h-1l.7 .3-.7 .3h1M162.2 88.4a.47 .47 0 0 0-.6 .5 .47 .47 0 0 0 .6 .4v-.4h-.2M170 88.5l.4-.1 .2 .3-.6 .7h.6M10 110.2h2"/>
<path d="M102.4 116.8l.4 .5 .3-.5M102.4 101.6l.4 .5 .3-.5M115.4 116.8h-.5v1h.5M115.4 101.6h-.5v1h.5M121.5 106.5h.6l-.4 1M134.2 106.5h-.5v.5l.1-.1h.4l.1 .2-.1 .3-.1 .1-.4-.1M139.7 106.4l.3 .5 .3-.5M152.6 106.4h-.5v1h.5M158.9 109.7l.3-1 .3 1M159 109.5h.4M168.5 108.8l.1-.1a.53 .53 0 0 1 .4 .5 .53 .53 0 0 1-.4 .5l-.1-.1-.1-.2zM285 110.2h2"/>
<path d="M90.2 131.8l1 .3-1 .4M90.3 133.9a.59 .59 0 0 1 .9 .2 .57 .57 0 0 1-1-.1zM90.3 139.2a.54 .54 0 0 1 .9 .2 .57 .57 0 0 1-1-.1zM90.3 132.9a.54 .54 0 0 1 .9 .2 .57 .57 0 0 1-1-.1zM90.6 138.7h.6M91.2 138.2l-.6 .1v.2l.1 .2M112.2 138.9l.6 .4-.6 .3M112.2 126.7v.4h1v-.4M128.2 138.9l.6 .4-.6 .3M128.2 126.7v.4h1v-.4M144.2 138.9l.6 .4-.6 .3M144.2 126.7v.4h1v-.4"/>
<path d="M160.2 138.9l.6 .4-.6 .3M160.2 126.7v.4h1v-.4M90 144.6a.47 .47 0 0 0-.7 .3 .47 .47 0 0 0 .5 .6l.2-.1M91.2 140.3h-1l.3 .3M91.2 140.1v.5M98 144.5h.6l-.4 .4 .3 .1v.4l-.1 .1-.4-.1M162.2 143.9a.47 .47 0 0 0-.6 .5 .47 .47 0 0 0 .6 .4v-.4h-.2M170 144l.4-.1 .2 .3-.6 .7h.6M175.7 148.4a.47 .47 0 0 0-.6 .4 .47 .47 0 0 0 .4 .5l.2-.1M183.7 148.3h.6l-.3 .4 .3 .1v.4l-.2 .1-.4-.1M10 160.2h2M177 166.3h108v32h-108z"/>
<path d="M203.6 176.9l.3 1 .4-1M204.9 176.4l-.1 .1 .1 .1v-.1v-.1v.2M204.9 176.9v1M206.2 177l-.4-.1-.3 .3v.4l.1 .3h.2h.4M206.9 177.1a.37 .37 0 0 1 .6 0v.8M206.9 176.4v1.5M285 160.2h2M60 198.3v2M110 198.3v2M160 198.3v2M177 194.8h108M177 191.8h108"/>
<path d="M177 187.8h108M177 181.8h108M186.5 192.5l-.4 1h1M186.9 193v1M194.9 182.4v1.3l.2 .2M195.5 182.9l.4 1M196.2 182.9l-.5 1.4-.2 .1M197 191.8v3M204.1 196.7v.1h-.1l.1-.1v.1M204.9 195.4a.36 .36 0 0 1 .6 .2 .77 .77 0 0 1-.4 1.2 1 1 0 0 1-.2-1.4zM205.3 185.7l-.4-.1-.3 .3v.4l.1 .3h.2h.4M205.3 185.1v1.5"/>
<path d="M205.6 186.8h1.2M206.2 196.7l.1 .1h-.1h-.1l.1-.1v.1M207 195.5a.36 .36 0 0 1 .4-.2 .36 .36 0 0 1 .2 .3 .77 .77 0 0 1-.4 1.2 .91 .91 0 0 1-.2-1.3zM207.1 185.7l.5-.1 .3 .3v.4l-.2 .3h-.1h-.5M207.1 185.6v1.5M208.2 195.1a1.72 1.72 0 0 1 0 2.3M209.1 185.7l-.4-.1-.3 .3v.4l.2 .3h.1h.4M209.8 185.7l.4-.1 .3 .3v.4l-.1 .3h-.2h-.4M209.8 185.1v1.5M210 198.3v2M216.2 192.7l.2-.2 .5 .1a.41 .41 0 0 1 .1 .6l-.9 .8h1M217.7 193.5h1.2"/>
<path d="M219.6 192.7a.36 .36 0 0 1 .4-.2 .36 .36 0 0 1 .3 .3 .77 .77 0 0 1-.4 1.2 .91 .91 0 0 1-.3-1.3zM221.2 193.2l-.1-.1a.31 .31 0 0 1-.2-.3 .31 .31 0 0 1 .3-.3l.4 .1a.31 .31 0 0 1 .2 .3 .31 .31 0 0 1-.3 .3h-.3l-.3 .3 .1 .4 .2 .1h.3l.3-.3-.1-.4-.2-.1M260 198.3v2M261 191.8v6.5M269.9 195.3l-1.3 1.9M270.3 195.8l.4-.5v1.5M270.3 196.8h.8"/>
</g>
<path d="M225.6 189.2a.66 .66 0 0 0-1 .3l-.1 .6 .2 .3 .1 .1 .6-.1M225.7 188.5l-.3 2M226.5 189.1l-.1 1.1 .1 .2a.57 .57 0 0 0 .8-.1M227.4 189.1l-.2 1.4M228.4 188.5l-.2 1.7 .1 .2 .2 .1M229.2 189.8l1-.2-.1-.4-.1-.1-.6 .1-.1 .2-.1 .8v.2l.2 .1 .6-.1" fill="none" stroke="#000080" stroke-width=".4"/>
<path d="M209.9 179.4v1.5h.7M211.1 179.4v1.5h.7M213.2 179.6a.6 .6 0 0 0-.7 0 .6 .6 0 0 0-.2 .7 .56 .56 0 0 0 .3 .6 .56 .56 0 0 0 .6-.1" fill="none" stroke="#000080" stroke-width=".3"/>
<g fill="none" stroke="#000080" stroke-width=".14">
<path d="M91.8 72v1.6h.8M94.6 72v1.6h-.8M102.7 79.7h.6v1.1h-.6M105 78.2v3.1h.8l.6-.6v-2.4M108.6 79.7h-.5v1.1h.5M110.3 72v8.9h1.6l.5-.5v-8.4M114.5 72.4h5.2l1 1v4.3h-6.2zM119.8 68.2h-.6v1h.6M122.7 74.6h2.5v3.2h-2.5zM123.5 73.5v-.5h1v.5M123.5 78.9v.5h1v-.5M125.2 76.8l-1 1"/>
<path d="M126.6 71.6v.5M127.2 67.8h.6M130 67.6v.5M147.2 71v3.2h1.6v-3.2M147.3 79.8h-.5v1h.5M147.5 69.8v-.5h1v.5M148.2 78.2h1.3v2h-1.3M152.9 72v.5h1M153.6 74.6h6.5v4.4h-5.5l-1-1zM161.1 75.2h2.5v3.2h-2.5zM162.8 73.7v.5M162.8 79.5v.5h-1"/>
<path d="M163.6 77.4l-1 1M170.8 63.7h5.1v80.1l-1.3 1.2h-3.8zM178.7 69.4v1.6h.8v-1.6M93.3 84.1h2.6v7l-.7 .6h-1.9zM93.3 94.3h2.6v7l-.7 .7h-1.9zM97.6 86.5v.5h1.1v-.5M115 80.5h1.6v.8h-1.6M115.9 83.6h3.5l1 1v1.5h-4.5zM118.4 80.5h1.6v.8h-1.6zM124.2 96.4h4.4v4l-1 1h-3.4zM131.6 97h-.6v1.1h.6M150.7 83.6h3.9v3.4h-3.4l-.5-.4z"/>
<path d="M151.2 83.6v-1h.4v1M151.2 87v1.1h.4v-1.1M152.5 83.6v-1h.4v1M152.5 87v1.1h.4v-1.1M153.7 83.6v-1h.4v1M153.7 87v1.1h.4v-1.1M156.7 83.4h.5v1.1h-.5M158.2 81v.5h1.1v-.5M158.4 83.4h-.6v1.1h.6M158.6 93.9h-.8v1.6h.8M160 92.8h3.9l1 1v2.9h-4.9zM160.7 98.9v.5"/>
<path d="M161.7 98.9v.5M162 89.3h-.5v1h.5M163.8 98.9h-1v.5M93.3 104.5h2.6v7l-.7 .6h-1.9zM93.6 114.7v5.1h1.5M95.7 114.7v4.5M96.4 117.8h.5v1.1h-.5M96.9 114.3v1h-.5M125.7 108h4.4v4l-1 1h-3.4zM132.7 108.1v1h-.5M158.4 113.8h.5v1h-.5M162.1 110.4h3.7v5.7l-1 1h-2.7z"/>
<path d="M164.1 102h1v.5M91.8 135.5h.8v1.6h-.8M93.6 122.2v3.8h1.5l.6-.5v-3.3M94.6 135.5h-.8v1.6h.8M97.2 122.8h-.6v1h.6M164.5 122.1h3.2v2.5h-3.2zM164.6 126.6h3.1v1.8h-2.5l-.6-.6zM164.7 130.9v.6h1.1v-.6M166.8 131.1h.5M166.8 131h.5M167.3 130.2h-.5v1h.5M178.7 139.1h.8v1.6h-.8z"/>
</g>
<use href="#words"/>
</svg>
